VERSION 5.8 ;
BUSBITCHARS "[]" ;
DIVIDERCHAR "/" ;
UNITS
    DATABASE MICRONS 1000 ;
END UNITS

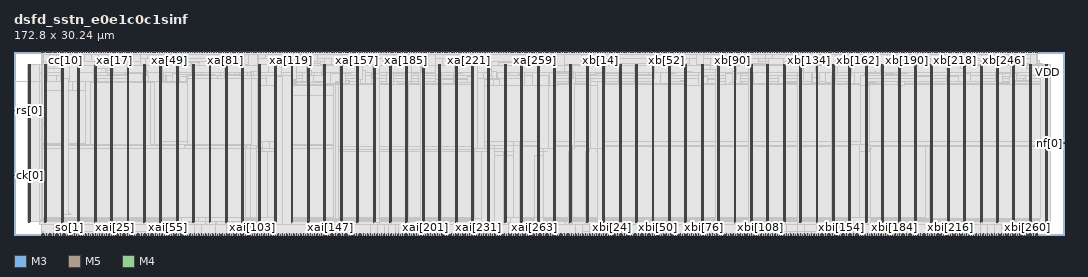
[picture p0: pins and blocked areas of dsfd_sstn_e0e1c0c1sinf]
MACRO dsfd_sstn_e0e1c0c1sinf
  FOREIGN dsfd_sstn_e0e1c0c1sinf 0 0 ;
  CLASS BLOCK ;
  SIZE 172.8 BY 30.24 ;
  PIN c0[0]
    DIRECTION INPUT ;
    USE SIGNAL ;
    PORT
      LAYER M3 ;
        RECT  4.464 30.096 4.482 30.24 ;
    END
  END c0[0]
  PIN c0[1]
    DIRECTION INPUT ;
    USE SIGNAL ;
    PORT
      LAYER M5 ;
        RECT  4.752 30.048 4.776 30.24 ;
    END
  END c0[1]
  PIN c1[0]
    DIRECTION INPUT ;
    USE SIGNAL ;
    PORT
      LAYER M3 ;
        RECT  5.04 30.096 5.058 30.24 ;
    END
  END c1[0]
  PIN c1[1]
    DIRECTION INPUT ;
    USE SIGNAL ;
    PORT
      LAYER M5 ;
        RECT  5.328 30.048 5.352 30.24 ;
    END
  END c1[1]
  PIN cc[0]
    DIRECTION OUTPUT ;
    USE SIGNAL ;
    PORT
      LAYER M3 ;
        RECT  5.58 30.096 5.598 30.24 ;
    END
  END cc[0]
  PIN cc[10]
    DIRECTION OUTPUT ;
    USE SIGNAL ;
    PORT
      LAYER M3 ;
        RECT  8.46 30.096 8.478 30.24 ;
    END
  END cc[10]
  PIN cc[11]
    DIRECTION OUTPUT ;
    USE SIGNAL ;
    PORT
      LAYER M5 ;
        RECT  8.736 30.048 8.76 30.24 ;
    END
  END cc[11]
  PIN cc[12]
    DIRECTION OUTPUT ;
    USE SIGNAL ;
    PORT
      LAYER M3 ;
        RECT  9.036 30.096 9.054 30.24 ;
    END
  END cc[12]
  PIN cc[13]
    DIRECTION OUTPUT ;
    USE SIGNAL ;
    PORT
      LAYER M5 ;
        RECT  9.312 30.048 9.336 30.24 ;
    END
  END cc[13]
  PIN cc[14]
    DIRECTION OUTPUT ;
    USE SIGNAL ;
    PORT
      LAYER M3 ;
        RECT  9.612 30.096 9.63 30.24 ;
    END
  END cc[14]
  PIN cc[1]
    DIRECTION OUTPUT ;
    USE SIGNAL ;
    PORT
      LAYER M5 ;
        RECT  5.904 30.048 5.928 30.24 ;
    END
  END cc[1]
  PIN cc[2]
    DIRECTION OUTPUT ;
    USE SIGNAL ;
    PORT
      LAYER M3 ;
        RECT  6.156 30.096 6.174 30.24 ;
    END
  END cc[2]
  PIN cc[3]
    DIRECTION OUTPUT ;
    USE SIGNAL ;
    PORT
      LAYER M5 ;
        RECT  6.432 30.048 6.456 30.24 ;
    END
  END cc[3]
  PIN cc[4]
    DIRECTION OUTPUT ;
    USE SIGNAL ;
    PORT
      LAYER M3 ;
        RECT  6.732 30.096 6.75 30.24 ;
    END
  END cc[4]
  PIN cc[5]
    DIRECTION OUTPUT ;
    USE SIGNAL ;
    PORT
      LAYER M5 ;
        RECT  7.008 30.048 7.032 30.24 ;
    END
  END cc[5]
  PIN cc[6]
    DIRECTION OUTPUT ;
    USE SIGNAL ;
    PORT
      LAYER M3 ;
        RECT  7.308 30.096 7.326 30.24 ;
    END
  END cc[6]
  PIN cc[7]
    DIRECTION OUTPUT ;
    USE SIGNAL ;
    PORT
      LAYER M5 ;
        RECT  7.584 30.048 7.608 30.24 ;
    END
  END cc[7]
  PIN cc[8]
    DIRECTION OUTPUT ;
    USE SIGNAL ;
    PORT
      LAYER M3 ;
        RECT  7.884 30.096 7.902 30.24 ;
    END
  END cc[8]
  PIN cc[9]
    DIRECTION OUTPUT ;
    USE SIGNAL ;
    PORT
      LAYER M5 ;
        RECT  8.16 30.048 8.184 30.24 ;
    END
  END cc[9]
  PIN cci[0]
    DIRECTION INPUT ;
    USE SIGNAL ;
    PORT
      LAYER M3 ;
        RECT  4.464 0 4.482 0.144 ;
    END
  END cci[0]
  PIN cci[10]
    DIRECTION INPUT ;
    USE SIGNAL ;
    PORT
      LAYER M3 ;
        RECT  7.344 0 7.362 0.144 ;
    END
  END cci[10]
  PIN cci[11]
    DIRECTION INPUT ;
    USE SIGNAL ;
    PORT
      LAYER M5 ;
        RECT  7.632 0 7.656 0.192 ;
    END
  END cci[11]
  PIN cci[12]
    DIRECTION INPUT ;
    USE SIGNAL ;
    PORT
      LAYER M3 ;
        RECT  7.92 0 7.938 0.144 ;
    END
  END cci[12]
  PIN cci[13]
    DIRECTION INPUT ;
    USE SIGNAL ;
    PORT
      LAYER M5 ;
        RECT  8.208 0 8.232 0.192 ;
    END
  END cci[13]
  PIN cci[14]
    DIRECTION INPUT ;
    USE SIGNAL ;
    PORT
      LAYER M3 ;
        RECT  8.532 0 8.55 0.144 ;
    END
  END cci[14]
  PIN cci[1]
    DIRECTION INPUT ;
    USE SIGNAL ;
    PORT
      LAYER M5 ;
        RECT  4.752 0 4.776 0.192 ;
    END
  END cci[1]
  PIN cci[2]
    DIRECTION INPUT ;
    USE SIGNAL ;
    PORT
      LAYER M3 ;
        RECT  5.04 0 5.058 0.144 ;
    END
  END cci[2]
  PIN cci[3]
    DIRECTION INPUT ;
    USE SIGNAL ;
    PORT
      LAYER M5 ;
        RECT  5.328 0 5.352 0.192 ;
    END
  END cci[3]
  PIN cci[4]
    DIRECTION INPUT ;
    USE SIGNAL ;
    PORT
      LAYER M3 ;
        RECT  5.616 0 5.634 0.144 ;
    END
  END cci[4]
  PIN cci[5]
    DIRECTION INPUT ;
    USE SIGNAL ;
    PORT
      LAYER M5 ;
        RECT  5.904 0 5.928 0.192 ;
    END
  END cci[5]
  PIN cci[6]
    DIRECTION INPUT ;
    USE SIGNAL ;
    PORT
      LAYER M3 ;
        RECT  6.192 0 6.21 0.144 ;
    END
  END cci[6]
  PIN cci[7]
    DIRECTION INPUT ;
    USE SIGNAL ;
    PORT
      LAYER M5 ;
        RECT  6.48 0 6.504 0.192 ;
    END
  END cci[7]
  PIN cci[8]
    DIRECTION INPUT ;
    USE SIGNAL ;
    PORT
      LAYER M3 ;
        RECT  6.768 0 6.786 0.144 ;
    END
  END cci[8]
  PIN cci[9]
    DIRECTION INPUT ;
    USE SIGNAL ;
    PORT
      LAYER M5 ;
        RECT  7.056 0 7.08 0.192 ;
    END
  END cci[9]
  PIN ck[0]
    DIRECTION INPUT ;
    USE SIGNAL ;
    PORT
      LAYER M4 ;
        RECT  0 9.744 0.192 9.768 ;
    END
    PORT
      LAYER M4 ;
        RECT  0.156 9.744 0.275 9.768 ;
    END
  END ck[0]
  PIN e0[0]
    DIRECTION INPUT ;
    USE SIGNAL ;
    PORT
      LAYER M5 ;
        RECT  9.888 30.048 9.912 30.24 ;
    END
  END e0[0]
  PIN e0[1]
    DIRECTION INPUT ;
    USE SIGNAL ;
    PORT
      LAYER M3 ;
        RECT  10.188 30.096 10.206 30.24 ;
    END
  END e0[1]
  PIN e1[0]
    DIRECTION INPUT ;
    USE SIGNAL ;
    PORT
      LAYER M5 ;
        RECT  10.464 30.048 10.488 30.24 ;
    END
  END e1[0]
  PIN e1[1]
    DIRECTION INPUT ;
    USE SIGNAL ;
    PORT
      LAYER M3 ;
        RECT  10.728 30.096 10.746 30.24 ;
    END
  END e1[1]
  PIN nf[0]
    DIRECTION INPUT ;
    USE SIGNAL ;
    PORT
      LAYER M4 ;
        RECT  172.608 15.12 172.8 15.144 ;
    END
    PORT
      LAYER M4 ;
        RECT  172.141 15.12 172.62 15.144 ;
    END
  END nf[0]
  PIN rs[0]
    DIRECTION INPUT ;
    USE SIGNAL ;
    PORT
      LAYER M4 ;
        RECT  0 20.544 0.192 20.568 ;
    END
    PORT
      LAYER M4 ;
        RECT  0.156 20.544 0.245 20.568 ;
    END
  END rs[0]
  PIN si[0]
    DIRECTION INPUT ;
    USE SIGNAL ;
    PORT
      LAYER M5 ;
        RECT  11.04 30.048 11.064 30.24 ;
    END
  END si[0]
  PIN si[1]
    DIRECTION INPUT ;
    USE SIGNAL ;
    PORT
      LAYER M3 ;
        RECT  11.304 30.096 11.322 30.24 ;
    END
  END si[1]
  PIN so[0]
    DIRECTION OUTPUT ;
    USE SIGNAL ;
    PORT
      LAYER M5 ;
        RECT  8.784 0 8.808 0.192 ;
    END
  END so[0]
  PIN so[1]
    DIRECTION OUTPUT ;
    USE SIGNAL ;
    PORT
      LAYER M3 ;
        RECT  9.108 0 9.126 0.144 ;
    END
  END so[1]
  PIN xa[0]
    DIRECTION OUTPUT ;
    USE SIGNAL ;
    PORT
      LAYER M5 ;
        RECT  11.616 30.048 11.64 30.24 ;
    END
  END xa[0]
  PIN xa[100]
    DIRECTION OUTPUT ;
    USE SIGNAL ;
    PORT
      LAYER M5 ;
        RECT  40.224 30.048 40.248 30.24 ;
    END
  END xa[100]
  PIN xa[101]
    DIRECTION OUTPUT ;
    USE SIGNAL ;
    PORT
      LAYER M3 ;
        RECT  40.5 30.096 40.518 30.24 ;
    END
  END xa[101]
  PIN xa[102]
    DIRECTION OUTPUT ;
    USE SIGNAL ;
    PORT
      LAYER M5 ;
        RECT  40.752 30.048 40.776 30.24 ;
    END
  END xa[102]
  PIN xa[103]
    DIRECTION OUTPUT ;
    USE SIGNAL ;
    PORT
      LAYER M3 ;
        RECT  41.076 30.096 41.094 30.24 ;
    END
  END xa[103]
  PIN xa[104]
    DIRECTION OUTPUT ;
    USE SIGNAL ;
    PORT
      LAYER M5 ;
        RECT  41.328 30.048 41.352 30.24 ;
    END
  END xa[104]
  PIN xa[105]
    DIRECTION OUTPUT ;
    USE SIGNAL ;
    PORT
      LAYER M3 ;
        RECT  41.616 30.096 41.634 30.24 ;
    END
  END xa[105]
  PIN xa[106]
    DIRECTION OUTPUT ;
    USE SIGNAL ;
    PORT
      LAYER M5 ;
        RECT  41.904 30.048 41.928 30.24 ;
    END
  END xa[106]
  PIN xa[107]
    DIRECTION OUTPUT ;
    USE SIGNAL ;
    PORT
      LAYER M3 ;
        RECT  42.192 30.096 42.21 30.24 ;
    END
  END xa[107]
  PIN xa[108]
    DIRECTION OUTPUT ;
    USE SIGNAL ;
    PORT
      LAYER M5 ;
        RECT  42.48 30.048 42.504 30.24 ;
    END
  END xa[108]
  PIN xa[109]
    DIRECTION OUTPUT ;
    USE SIGNAL ;
    PORT
      LAYER M3 ;
        RECT  42.768 30.096 42.786 30.24 ;
    END
  END xa[109]
  PIN xa[10]
    DIRECTION OUTPUT ;
    USE SIGNAL ;
    PORT
      LAYER M5 ;
        RECT  14.448 30.048 14.472 30.24 ;
    END
  END xa[10]
  PIN xa[110]
    DIRECTION OUTPUT ;
    USE SIGNAL ;
    PORT
      LAYER M5 ;
        RECT  43.056 30.048 43.08 30.24 ;
    END
  END xa[110]
  PIN xa[111]
    DIRECTION OUTPUT ;
    USE SIGNAL ;
    PORT
      LAYER M3 ;
        RECT  43.344 30.096 43.362 30.24 ;
    END
  END xa[111]
  PIN xa[112]
    DIRECTION OUTPUT ;
    USE SIGNAL ;
    PORT
      LAYER M5 ;
        RECT  43.632 30.048 43.656 30.24 ;
    END
  END xa[112]
  PIN xa[113]
    DIRECTION OUTPUT ;
    USE SIGNAL ;
    PORT
      LAYER M3 ;
        RECT  43.92 30.096 43.938 30.24 ;
    END
  END xa[113]
  PIN xa[114]
    DIRECTION OUTPUT ;
    USE SIGNAL ;
    PORT
      LAYER M5 ;
        RECT  44.208 30.048 44.232 30.24 ;
    END
  END xa[114]
  PIN xa[115]
    DIRECTION OUTPUT ;
    USE SIGNAL ;
    PORT
      LAYER M3 ;
        RECT  44.496 30.096 44.514 30.24 ;
    END
  END xa[115]
  PIN xa[116]
    DIRECTION OUTPUT ;
    USE SIGNAL ;
    PORT
      LAYER M5 ;
        RECT  44.784 30.048 44.808 30.24 ;
    END
  END xa[116]
  PIN xa[117]
    DIRECTION OUTPUT ;
    USE SIGNAL ;
    PORT
      LAYER M3 ;
        RECT  45.072 30.096 45.09 30.24 ;
    END
  END xa[117]
  PIN xa[118]
    DIRECTION OUTPUT ;
    USE SIGNAL ;
    PORT
      LAYER M5 ;
        RECT  45.36 30.048 45.384 30.24 ;
    END
  END xa[118]
  PIN xa[119]
    DIRECTION OUTPUT ;
    USE SIGNAL ;
    PORT
      LAYER M3 ;
        RECT  45.648 30.096 45.666 30.24 ;
    END
  END xa[119]
  PIN xa[11]
    DIRECTION OUTPUT ;
    USE SIGNAL ;
    PORT
      LAYER M3 ;
        RECT  14.76 30.096 14.778 30.24 ;
    END
  END xa[11]
  PIN xa[120]
    DIRECTION OUTPUT ;
    USE SIGNAL ;
    PORT
      LAYER M5 ;
        RECT  45.936 30.048 45.96 30.24 ;
    END
  END xa[120]
  PIN xa[121]
    DIRECTION OUTPUT ;
    USE SIGNAL ;
    PORT
      LAYER M3 ;
        RECT  46.224 30.096 46.242 30.24 ;
    END
  END xa[121]
  PIN xa[122]
    DIRECTION OUTPUT ;
    USE SIGNAL ;
    PORT
      LAYER M5 ;
        RECT  46.512 30.048 46.536 30.24 ;
    END
  END xa[122]
  PIN xa[123]
    DIRECTION OUTPUT ;
    USE SIGNAL ;
    PORT
      LAYER M3 ;
        RECT  46.764 30.096 46.782 30.24 ;
    END
  END xa[123]
  PIN xa[124]
    DIRECTION OUTPUT ;
    USE SIGNAL ;
    PORT
      LAYER M5 ;
        RECT  47.04 30.048 47.064 30.24 ;
    END
  END xa[124]
  PIN xa[125]
    DIRECTION OUTPUT ;
    USE SIGNAL ;
    PORT
      LAYER M3 ;
        RECT  47.34 30.096 47.358 30.24 ;
    END
  END xa[125]
  PIN xa[126]
    DIRECTION OUTPUT ;
    USE SIGNAL ;
    PORT
      LAYER M5 ;
        RECT  47.616 30.048 47.64 30.24 ;
    END
  END xa[126]
  PIN xa[127]
    DIRECTION OUTPUT ;
    USE SIGNAL ;
    PORT
      LAYER M3 ;
        RECT  47.916 30.096 47.934 30.24 ;
    END
  END xa[127]
  PIN xa[128]
    DIRECTION OUTPUT ;
    USE SIGNAL ;
    PORT
      LAYER M5 ;
        RECT  48.192 30.048 48.216 30.24 ;
    END
  END xa[128]
  PIN xa[129]
    DIRECTION OUTPUT ;
    USE SIGNAL ;
    PORT
      LAYER M3 ;
        RECT  48.492 30.096 48.51 30.24 ;
    END
  END xa[129]
  PIN xa[12]
    DIRECTION OUTPUT ;
    USE SIGNAL ;
    PORT
      LAYER M5 ;
        RECT  15.024 30.048 15.048 30.24 ;
    END
  END xa[12]
  PIN xa[130]
    DIRECTION OUTPUT ;
    USE SIGNAL ;
    PORT
      LAYER M5 ;
        RECT  48.768 30.048 48.792 30.24 ;
    END
  END xa[130]
  PIN xa[131]
    DIRECTION OUTPUT ;
    USE SIGNAL ;
    PORT
      LAYER M3 ;
        RECT  49.068 30.096 49.086 30.24 ;
    END
  END xa[131]
  PIN xa[132]
    DIRECTION OUTPUT ;
    USE SIGNAL ;
    PORT
      LAYER M5 ;
        RECT  49.344 30.048 49.368 30.24 ;
    END
  END xa[132]
  PIN xa[133]
    DIRECTION OUTPUT ;
    USE SIGNAL ;
    PORT
      LAYER M3 ;
        RECT  49.644 30.096 49.662 30.24 ;
    END
  END xa[133]
  PIN xa[134]
    DIRECTION OUTPUT ;
    USE SIGNAL ;
    PORT
      LAYER M5 ;
        RECT  49.92 30.048 49.944 30.24 ;
    END
  END xa[134]
  PIN xa[135]
    DIRECTION OUTPUT ;
    USE SIGNAL ;
    PORT
      LAYER M3 ;
        RECT  50.22 30.096 50.238 30.24 ;
    END
  END xa[135]
  PIN xa[136]
    DIRECTION OUTPUT ;
    USE SIGNAL ;
    PORT
      LAYER M5 ;
        RECT  50.496 30.048 50.52 30.24 ;
    END
  END xa[136]
  PIN xa[137]
    DIRECTION OUTPUT ;
    USE SIGNAL ;
    PORT
      LAYER M3 ;
        RECT  50.796 30.096 50.814 30.24 ;
    END
  END xa[137]
  PIN xa[138]
    DIRECTION OUTPUT ;
    USE SIGNAL ;
    PORT
      LAYER M5 ;
        RECT  51.072 30.048 51.096 30.24 ;
    END
  END xa[138]
  PIN xa[139]
    DIRECTION OUTPUT ;
    USE SIGNAL ;
    PORT
      LAYER M3 ;
        RECT  51.372 30.096 51.39 30.24 ;
    END
  END xa[139]
  PIN xa[13]
    DIRECTION OUTPUT ;
    USE SIGNAL ;
    PORT
      LAYER M3 ;
        RECT  15.336 30.096 15.354 30.24 ;
    END
  END xa[13]
  PIN xa[140]
    DIRECTION OUTPUT ;
    USE SIGNAL ;
    PORT
      LAYER M5 ;
        RECT  51.648 30.048 51.672 30.24 ;
    END
  END xa[140]
  PIN xa[141]
    DIRECTION OUTPUT ;
    USE SIGNAL ;
    PORT
      LAYER M3 ;
        RECT  51.912 30.096 51.93 30.24 ;
    END
  END xa[141]
  PIN xa[142]
    DIRECTION OUTPUT ;
    USE SIGNAL ;
    PORT
      LAYER M5 ;
        RECT  52.224 30.048 52.248 30.24 ;
    END
  END xa[142]
  PIN xa[143]
    DIRECTION OUTPUT ;
    USE SIGNAL ;
    PORT
      LAYER M3 ;
        RECT  52.488 30.096 52.506 30.24 ;
    END
  END xa[143]
  PIN xa[144]
    DIRECTION OUTPUT ;
    USE SIGNAL ;
    PORT
      LAYER M5 ;
        RECT  52.8 30.048 52.824 30.24 ;
    END
  END xa[144]
  PIN xa[145]
    DIRECTION OUTPUT ;
    USE SIGNAL ;
    PORT
      LAYER M3 ;
        RECT  53.064 30.096 53.082 30.24 ;
    END
  END xa[145]
  PIN xa[146]
    DIRECTION OUTPUT ;
    USE SIGNAL ;
    PORT
      LAYER M5 ;
        RECT  53.376 30.048 53.4 30.24 ;
    END
  END xa[146]
  PIN xa[147]
    DIRECTION OUTPUT ;
    USE SIGNAL ;
    PORT
      LAYER M3 ;
        RECT  53.64 30.096 53.658 30.24 ;
    END
  END xa[147]
  PIN xa[148]
    DIRECTION OUTPUT ;
    USE SIGNAL ;
    PORT
      LAYER M5 ;
        RECT  53.904 30.048 53.928 30.24 ;
    END
  END xa[148]
  PIN xa[149]
    DIRECTION OUTPUT ;
    USE SIGNAL ;
    PORT
      LAYER M3 ;
        RECT  54.216 30.096 54.234 30.24 ;
    END
  END xa[149]
  PIN xa[14]
    DIRECTION OUTPUT ;
    USE SIGNAL ;
    PORT
      LAYER M5 ;
        RECT  15.6 30.048 15.624 30.24 ;
    END
  END xa[14]
  PIN xa[150]
    DIRECTION OUTPUT ;
    USE SIGNAL ;
    PORT
      LAYER M5 ;
        RECT  54.48 30.048 54.504 30.24 ;
    END
  END xa[150]
  PIN xa[151]
    DIRECTION OUTPUT ;
    USE SIGNAL ;
    PORT
      LAYER M3 ;
        RECT  54.792 30.096 54.81 30.24 ;
    END
  END xa[151]
  PIN xa[152]
    DIRECTION OUTPUT ;
    USE SIGNAL ;
    PORT
      LAYER M5 ;
        RECT  55.056 30.048 55.08 30.24 ;
    END
  END xa[152]
  PIN xa[153]
    DIRECTION OUTPUT ;
    USE SIGNAL ;
    PORT
      LAYER M3 ;
        RECT  55.368 30.096 55.386 30.24 ;
    END
  END xa[153]
  PIN xa[154]
    DIRECTION OUTPUT ;
    USE SIGNAL ;
    PORT
      LAYER M5 ;
        RECT  55.632 30.048 55.656 30.24 ;
    END
  END xa[154]
  PIN xa[155]
    DIRECTION OUTPUT ;
    USE SIGNAL ;
    PORT
      LAYER M3 ;
        RECT  55.944 30.096 55.962 30.24 ;
    END
  END xa[155]
  PIN xa[156]
    DIRECTION OUTPUT ;
    USE SIGNAL ;
    PORT
      LAYER M5 ;
        RECT  56.208 30.048 56.232 30.24 ;
    END
  END xa[156]
  PIN xa[157]
    DIRECTION OUTPUT ;
    USE SIGNAL ;
    PORT
      LAYER M3 ;
        RECT  56.52 30.096 56.538 30.24 ;
    END
  END xa[157]
  PIN xa[158]
    DIRECTION OUTPUT ;
    USE SIGNAL ;
    PORT
      LAYER M5 ;
        RECT  56.784 30.048 56.808 30.24 ;
    END
  END xa[158]
  PIN xa[159]
    DIRECTION OUTPUT ;
    USE SIGNAL ;
    PORT
      LAYER M3 ;
        RECT  57.06 30.096 57.078 30.24 ;
    END
  END xa[159]
  PIN xa[15]
    DIRECTION OUTPUT ;
    USE SIGNAL ;
    PORT
      LAYER M3 ;
        RECT  15.876 30.096 15.894 30.24 ;
    END
  END xa[15]
  PIN xa[160]
    DIRECTION OUTPUT ;
    USE SIGNAL ;
    PORT
      LAYER M5 ;
        RECT  57.36 30.048 57.384 30.24 ;
    END
  END xa[160]
  PIN xa[161]
    DIRECTION OUTPUT ;
    USE SIGNAL ;
    PORT
      LAYER M3 ;
        RECT  57.636 30.096 57.654 30.24 ;
    END
  END xa[161]
  PIN xa[162]
    DIRECTION OUTPUT ;
    USE SIGNAL ;
    PORT
      LAYER M5 ;
        RECT  57.936 30.048 57.96 30.24 ;
    END
  END xa[162]
  PIN xa[163]
    DIRECTION OUTPUT ;
    USE SIGNAL ;
    PORT
      LAYER M3 ;
        RECT  58.212 30.096 58.23 30.24 ;
    END
  END xa[163]
  PIN xa[164]
    DIRECTION OUTPUT ;
    USE SIGNAL ;
    PORT
      LAYER M5 ;
        RECT  58.512 30.048 58.536 30.24 ;
    END
  END xa[164]
  PIN xa[165]
    DIRECTION OUTPUT ;
    USE SIGNAL ;
    PORT
      LAYER M3 ;
        RECT  58.788 30.096 58.806 30.24 ;
    END
  END xa[165]
  PIN xa[166]
    DIRECTION OUTPUT ;
    USE SIGNAL ;
    PORT
      LAYER M5 ;
        RECT  59.088 30.048 59.112 30.24 ;
    END
  END xa[166]
  PIN xa[167]
    DIRECTION OUTPUT ;
    USE SIGNAL ;
    PORT
      LAYER M3 ;
        RECT  59.364 30.096 59.382 30.24 ;
    END
  END xa[167]
  PIN xa[168]
    DIRECTION OUTPUT ;
    USE SIGNAL ;
    PORT
      LAYER M5 ;
        RECT  59.664 30.048 59.688 30.24 ;
    END
  END xa[168]
  PIN xa[169]
    DIRECTION OUTPUT ;
    USE SIGNAL ;
    PORT
      LAYER M3 ;
        RECT  59.94 30.096 59.958 30.24 ;
    END
  END xa[169]
  PIN xa[16]
    DIRECTION OUTPUT ;
    USE SIGNAL ;
    PORT
      LAYER M5 ;
        RECT  16.176 30.048 16.2 30.24 ;
    END
  END xa[16]
  PIN xa[170]
    DIRECTION OUTPUT ;
    USE SIGNAL ;
    PORT
      LAYER M5 ;
        RECT  60.24 30.048 60.264 30.24 ;
    END
  END xa[170]
  PIN xa[171]
    DIRECTION OUTPUT ;
    USE SIGNAL ;
    PORT
      LAYER M3 ;
        RECT  60.516 30.096 60.534 30.24 ;
    END
  END xa[171]
  PIN xa[172]
    DIRECTION OUTPUT ;
    USE SIGNAL ;
    PORT
      LAYER M5 ;
        RECT  60.768 30.048 60.792 30.24 ;
    END
  END xa[172]
  PIN xa[173]
    DIRECTION OUTPUT ;
    USE SIGNAL ;
    PORT
      LAYER M3 ;
        RECT  61.092 30.096 61.11 30.24 ;
    END
  END xa[173]
  PIN xa[174]
    DIRECTION OUTPUT ;
    USE SIGNAL ;
    PORT
      LAYER M5 ;
        RECT  61.344 30.048 61.368 30.24 ;
    END
  END xa[174]
  PIN xa[175]
    DIRECTION OUTPUT ;
    USE SIGNAL ;
    PORT
      LAYER M3 ;
        RECT  61.668 30.096 61.686 30.24 ;
    END
  END xa[175]
  PIN xa[176]
    DIRECTION OUTPUT ;
    USE SIGNAL ;
    PORT
      LAYER M5 ;
        RECT  61.92 30.048 61.944 30.24 ;
    END
  END xa[176]
  PIN xa[177]
    DIRECTION OUTPUT ;
    USE SIGNAL ;
    PORT
      LAYER M3 ;
        RECT  62.208 30.096 62.226 30.24 ;
    END
  END xa[177]
  PIN xa[178]
    DIRECTION OUTPUT ;
    USE SIGNAL ;
    PORT
      LAYER M5 ;
        RECT  62.496 30.048 62.52 30.24 ;
    END
  END xa[178]
  PIN xa[179]
    DIRECTION OUTPUT ;
    USE SIGNAL ;
    PORT
      LAYER M3 ;
        RECT  62.784 30.096 62.802 30.24 ;
    END
  END xa[179]
  PIN xa[17]
    DIRECTION OUTPUT ;
    USE SIGNAL ;
    PORT
      LAYER M3 ;
        RECT  16.452 30.096 16.47 30.24 ;
    END
  END xa[17]
  PIN xa[180]
    DIRECTION OUTPUT ;
    USE SIGNAL ;
    PORT
      LAYER M5 ;
        RECT  63.072 30.048 63.096 30.24 ;
    END
  END xa[180]
  PIN xa[181]
    DIRECTION OUTPUT ;
    USE SIGNAL ;
    PORT
      LAYER M3 ;
        RECT  63.36 30.096 63.378 30.24 ;
    END
    PORT
      LAYER M3 ;
        RECT  63.324 30.108 63.45 30.173 ;
    END
  END xa[181]
  PIN xa[182]
    DIRECTION OUTPUT ;
    USE SIGNAL ;
    PORT
      LAYER M5 ;
        RECT  63.648 30.048 63.672 30.24 ;
    END
  END xa[182]
  PIN xa[183]
    DIRECTION OUTPUT ;
    USE SIGNAL ;
    PORT
      LAYER M3 ;
        RECT  63.936 30.096 63.954 30.24 ;
    END
  END xa[183]
  PIN xa[184]
    DIRECTION OUTPUT ;
    USE SIGNAL ;
    PORT
      LAYER M5 ;
        RECT  64.224 30.048 64.248 30.24 ;
    END
  END xa[184]
  PIN xa[185]
    DIRECTION OUTPUT ;
    USE SIGNAL ;
    PORT
      LAYER M3 ;
        RECT  64.512 30.096 64.53 30.24 ;
    END
  END xa[185]
  PIN xa[186]
    DIRECTION OUTPUT ;
    USE SIGNAL ;
    PORT
      LAYER M5 ;
        RECT  64.8 30.048 64.824 30.24 ;
    END
  END xa[186]
  PIN xa[187]
    DIRECTION OUTPUT ;
    USE SIGNAL ;
    PORT
      LAYER M3 ;
        RECT  65.088 30.096 65.106 30.24 ;
    END
  END xa[187]
  PIN xa[188]
    DIRECTION OUTPUT ;
    USE SIGNAL ;
    PORT
      LAYER M5 ;
        RECT  65.376 30.048 65.4 30.24 ;
    END
  END xa[188]
  PIN xa[189]
    DIRECTION OUTPUT ;
    USE SIGNAL ;
    PORT
      LAYER M3 ;
        RECT  65.664 30.096 65.682 30.24 ;
    END
  END xa[189]
  PIN xa[18]
    DIRECTION OUTPUT ;
    USE SIGNAL ;
    PORT
      LAYER M5 ;
        RECT  16.752 30.048 16.776 30.24 ;
    END
  END xa[18]
  PIN xa[190]
    DIRECTION OUTPUT ;
    USE SIGNAL ;
    PORT
      LAYER M5 ;
        RECT  65.952 30.048 65.976 30.24 ;
    END
  END xa[190]
  PIN xa[191]
    DIRECTION OUTPUT ;
    USE SIGNAL ;
    PORT
      LAYER M3 ;
        RECT  66.24 30.096 66.258 30.24 ;
    END
  END xa[191]
  PIN xa[192]
    DIRECTION OUTPUT ;
    USE SIGNAL ;
    PORT
      LAYER M5 ;
        RECT  66.528 30.048 66.552 30.24 ;
    END
  END xa[192]
  PIN xa[193]
    DIRECTION OUTPUT ;
    USE SIGNAL ;
    PORT
      LAYER M3 ;
        RECT  66.816 30.096 66.834 30.24 ;
    END
  END xa[193]
  PIN xa[194]
    DIRECTION OUTPUT ;
    USE SIGNAL ;
    PORT
      LAYER M5 ;
        RECT  67.104 30.048 67.128 30.24 ;
    END
  END xa[194]
  PIN xa[195]
    DIRECTION OUTPUT ;
    USE SIGNAL ;
    PORT
      LAYER M3 ;
        RECT  67.356 30.096 67.374 30.24 ;
    END
  END xa[195]
  PIN xa[196]
    DIRECTION OUTPUT ;
    USE SIGNAL ;
    PORT
      LAYER M5 ;
        RECT  67.632 30.048 67.656 30.24 ;
    END
  END xa[196]
  PIN xa[197]
    DIRECTION OUTPUT ;
    USE SIGNAL ;
    PORT
      LAYER M3 ;
        RECT  67.932 30.096 67.95 30.24 ;
    END
  END xa[197]
  PIN xa[198]
    DIRECTION OUTPUT ;
    USE SIGNAL ;
    PORT
      LAYER M5 ;
        RECT  68.208 30.048 68.232 30.24 ;
    END
  END xa[198]
  PIN xa[199]
    DIRECTION OUTPUT ;
    USE SIGNAL ;
    PORT
      LAYER M3 ;
        RECT  68.508 30.096 68.526 30.24 ;
    END
  END xa[199]
  PIN xa[19]
    DIRECTION OUTPUT ;
    USE SIGNAL ;
    PORT
      LAYER M3 ;
        RECT  17.028 30.096 17.046 30.24 ;
    END
  END xa[19]
  PIN xa[1]
    DIRECTION OUTPUT ;
    USE SIGNAL ;
    PORT
      LAYER M3 ;
        RECT  11.88 30.096 11.898 30.24 ;
    END
  END xa[1]
  PIN xa[200]
    DIRECTION OUTPUT ;
    USE SIGNAL ;
    PORT
      LAYER M5 ;
        RECT  68.784 30.048 68.808 30.24 ;
    END
  END xa[200]
  PIN xa[201]
    DIRECTION OUTPUT ;
    USE SIGNAL ;
    PORT
      LAYER M3 ;
        RECT  69.084 30.096 69.102 30.24 ;
    END
  END xa[201]
  PIN xa[202]
    DIRECTION OUTPUT ;
    USE SIGNAL ;
    PORT
      LAYER M5 ;
        RECT  69.36 30.048 69.384 30.24 ;
    END
  END xa[202]
  PIN xa[203]
    DIRECTION OUTPUT ;
    USE SIGNAL ;
    PORT
      LAYER M3 ;
        RECT  69.66 30.096 69.678 30.24 ;
    END
  END xa[203]
  PIN xa[204]
    DIRECTION OUTPUT ;
    USE SIGNAL ;
    PORT
      LAYER M5 ;
        RECT  69.936 30.048 69.96 30.24 ;
    END
  END xa[204]
  PIN xa[205]
    DIRECTION OUTPUT ;
    USE SIGNAL ;
    PORT
      LAYER M3 ;
        RECT  70.236 30.096 70.254 30.24 ;
    END
  END xa[205]
  PIN xa[206]
    DIRECTION OUTPUT ;
    USE SIGNAL ;
    PORT
      LAYER M5 ;
        RECT  70.512 30.048 70.536 30.24 ;
    END
  END xa[206]
  PIN xa[207]
    DIRECTION OUTPUT ;
    USE SIGNAL ;
    PORT
      LAYER M3 ;
        RECT  70.812 30.096 70.83 30.24 ;
    END
  END xa[207]
  PIN xa[208]
    DIRECTION OUTPUT ;
    USE SIGNAL ;
    PORT
      LAYER M5 ;
        RECT  71.088 30.048 71.112 30.24 ;
    END
  END xa[208]
  PIN xa[209]
    DIRECTION OUTPUT ;
    USE SIGNAL ;
    PORT
      LAYER M3 ;
        RECT  71.388 30.096 71.406 30.24 ;
    END
  END xa[209]
  PIN xa[20]
    DIRECTION OUTPUT ;
    USE SIGNAL ;
    PORT
      LAYER M5 ;
        RECT  17.328 30.048 17.352 30.24 ;
    END
  END xa[20]
  PIN xa[210]
    DIRECTION OUTPUT ;
    USE SIGNAL ;
    PORT
      LAYER M5 ;
        RECT  71.664 30.048 71.688 30.24 ;
    END
  END xa[210]
  PIN xa[211]
    DIRECTION OUTPUT ;
    USE SIGNAL ;
    PORT
      LAYER M3 ;
        RECT  71.964 30.096 71.982 30.24 ;
    END
  END xa[211]
  PIN xa[212]
    DIRECTION OUTPUT ;
    USE SIGNAL ;
    PORT
      LAYER M5 ;
        RECT  72.24 30.048 72.264 30.24 ;
    END
  END xa[212]
  PIN xa[213]
    DIRECTION OUTPUT ;
    USE SIGNAL ;
    PORT
      LAYER M3 ;
        RECT  72.504 30.096 72.522 30.24 ;
    END
  END xa[213]
  PIN xa[214]
    DIRECTION OUTPUT ;
    USE SIGNAL ;
    PORT
      LAYER M5 ;
        RECT  72.816 30.048 72.84 30.24 ;
    END
  END xa[214]
  PIN xa[215]
    DIRECTION OUTPUT ;
    USE SIGNAL ;
    PORT
      LAYER M3 ;
        RECT  73.08 30.096 73.098 30.24 ;
    END
  END xa[215]
  PIN xa[216]
    DIRECTION OUTPUT ;
    USE SIGNAL ;
    PORT
      LAYER M5 ;
        RECT  73.392 30.048 73.416 30.24 ;
    END
  END xa[216]
  PIN xa[217]
    DIRECTION OUTPUT ;
    USE SIGNAL ;
    PORT
      LAYER M3 ;
        RECT  73.656 30.096 73.674 30.24 ;
    END
  END xa[217]
  PIN xa[218]
    DIRECTION OUTPUT ;
    USE SIGNAL ;
    PORT
      LAYER M5 ;
        RECT  73.968 30.048 73.992 30.24 ;
    END
  END xa[218]
  PIN xa[219]
    DIRECTION OUTPUT ;
    USE SIGNAL ;
    PORT
      LAYER M3 ;
        RECT  74.232 30.096 74.25 30.24 ;
    END
  END xa[219]
  PIN xa[21]
    DIRECTION OUTPUT ;
    USE SIGNAL ;
    PORT
      LAYER M3 ;
        RECT  17.604 30.096 17.622 30.24 ;
    END
  END xa[21]
  PIN xa[220]
    DIRECTION OUTPUT ;
    USE SIGNAL ;
    PORT
      LAYER M5 ;
        RECT  74.496 30.048 74.52 30.24 ;
    END
  END xa[220]
  PIN xa[221]
    DIRECTION OUTPUT ;
    USE SIGNAL ;
    PORT
      LAYER M3 ;
        RECT  74.808 30.096 74.826 30.24 ;
    END
  END xa[221]
  PIN xa[222]
    DIRECTION OUTPUT ;
    USE SIGNAL ;
    PORT
      LAYER M5 ;
        RECT  75.072 30.048 75.096 30.24 ;
    END
  END xa[222]
  PIN xa[223]
    DIRECTION OUTPUT ;
    USE SIGNAL ;
    PORT
      LAYER M3 ;
        RECT  75.384 30.096 75.402 30.24 ;
    END
  END xa[223]
  PIN xa[224]
    DIRECTION OUTPUT ;
    USE SIGNAL ;
    PORT
      LAYER M5 ;
        RECT  75.648 30.048 75.672 30.24 ;
    END
  END xa[224]
  PIN xa[225]
    DIRECTION OUTPUT ;
    USE SIGNAL ;
    PORT
      LAYER M3 ;
        RECT  75.96 30.096 75.978 30.24 ;
    END
  END xa[225]
  PIN xa[226]
    DIRECTION OUTPUT ;
    USE SIGNAL ;
    PORT
      LAYER M5 ;
        RECT  76.224 30.048 76.248 30.24 ;
    END
  END xa[226]
  PIN xa[227]
    DIRECTION OUTPUT ;
    USE SIGNAL ;
    PORT
      LAYER M3 ;
        RECT  76.536 30.096 76.554 30.24 ;
    END
  END xa[227]
  PIN xa[228]
    DIRECTION OUTPUT ;
    USE SIGNAL ;
    PORT
      LAYER M5 ;
        RECT  76.8 30.048 76.824 30.24 ;
    END
  END xa[228]
  PIN xa[229]
    DIRECTION OUTPUT ;
    USE SIGNAL ;
    PORT
      LAYER M3 ;
        RECT  77.112 30.096 77.13 30.24 ;
    END
  END xa[229]
  PIN xa[22]
    DIRECTION OUTPUT ;
    USE SIGNAL ;
    PORT
      LAYER M5 ;
        RECT  17.904 30.048 17.928 30.24 ;
    END
  END xa[22]
  PIN xa[230]
    DIRECTION OUTPUT ;
    USE SIGNAL ;
    PORT
      LAYER M5 ;
        RECT  77.376 30.048 77.4 30.24 ;
    END
  END xa[230]
  PIN xa[231]
    DIRECTION OUTPUT ;
    USE SIGNAL ;
    PORT
      LAYER M3 ;
        RECT  77.652 30.096 77.67 30.24 ;
    END
  END xa[231]
  PIN xa[232]
    DIRECTION OUTPUT ;
    USE SIGNAL ;
    PORT
      LAYER M5 ;
        RECT  77.952 30.048 77.976 30.24 ;
    END
  END xa[232]
  PIN xa[233]
    DIRECTION OUTPUT ;
    USE SIGNAL ;
    PORT
      LAYER M3 ;
        RECT  78.228 30.096 78.246 30.24 ;
    END
  END xa[233]
  PIN xa[234]
    DIRECTION OUTPUT ;
    USE SIGNAL ;
    PORT
      LAYER M5 ;
        RECT  78.528 30.048 78.552 30.24 ;
    END
  END xa[234]
  PIN xa[235]
    DIRECTION OUTPUT ;
    USE SIGNAL ;
    PORT
      LAYER M3 ;
        RECT  78.804 30.096 78.822 30.24 ;
    END
  END xa[235]
  PIN xa[236]
    DIRECTION OUTPUT ;
    USE SIGNAL ;
    PORT
      LAYER M5 ;
        RECT  79.104 30.048 79.128 30.24 ;
    END
  END xa[236]
  PIN xa[237]
    DIRECTION OUTPUT ;
    USE SIGNAL ;
    PORT
      LAYER M3 ;
        RECT  79.38 30.096 79.398 30.24 ;
    END
  END xa[237]
  PIN xa[238]
    DIRECTION OUTPUT ;
    USE SIGNAL ;
    PORT
      LAYER M5 ;
        RECT  79.68 30.048 79.704 30.24 ;
    END
  END xa[238]
  PIN xa[239]
    DIRECTION OUTPUT ;
    USE SIGNAL ;
    PORT
      LAYER M3 ;
        RECT  79.956 30.096 79.974 30.24 ;
    END
  END xa[239]
  PIN xa[23]
    DIRECTION OUTPUT ;
    USE SIGNAL ;
    PORT
      LAYER M3 ;
        RECT  18.18 30.096 18.198 30.24 ;
    END
  END xa[23]
  PIN xa[240]
    DIRECTION OUTPUT ;
    USE SIGNAL ;
    PORT
      LAYER M5 ;
        RECT  80.256 30.048 80.28 30.24 ;
    END
  END xa[240]
  PIN xa[241]
    DIRECTION OUTPUT ;
    USE SIGNAL ;
    PORT
      LAYER M3 ;
        RECT  80.532 30.096 80.55 30.24 ;
    END
  END xa[241]
  PIN xa[242]
    DIRECTION OUTPUT ;
    USE SIGNAL ;
    PORT
      LAYER M5 ;
        RECT  80.832 30.048 80.856 30.24 ;
    END
  END xa[242]
  PIN xa[243]
    DIRECTION OUTPUT ;
    USE SIGNAL ;
    PORT
      LAYER M3 ;
        RECT  81.108 30.096 81.126 30.24 ;
    END
  END xa[243]
  PIN xa[244]
    DIRECTION OUTPUT ;
    USE SIGNAL ;
    PORT
      LAYER M5 ;
        RECT  81.36 30.048 81.384 30.24 ;
    END
  END xa[244]
  PIN xa[245]
    DIRECTION OUTPUT ;
    USE SIGNAL ;
    PORT
      LAYER M3 ;
        RECT  81.684 30.096 81.702 30.24 ;
    END
  END xa[245]
  PIN xa[246]
    DIRECTION OUTPUT ;
    USE SIGNAL ;
    PORT
      LAYER M5 ;
        RECT  81.936 30.048 81.96 30.24 ;
    END
  END xa[246]
  PIN xa[247]
    DIRECTION OUTPUT ;
    USE SIGNAL ;
    PORT
      LAYER M3 ;
        RECT  82.26 30.096 82.278 30.24 ;
    END
  END xa[247]
  PIN xa[248]
    DIRECTION OUTPUT ;
    USE SIGNAL ;
    PORT
      LAYER M5 ;
        RECT  82.512 30.048 82.536 30.24 ;
    END
  END xa[248]
  PIN xa[249]
    DIRECTION OUTPUT ;
    USE SIGNAL ;
    PORT
      LAYER M3 ;
        RECT  82.8 30.096 82.818 30.24 ;
    END
  END xa[249]
  PIN xa[24]
    DIRECTION OUTPUT ;
    USE SIGNAL ;
    PORT
      LAYER M5 ;
        RECT  18.48 30.048 18.504 30.24 ;
    END
  END xa[24]
  PIN xa[250]
    DIRECTION OUTPUT ;
    USE SIGNAL ;
    PORT
      LAYER M5 ;
        RECT  83.088 30.048 83.112 30.24 ;
    END
  END xa[250]
  PIN xa[251]
    DIRECTION OUTPUT ;
    USE SIGNAL ;
    PORT
      LAYER M3 ;
        RECT  83.376 30.096 83.394 30.24 ;
    END
  END xa[251]
  PIN xa[252]
    DIRECTION OUTPUT ;
    USE SIGNAL ;
    PORT
      LAYER M5 ;
        RECT  83.664 30.048 83.688 30.24 ;
    END
  END xa[252]
  PIN xa[253]
    DIRECTION OUTPUT ;
    USE SIGNAL ;
    PORT
      LAYER M3 ;
        RECT  83.952 30.096 83.97 30.24 ;
    END
  END xa[253]
  PIN xa[254]
    DIRECTION OUTPUT ;
    USE SIGNAL ;
    PORT
      LAYER M5 ;
        RECT  84.24 30.048 84.264 30.24 ;
    END
  END xa[254]
  PIN xa[255]
    DIRECTION OUTPUT ;
    USE SIGNAL ;
    PORT
      LAYER M3 ;
        RECT  84.528 30.096 84.546 30.24 ;
    END
  END xa[255]
  PIN xa[256]
    DIRECTION OUTPUT ;
    USE SIGNAL ;
    PORT
      LAYER M5 ;
        RECT  84.816 30.048 84.84 30.24 ;
    END
  END xa[256]
  PIN xa[257]
    DIRECTION OUTPUT ;
    USE SIGNAL ;
    PORT
      LAYER M3 ;
        RECT  85.104 30.096 85.122 30.24 ;
    END
  END xa[257]
  PIN xa[258]
    DIRECTION OUTPUT ;
    USE SIGNAL ;
    PORT
      LAYER M5 ;
        RECT  85.392 30.048 85.416 30.24 ;
    END
  END xa[258]
  PIN xa[259]
    DIRECTION OUTPUT ;
    USE SIGNAL ;
    PORT
      LAYER M3 ;
        RECT  85.68 30.096 85.698 30.24 ;
    END
  END xa[259]
  PIN xa[25]
    DIRECTION OUTPUT ;
    USE SIGNAL ;
    PORT
      LAYER M3 ;
        RECT  18.756 30.096 18.774 30.24 ;
    END
  END xa[25]
  PIN xa[260]
    DIRECTION OUTPUT ;
    USE SIGNAL ;
    PORT
      LAYER M5 ;
        RECT  85.968 30.048 85.992 30.24 ;
    END
  END xa[260]
  PIN xa[261]
    DIRECTION OUTPUT ;
    USE SIGNAL ;
    PORT
      LAYER M3 ;
        RECT  86.256 30.096 86.274 30.24 ;
    END
  END xa[261]
  PIN xa[262]
    DIRECTION OUTPUT ;
    USE SIGNAL ;
    PORT
      LAYER M5 ;
        RECT  86.544 30.048 86.568 30.24 ;
    END
  END xa[262]
  PIN xa[263]
    DIRECTION OUTPUT ;
    USE SIGNAL ;
    PORT
      LAYER M3 ;
        RECT  86.832 30.096 86.85 30.24 ;
    END
  END xa[263]
  PIN xa[264]
    DIRECTION OUTPUT ;
    USE SIGNAL ;
    PORT
      LAYER M5 ;
        RECT  87.12 30.048 87.144 30.24 ;
    END
  END xa[264]
  PIN xa[265]
    DIRECTION OUTPUT ;
    USE SIGNAL ;
    PORT
      LAYER M3 ;
        RECT  87.408 30.096 87.426 30.24 ;
    END
  END xa[265]
  PIN xa[266]
    DIRECTION OUTPUT ;
    USE SIGNAL ;
    PORT
      LAYER M5 ;
        RECT  87.696 30.048 87.72 30.24 ;
    END
  END xa[266]
  PIN xa[267]
    DIRECTION OUTPUT ;
    USE SIGNAL ;
    PORT
      LAYER M3 ;
        RECT  87.948 30.096 87.966 30.24 ;
    END
  END xa[267]
  PIN xa[268]
    DIRECTION OUTPUT ;
    USE SIGNAL ;
    PORT
      LAYER M5 ;
        RECT  88.224 30.048 88.248 30.24 ;
    END
  END xa[268]
  PIN xa[269]
    DIRECTION OUTPUT ;
    USE SIGNAL ;
    PORT
      LAYER M3 ;
        RECT  88.524 30.096 88.542 30.24 ;
    END
  END xa[269]
  PIN xa[26]
    DIRECTION OUTPUT ;
    USE SIGNAL ;
    PORT
      LAYER M5 ;
        RECT  19.056 30.048 19.08 30.24 ;
    END
  END xa[26]
  PIN xa[270]
    DIRECTION OUTPUT ;
    USE SIGNAL ;
    PORT
      LAYER M5 ;
        RECT  88.8 30.048 88.824 30.24 ;
    END
  END xa[270]
  PIN xa[271]
    DIRECTION OUTPUT ;
    USE SIGNAL ;
    PORT
      LAYER M3 ;
        RECT  89.1 30.096 89.118 30.24 ;
    END
  END xa[271]
  PIN xa[272]
    DIRECTION OUTPUT ;
    USE SIGNAL ;
    PORT
      LAYER M5 ;
        RECT  89.376 30.048 89.4 30.24 ;
    END
  END xa[272]
  PIN xa[273]
    DIRECTION OUTPUT ;
    USE SIGNAL ;
    PORT
      LAYER M3 ;
        RECT  89.676 30.096 89.694 30.24 ;
    END
  END xa[273]
  PIN xa[274]
    DIRECTION OUTPUT ;
    USE SIGNAL ;
    PORT
      LAYER M5 ;
        RECT  89.952 30.048 89.976 30.24 ;
    END
  END xa[274]
  PIN xa[275]
    DIRECTION OUTPUT ;
    USE SIGNAL ;
    PORT
      LAYER M3 ;
        RECT  90.252 30.096 90.27 30.24 ;
    END
  END xa[275]
  PIN xa[276]
    DIRECTION OUTPUT ;
    USE SIGNAL ;
    PORT
      LAYER M5 ;
        RECT  90.528 30.048 90.552 30.24 ;
    END
  END xa[276]
  PIN xa[277]
    DIRECTION OUTPUT ;
    USE SIGNAL ;
    PORT
      LAYER M3 ;
        RECT  90.828 30.096 90.846 30.24 ;
    END
  END xa[277]
  PIN xa[278]
    DIRECTION OUTPUT ;
    USE SIGNAL ;
    PORT
      LAYER M5 ;
        RECT  91.104 30.048 91.128 30.24 ;
    END
  END xa[278]
  PIN xa[279]
    DIRECTION OUTPUT ;
    USE SIGNAL ;
    PORT
      LAYER M3 ;
        RECT  91.404 30.096 91.422 30.24 ;
    END
  END xa[279]
  PIN xa[27]
    DIRECTION OUTPUT ;
    USE SIGNAL ;
    PORT
      LAYER M3 ;
        RECT  19.332 30.096 19.35 30.24 ;
    END
  END xa[27]
  PIN xa[280]
    DIRECTION OUTPUT ;
    USE SIGNAL ;
    PORT
      LAYER M5 ;
        RECT  91.68 30.048 91.704 30.24 ;
    END
  END xa[280]
  PIN xa[281]
    DIRECTION OUTPUT ;
    USE SIGNAL ;
    PORT
      LAYER M3 ;
        RECT  91.98 30.096 91.998 30.24 ;
    END
  END xa[281]
  PIN xa[282]
    DIRECTION OUTPUT ;
    USE SIGNAL ;
    PORT
      LAYER M5 ;
        RECT  92.256 30.048 92.28 30.24 ;
    END
  END xa[282]
  PIN xa[28]
    DIRECTION OUTPUT ;
    USE SIGNAL ;
    PORT
      LAYER M5 ;
        RECT  19.632 30.048 19.656 30.24 ;
    END
  END xa[28]
  PIN xa[29]
    DIRECTION OUTPUT ;
    USE SIGNAL ;
    PORT
      LAYER M3 ;
        RECT  19.908 30.096 19.926 30.24 ;
    END
  END xa[29]
  PIN xa[2]
    DIRECTION OUTPUT ;
    USE SIGNAL ;
    PORT
      LAYER M5 ;
        RECT  12.192 30.048 12.216 30.24 ;
    END
  END xa[2]
  PIN xa[30]
    DIRECTION OUTPUT ;
    USE SIGNAL ;
    PORT
      LAYER M5 ;
        RECT  20.16 30.048 20.184 30.24 ;
    END
  END xa[30]
  PIN xa[31]
    DIRECTION OUTPUT ;
    USE SIGNAL ;
    PORT
      LAYER M3 ;
        RECT  20.484 30.096 20.502 30.24 ;
    END
  END xa[31]
  PIN xa[32]
    DIRECTION OUTPUT ;
    USE SIGNAL ;
    PORT
      LAYER M5 ;
        RECT  20.736 30.048 20.76 30.24 ;
    END
  END xa[32]
  PIN xa[33]
    DIRECTION OUTPUT ;
    USE SIGNAL ;
    PORT
      LAYER M3 ;
        RECT  21.024 30.096 21.042 30.24 ;
    END
  END xa[33]
  PIN xa[34]
    DIRECTION OUTPUT ;
    USE SIGNAL ;
    PORT
      LAYER M5 ;
        RECT  21.312 30.048 21.336 30.24 ;
    END
  END xa[34]
  PIN xa[35]
    DIRECTION OUTPUT ;
    USE SIGNAL ;
    PORT
      LAYER M3 ;
        RECT  21.6 30.096 21.618 30.24 ;
    END
  END xa[35]
  PIN xa[36]
    DIRECTION OUTPUT ;
    USE SIGNAL ;
    PORT
      LAYER M5 ;
        RECT  21.888 30.048 21.912 30.24 ;
    END
  END xa[36]
  PIN xa[37]
    DIRECTION OUTPUT ;
    USE SIGNAL ;
    PORT
      LAYER M3 ;
        RECT  22.176 30.096 22.194 30.24 ;
    END
  END xa[37]
  PIN xa[38]
    DIRECTION OUTPUT ;
    USE SIGNAL ;
    PORT
      LAYER M5 ;
        RECT  22.464 30.048 22.488 30.24 ;
    END
  END xa[38]
  PIN xa[39]
    DIRECTION OUTPUT ;
    USE SIGNAL ;
    PORT
      LAYER M3 ;
        RECT  22.752 30.096 22.77 30.24 ;
    END
  END xa[39]
  PIN xa[3]
    DIRECTION OUTPUT ;
    USE SIGNAL ;
    PORT
      LAYER M3 ;
        RECT  12.456 30.096 12.474 30.24 ;
    END
  END xa[3]
  PIN xa[40]
    DIRECTION OUTPUT ;
    USE SIGNAL ;
    PORT
      LAYER M5 ;
        RECT  23.04 30.048 23.064 30.24 ;
    END
  END xa[40]
  PIN xa[41]
    DIRECTION OUTPUT ;
    USE SIGNAL ;
    PORT
      LAYER M3 ;
        RECT  23.328 30.096 23.346 30.24 ;
    END
  END xa[41]
  PIN xa[42]
    DIRECTION OUTPUT ;
    USE SIGNAL ;
    PORT
      LAYER M5 ;
        RECT  23.616 30.048 23.64 30.24 ;
    END
  END xa[42]
  PIN xa[43]
    DIRECTION OUTPUT ;
    USE SIGNAL ;
    PORT
      LAYER M3 ;
        RECT  23.904 30.096 23.922 30.24 ;
    END
  END xa[43]
  PIN xa[44]
    DIRECTION OUTPUT ;
    USE SIGNAL ;
    PORT
      LAYER M5 ;
        RECT  24.192 30.048 24.216 30.24 ;
    END
  END xa[44]
  PIN xa[45]
    DIRECTION OUTPUT ;
    USE SIGNAL ;
    PORT
      LAYER M3 ;
        RECT  24.48 30.096 24.498 30.24 ;
    END
  END xa[45]
  PIN xa[46]
    DIRECTION OUTPUT ;
    USE SIGNAL ;
    PORT
      LAYER M5 ;
        RECT  24.768 30.048 24.792 30.24 ;
    END
  END xa[46]
  PIN xa[47]
    DIRECTION OUTPUT ;
    USE SIGNAL ;
    PORT
      LAYER M3 ;
        RECT  25.056 30.096 25.074 30.24 ;
    END
  END xa[47]
  PIN xa[48]
    DIRECTION OUTPUT ;
    USE SIGNAL ;
    PORT
      LAYER M5 ;
        RECT  25.344 30.048 25.368 30.24 ;
    END
  END xa[48]
  PIN xa[49]
    DIRECTION OUTPUT ;
    USE SIGNAL ;
    PORT
      LAYER M3 ;
        RECT  25.632 30.096 25.65 30.24 ;
    END
  END xa[49]
  PIN xa[4]
    DIRECTION OUTPUT ;
    USE SIGNAL ;
    PORT
      LAYER M5 ;
        RECT  12.768 30.048 12.792 30.24 ;
    END
  END xa[4]
  PIN xa[50]
    DIRECTION OUTPUT ;
    USE SIGNAL ;
    PORT
      LAYER M5 ;
        RECT  25.92 30.048 25.944 30.24 ;
    END
  END xa[50]
  PIN xa[51]
    DIRECTION OUTPUT ;
    USE SIGNAL ;
    PORT
      LAYER M3 ;
        RECT  26.172 30.096 26.19 30.24 ;
    END
  END xa[51]
  PIN xa[52]
    DIRECTION OUTPUT ;
    USE SIGNAL ;
    PORT
      LAYER M5 ;
        RECT  26.496 30.048 26.52 30.24 ;
    END
  END xa[52]
  PIN xa[53]
    DIRECTION OUTPUT ;
    USE SIGNAL ;
    PORT
      LAYER M3 ;
        RECT  26.748 30.096 26.766 30.24 ;
    END
  END xa[53]
  PIN xa[54]
    DIRECTION OUTPUT ;
    USE SIGNAL ;
    PORT
      LAYER M5 ;
        RECT  27.024 30.048 27.048 30.24 ;
    END
  END xa[54]
  PIN xa[55]
    DIRECTION OUTPUT ;
    USE SIGNAL ;
    PORT
      LAYER M3 ;
        RECT  27.324 30.096 27.342 30.24 ;
    END
  END xa[55]
  PIN xa[56]
    DIRECTION OUTPUT ;
    USE SIGNAL ;
    PORT
      LAYER M5 ;
        RECT  27.6 30.048 27.624 30.24 ;
    END
  END xa[56]
  PIN xa[57]
    DIRECTION OUTPUT ;
    USE SIGNAL ;
    PORT
      LAYER M3 ;
        RECT  27.9 30.096 27.918 30.24 ;
    END
  END xa[57]
  PIN xa[58]
    DIRECTION OUTPUT ;
    USE SIGNAL ;
    PORT
      LAYER M5 ;
        RECT  28.176 30.048 28.2 30.24 ;
    END
  END xa[58]
  PIN xa[59]
    DIRECTION OUTPUT ;
    USE SIGNAL ;
    PORT
      LAYER M3 ;
        RECT  28.476 30.096 28.494 30.24 ;
    END
  END xa[59]
  PIN xa[5]
    DIRECTION OUTPUT ;
    USE SIGNAL ;
    PORT
      LAYER M3 ;
        RECT  13.032 30.096 13.05 30.24 ;
    END
  END xa[5]
  PIN xa[60]
    DIRECTION OUTPUT ;
    USE SIGNAL ;
    PORT
      LAYER M5 ;
        RECT  28.752 30.048 28.776 30.24 ;
    END
  END xa[60]
  PIN xa[61]
    DIRECTION OUTPUT ;
    USE SIGNAL ;
    PORT
      LAYER M3 ;
        RECT  29.052 30.096 29.07 30.24 ;
    END
  END xa[61]
  PIN xa[62]
    DIRECTION OUTPUT ;
    USE SIGNAL ;
    PORT
      LAYER M5 ;
        RECT  29.328 30.048 29.352 30.24 ;
    END
  END xa[62]
  PIN xa[63]
    DIRECTION OUTPUT ;
    USE SIGNAL ;
    PORT
      LAYER M3 ;
        RECT  29.628 30.096 29.646 30.24 ;
    END
  END xa[63]
  PIN xa[64]
    DIRECTION OUTPUT ;
    USE SIGNAL ;
    PORT
      LAYER M5 ;
        RECT  29.904 30.048 29.928 30.24 ;
    END
  END xa[64]
  PIN xa[65]
    DIRECTION OUTPUT ;
    USE SIGNAL ;
    PORT
      LAYER M3 ;
        RECT  30.204 30.096 30.222 30.24 ;
    END
  END xa[65]
  PIN xa[66]
    DIRECTION OUTPUT ;
    USE SIGNAL ;
    PORT
      LAYER M5 ;
        RECT  30.48 30.048 30.504 30.24 ;
    END
  END xa[66]
  PIN xa[67]
    DIRECTION OUTPUT ;
    USE SIGNAL ;
    PORT
      LAYER M3 ;
        RECT  30.78 30.096 30.798 30.24 ;
    END
  END xa[67]
  PIN xa[68]
    DIRECTION OUTPUT ;
    USE SIGNAL ;
    PORT
      LAYER M5 ;
        RECT  31.056 30.048 31.08 30.24 ;
    END
  END xa[68]
  PIN xa[69]
    DIRECTION OUTPUT ;
    USE SIGNAL ;
    PORT
      LAYER M3 ;
        RECT  31.32 30.096 31.338 30.24 ;
    END
  END xa[69]
  PIN xa[6]
    DIRECTION OUTPUT ;
    USE SIGNAL ;
    PORT
      LAYER M5 ;
        RECT  13.296 30.048 13.32 30.24 ;
    END
  END xa[6]
  PIN xa[70]
    DIRECTION OUTPUT ;
    USE SIGNAL ;
    PORT
      LAYER M5 ;
        RECT  31.632 30.048 31.656 30.24 ;
    END
  END xa[70]
  PIN xa[71]
    DIRECTION OUTPUT ;
    USE SIGNAL ;
    PORT
      LAYER M3 ;
        RECT  31.896 30.096 31.914 30.24 ;
    END
  END xa[71]
  PIN xa[72]
    DIRECTION OUTPUT ;
    USE SIGNAL ;
    PORT
      LAYER M5 ;
        RECT  32.208 30.048 32.232 30.24 ;
    END
  END xa[72]
  PIN xa[73]
    DIRECTION OUTPUT ;
    USE SIGNAL ;
    PORT
      LAYER M3 ;
        RECT  32.472 30.096 32.49 30.24 ;
    END
  END xa[73]
  PIN xa[74]
    DIRECTION OUTPUT ;
    USE SIGNAL ;
    PORT
      LAYER M5 ;
        RECT  32.784 30.048 32.808 30.24 ;
    END
  END xa[74]
  PIN xa[75]
    DIRECTION OUTPUT ;
    USE SIGNAL ;
    PORT
      LAYER M3 ;
        RECT  33.048 30.096 33.066 30.24 ;
    END
  END xa[75]
  PIN xa[76]
    DIRECTION OUTPUT ;
    USE SIGNAL ;
    PORT
      LAYER M5 ;
        RECT  33.36 30.048 33.384 30.24 ;
    END
  END xa[76]
  PIN xa[77]
    DIRECTION OUTPUT ;
    USE SIGNAL ;
    PORT
      LAYER M3 ;
        RECT  33.624 30.096 33.642 30.24 ;
    END
  END xa[77]
  PIN xa[78]
    DIRECTION OUTPUT ;
    USE SIGNAL ;
    PORT
      LAYER M5 ;
        RECT  33.888 30.048 33.912 30.24 ;
    END
  END xa[78]
  PIN xa[79]
    DIRECTION OUTPUT ;
    USE SIGNAL ;
    PORT
      LAYER M3 ;
        RECT  34.2 30.096 34.218 30.24 ;
    END
  END xa[79]
  PIN xa[7]
    DIRECTION OUTPUT ;
    USE SIGNAL ;
    PORT
      LAYER M3 ;
        RECT  13.608 30.096 13.626 30.24 ;
    END
  END xa[7]
  PIN xa[80]
    DIRECTION OUTPUT ;
    USE SIGNAL ;
    PORT
      LAYER M5 ;
        RECT  34.464 30.048 34.488 30.24 ;
    END
  END xa[80]
  PIN xa[81]
    DIRECTION OUTPUT ;
    USE SIGNAL ;
    PORT
      LAYER M3 ;
        RECT  34.776 30.096 34.794 30.24 ;
    END
  END xa[81]
  PIN xa[82]
    DIRECTION OUTPUT ;
    USE SIGNAL ;
    PORT
      LAYER M5 ;
        RECT  35.04 30.048 35.064 30.24 ;
    END
  END xa[82]
  PIN xa[83]
    DIRECTION OUTPUT ;
    USE SIGNAL ;
    PORT
      LAYER M3 ;
        RECT  35.352 30.096 35.37 30.24 ;
    END
  END xa[83]
  PIN xa[84]
    DIRECTION OUTPUT ;
    USE SIGNAL ;
    PORT
      LAYER M5 ;
        RECT  35.616 30.048 35.64 30.24 ;
    END
  END xa[84]
  PIN xa[85]
    DIRECTION OUTPUT ;
    USE SIGNAL ;
    PORT
      LAYER M3 ;
        RECT  35.928 30.096 35.946 30.24 ;
    END
  END xa[85]
  PIN xa[86]
    DIRECTION OUTPUT ;
    USE SIGNAL ;
    PORT
      LAYER M5 ;
        RECT  36.192 30.048 36.216 30.24 ;
    END
  END xa[86]
  PIN xa[87]
    DIRECTION OUTPUT ;
    USE SIGNAL ;
    PORT
      LAYER M3 ;
        RECT  36.468 30.096 36.486 30.24 ;
    END
  END xa[87]
  PIN xa[88]
    DIRECTION OUTPUT ;
    USE SIGNAL ;
    PORT
      LAYER M5 ;
        RECT  36.768 30.048 36.792 30.24 ;
    END
  END xa[88]
  PIN xa[89]
    DIRECTION OUTPUT ;
    USE SIGNAL ;
    PORT
      LAYER M3 ;
        RECT  37.044 30.096 37.062 30.24 ;
    END
  END xa[89]
  PIN xa[8]
    DIRECTION OUTPUT ;
    USE SIGNAL ;
    PORT
      LAYER M5 ;
        RECT  13.872 30.048 13.896 30.24 ;
    END
  END xa[8]
  PIN xa[90]
    DIRECTION OUTPUT ;
    USE SIGNAL ;
    PORT
      LAYER M5 ;
        RECT  37.344 30.048 37.368 30.24 ;
    END
  END xa[90]
  PIN xa[91]
    DIRECTION OUTPUT ;
    USE SIGNAL ;
    PORT
      LAYER M3 ;
        RECT  37.62 30.096 37.638 30.24 ;
    END
  END xa[91]
  PIN xa[92]
    DIRECTION OUTPUT ;
    USE SIGNAL ;
    PORT
      LAYER M5 ;
        RECT  37.92 30.048 37.944 30.24 ;
    END
  END xa[92]
  PIN xa[93]
    DIRECTION OUTPUT ;
    USE SIGNAL ;
    PORT
      LAYER M3 ;
        RECT  38.196 30.096 38.214 30.24 ;
    END
  END xa[93]
  PIN xa[94]
    DIRECTION OUTPUT ;
    USE SIGNAL ;
    PORT
      LAYER M5 ;
        RECT  38.496 30.048 38.52 30.24 ;
    END
  END xa[94]
  PIN xa[95]
    DIRECTION OUTPUT ;
    USE SIGNAL ;
    PORT
      LAYER M3 ;
        RECT  38.772 30.096 38.79 30.24 ;
    END
  END xa[95]
  PIN xa[96]
    DIRECTION OUTPUT ;
    USE SIGNAL ;
    PORT
      LAYER M5 ;
        RECT  39.072 30.048 39.096 30.24 ;
    END
  END xa[96]
  PIN xa[97]
    DIRECTION OUTPUT ;
    USE SIGNAL ;
    PORT
      LAYER M3 ;
        RECT  39.348 30.096 39.366 30.24 ;
    END
  END xa[97]
  PIN xa[98]
    DIRECTION OUTPUT ;
    USE SIGNAL ;
    PORT
      LAYER M5 ;
        RECT  39.648 30.048 39.672 30.24 ;
    END
  END xa[98]
  PIN xa[99]
    DIRECTION OUTPUT ;
    USE SIGNAL ;
    PORT
      LAYER M3 ;
        RECT  39.924 30.096 39.942 30.24 ;
    END
  END xa[99]
  PIN xa[9]
    DIRECTION OUTPUT ;
    USE SIGNAL ;
    PORT
      LAYER M3 ;
        RECT  14.184 30.096 14.202 30.24 ;
    END
  END xa[9]
  PIN xai[0]
    DIRECTION INPUT ;
    USE SIGNAL ;
    PORT
      LAYER M5 ;
        RECT  9.36 0 9.384 0.192 ;
    END
  END xai[0]
  PIN xai[100]
    DIRECTION INPUT ;
    USE SIGNAL ;
    PORT
      LAYER M5 ;
        RECT  38.4 0 38.424 0.192 ;
    END
  END xai[100]
  PIN xai[101]
    DIRECTION INPUT ;
    USE SIGNAL ;
    PORT
      LAYER M3 ;
        RECT  38.664 0 38.682 0.144 ;
    END
  END xai[101]
  PIN xai[102]
    DIRECTION INPUT ;
    USE SIGNAL ;
    PORT
      LAYER M5 ;
        RECT  38.976 0 39 0.192 ;
    END
  END xai[102]
  PIN xai[103]
    DIRECTION INPUT ;
    USE SIGNAL ;
    PORT
      LAYER M3 ;
        RECT  39.276 0 39.294 0.144 ;
    END
  END xai[103]
  PIN xai[104]
    DIRECTION INPUT ;
    USE SIGNAL ;
    PORT
      LAYER M5 ;
        RECT  39.552 0 39.576 0.192 ;
    END
  END xai[104]
  PIN xai[105]
    DIRECTION INPUT ;
    USE SIGNAL ;
    PORT
      LAYER M3 ;
        RECT  39.852 0 39.87 0.144 ;
    END
  END xai[105]
  PIN xai[106]
    DIRECTION INPUT ;
    USE SIGNAL ;
    PORT
      LAYER M5 ;
        RECT  40.128 0 40.152 0.192 ;
    END
  END xai[106]
  PIN xai[107]
    DIRECTION INPUT ;
    USE SIGNAL ;
    PORT
      LAYER M3 ;
        RECT  40.428 0 40.446 0.144 ;
    END
  END xai[107]
  PIN xai[108]
    DIRECTION INPUT ;
    USE SIGNAL ;
    PORT
      LAYER M5 ;
        RECT  40.704 0 40.728 0.192 ;
    END
  END xai[108]
  PIN xai[109]
    DIRECTION INPUT ;
    USE SIGNAL ;
    PORT
      LAYER M3 ;
        RECT  41.004 0 41.022 0.144 ;
    END
  END xai[109]
  PIN xai[10]
    DIRECTION INPUT ;
    USE SIGNAL ;
    PORT
      LAYER M5 ;
        RECT  12.288 0 12.312 0.192 ;
    END
  END xai[10]
  PIN xai[110]
    DIRECTION INPUT ;
    USE SIGNAL ;
    PORT
      LAYER M5 ;
        RECT  41.28 0 41.304 0.192 ;
    END
  END xai[110]
  PIN xai[111]
    DIRECTION INPUT ;
    USE SIGNAL ;
    PORT
      LAYER M3 ;
        RECT  41.58 0 41.598 0.144 ;
    END
  END xai[111]
  PIN xai[112]
    DIRECTION INPUT ;
    USE SIGNAL ;
    PORT
      LAYER M5 ;
        RECT  41.856 0 41.88 0.192 ;
    END
  END xai[112]
  PIN xai[113]
    DIRECTION INPUT ;
    USE SIGNAL ;
    PORT
      LAYER M3 ;
        RECT  42.156 0 42.174 0.144 ;
    END
  END xai[113]
  PIN xai[114]
    DIRECTION INPUT ;
    USE SIGNAL ;
    PORT
      LAYER M5 ;
        RECT  42.432 0 42.456 0.192 ;
    END
  END xai[114]
  PIN xai[115]
    DIRECTION INPUT ;
    USE SIGNAL ;
    PORT
      LAYER M3 ;
        RECT  42.732 0 42.75 0.144 ;
    END
  END xai[115]
  PIN xai[116]
    DIRECTION INPUT ;
    USE SIGNAL ;
    PORT
      LAYER M5 ;
        RECT  43.008 0 43.032 0.192 ;
    END
  END xai[116]
  PIN xai[117]
    DIRECTION INPUT ;
    USE SIGNAL ;
    PORT
      LAYER M3 ;
        RECT  43.308 0 43.326 0.144 ;
    END
  END xai[117]
  PIN xai[118]
    DIRECTION INPUT ;
    USE SIGNAL ;
    PORT
      LAYER M5 ;
        RECT  43.584 0 43.608 0.192 ;
    END
  END xai[118]
  PIN xai[119]
    DIRECTION INPUT ;
    USE SIGNAL ;
    PORT
      LAYER M3 ;
        RECT  43.884 0 43.902 0.144 ;
    END
  END xai[119]
  PIN xai[11]
    DIRECTION INPUT ;
    USE SIGNAL ;
    PORT
      LAYER M3 ;
        RECT  12.564 0 12.582 0.144 ;
    END
  END xai[11]
  PIN xai[120]
    DIRECTION INPUT ;
    USE SIGNAL ;
    PORT
      LAYER M5 ;
        RECT  44.208 0 44.232 0.192 ;
    END
  END xai[120]
  PIN xai[121]
    DIRECTION INPUT ;
    USE SIGNAL ;
    PORT
      LAYER M3 ;
        RECT  44.496 0 44.514 0.144 ;
    END
  END xai[121]
  PIN xai[122]
    DIRECTION INPUT ;
    USE SIGNAL ;
    PORT
      LAYER M5 ;
        RECT  44.784 0 44.808 0.192 ;
    END
  END xai[122]
  PIN xai[123]
    DIRECTION INPUT ;
    USE SIGNAL ;
    PORT
      LAYER M3 ;
        RECT  45.072 0 45.09 0.144 ;
    END
  END xai[123]
  PIN xai[124]
    DIRECTION INPUT ;
    USE SIGNAL ;
    PORT
      LAYER M5 ;
        RECT  45.36 0 45.384 0.192 ;
    END
  END xai[124]
  PIN xai[125]
    DIRECTION INPUT ;
    USE SIGNAL ;
    PORT
      LAYER M3 ;
        RECT  45.648 0 45.666 0.144 ;
    END
  END xai[125]
  PIN xai[126]
    DIRECTION INPUT ;
    USE SIGNAL ;
    PORT
      LAYER M5 ;
        RECT  45.936 0 45.96 0.192 ;
    END
  END xai[126]
  PIN xai[127]
    DIRECTION INPUT ;
    USE SIGNAL ;
    PORT
      LAYER M3 ;
        RECT  46.224 0 46.242 0.144 ;
    END
  END xai[127]
  PIN xai[128]
    DIRECTION INPUT ;
    USE SIGNAL ;
    PORT
      LAYER M5 ;
        RECT  46.512 0 46.536 0.192 ;
    END
  END xai[128]
  PIN xai[129]
    DIRECTION INPUT ;
    USE SIGNAL ;
    PORT
      LAYER M3 ;
        RECT  46.8 0 46.818 0.144 ;
    END
  END xai[129]
  PIN xai[12]
    DIRECTION INPUT ;
    USE SIGNAL ;
    PORT
      LAYER M5 ;
        RECT  12.864 0 12.888 0.192 ;
    END
  END xai[12]
  PIN xai[130]
    DIRECTION INPUT ;
    USE SIGNAL ;
    PORT
      LAYER M5 ;
        RECT  47.088 0 47.112 0.192 ;
    END
  END xai[130]
  PIN xai[131]
    DIRECTION INPUT ;
    USE SIGNAL ;
    PORT
      LAYER M3 ;
        RECT  47.376 0 47.394 0.144 ;
    END
  END xai[131]
  PIN xai[132]
    DIRECTION INPUT ;
    USE SIGNAL ;
    PORT
      LAYER M5 ;
        RECT  47.664 0 47.688 0.192 ;
    END
  END xai[132]
  PIN xai[133]
    DIRECTION INPUT ;
    USE SIGNAL ;
    PORT
      LAYER M3 ;
        RECT  47.952 0 47.97 0.144 ;
    END
  END xai[133]
  PIN xai[134]
    DIRECTION INPUT ;
    USE SIGNAL ;
    PORT
      LAYER M5 ;
        RECT  48.24 0 48.264 0.192 ;
    END
  END xai[134]
  PIN xai[135]
    DIRECTION INPUT ;
    USE SIGNAL ;
    PORT
      LAYER M3 ;
        RECT  48.528 0 48.546 0.144 ;
    END
  END xai[135]
  PIN xai[136]
    DIRECTION INPUT ;
    USE SIGNAL ;
    PORT
      LAYER M5 ;
        RECT  48.816 0 48.84 0.192 ;
    END
  END xai[136]
  PIN xai[137]
    DIRECTION INPUT ;
    USE SIGNAL ;
    PORT
      LAYER M3 ;
        RECT  49.104 0 49.122 0.144 ;
    END
  END xai[137]
  PIN xai[138]
    DIRECTION INPUT ;
    USE SIGNAL ;
    PORT
      LAYER M5 ;
        RECT  49.392 0 49.416 0.192 ;
    END
  END xai[138]
  PIN xai[139]
    DIRECTION INPUT ;
    USE SIGNAL ;
    PORT
      LAYER M3 ;
        RECT  49.716 0 49.734 0.144 ;
    END
  END xai[139]
  PIN xai[13]
    DIRECTION INPUT ;
    USE SIGNAL ;
    PORT
      LAYER M3 ;
        RECT  13.14 0 13.158 0.144 ;
    END
  END xai[13]
  PIN xai[140]
    DIRECTION INPUT ;
    USE SIGNAL ;
    PORT
      LAYER M5 ;
        RECT  49.968 0 49.992 0.192 ;
    END
  END xai[140]
  PIN xai[141]
    DIRECTION INPUT ;
    USE SIGNAL ;
    PORT
      LAYER M3 ;
        RECT  50.292 0 50.31 0.144 ;
    END
  END xai[141]
  PIN xai[142]
    DIRECTION INPUT ;
    USE SIGNAL ;
    PORT
      LAYER M5 ;
        RECT  50.592 0 50.616 0.192 ;
    END
  END xai[142]
  PIN xai[143]
    DIRECTION INPUT ;
    USE SIGNAL ;
    PORT
      LAYER M3 ;
        RECT  50.868 0 50.886 0.144 ;
    END
  END xai[143]
  PIN xai[144]
    DIRECTION INPUT ;
    USE SIGNAL ;
    PORT
      LAYER M5 ;
        RECT  51.168 0 51.192 0.192 ;
    END
  END xai[144]
  PIN xai[145]
    DIRECTION INPUT ;
    USE SIGNAL ;
    PORT
      LAYER M3 ;
        RECT  51.444 0 51.462 0.144 ;
    END
  END xai[145]
  PIN xai[146]
    DIRECTION INPUT ;
    USE SIGNAL ;
    PORT
      LAYER M5 ;
        RECT  51.744 0 51.768 0.192 ;
    END
  END xai[146]
  PIN xai[147]
    DIRECTION INPUT ;
    USE SIGNAL ;
    PORT
      LAYER M3 ;
        RECT  52.02 0 52.038 0.144 ;
    END
  END xai[147]
  PIN xai[148]
    DIRECTION INPUT ;
    USE SIGNAL ;
    PORT
      LAYER M5 ;
        RECT  52.32 0 52.344 0.192 ;
    END
  END xai[148]
  PIN xai[149]
    DIRECTION INPUT ;
    USE SIGNAL ;
    PORT
      LAYER M3 ;
        RECT  52.596 0 52.614 0.144 ;
    END
  END xai[149]
  PIN xai[14]
    DIRECTION INPUT ;
    USE SIGNAL ;
    PORT
      LAYER M5 ;
        RECT  13.44 0 13.464 0.192 ;
    END
  END xai[14]
  PIN xai[150]
    DIRECTION INPUT ;
    USE SIGNAL ;
    PORT
      LAYER M5 ;
        RECT  52.896 0 52.92 0.192 ;
    END
  END xai[150]
  PIN xai[151]
    DIRECTION INPUT ;
    USE SIGNAL ;
    PORT
      LAYER M3 ;
        RECT  53.172 0 53.19 0.144 ;
    END
  END xai[151]
  PIN xai[152]
    DIRECTION INPUT ;
    USE SIGNAL ;
    PORT
      LAYER M5 ;
        RECT  53.472 0 53.496 0.192 ;
    END
  END xai[152]
  PIN xai[153]
    DIRECTION INPUT ;
    USE SIGNAL ;
    PORT
      LAYER M3 ;
        RECT  53.748 0 53.766 0.144 ;
    END
  END xai[153]
  PIN xai[154]
    DIRECTION INPUT ;
    USE SIGNAL ;
    PORT
      LAYER M5 ;
        RECT  54.048 0 54.072 0.192 ;
    END
  END xai[154]
  PIN xai[155]
    DIRECTION INPUT ;
    USE SIGNAL ;
    PORT
      LAYER M3 ;
        RECT  54.36 0 54.378 0.144 ;
    END
  END xai[155]
  PIN xai[156]
    DIRECTION INPUT ;
    USE SIGNAL ;
    PORT
      LAYER M5 ;
        RECT  54.624 0 54.648 0.192 ;
    END
  END xai[156]
  PIN xai[157]
    DIRECTION INPUT ;
    USE SIGNAL ;
    PORT
      LAYER M3 ;
        RECT  54.936 0 54.954 0.144 ;
    END
  END xai[157]
  PIN xai[158]
    DIRECTION INPUT ;
    USE SIGNAL ;
    PORT
      LAYER M5 ;
        RECT  55.2 0 55.224 0.192 ;
    END
  END xai[158]
  PIN xai[159]
    DIRECTION INPUT ;
    USE SIGNAL ;
    PORT
      LAYER M3 ;
        RECT  55.512 0 55.53 0.144 ;
    END
  END xai[159]
  PIN xai[15]
    DIRECTION INPUT ;
    USE SIGNAL ;
    PORT
      LAYER M3 ;
        RECT  13.752 0 13.77 0.144 ;
    END
  END xai[15]
  PIN xai[160]
    DIRECTION INPUT ;
    USE SIGNAL ;
    PORT
      LAYER M5 ;
        RECT  55.776 0 55.8 0.192 ;
    END
  END xai[160]
  PIN xai[161]
    DIRECTION INPUT ;
    USE SIGNAL ;
    PORT
      LAYER M3 ;
        RECT  56.088 0 56.106 0.144 ;
    END
  END xai[161]
  PIN xai[162]
    DIRECTION INPUT ;
    USE SIGNAL ;
    PORT
      LAYER M5 ;
        RECT  56.352 0 56.376 0.192 ;
    END
  END xai[162]
  PIN xai[163]
    DIRECTION INPUT ;
    USE SIGNAL ;
    PORT
      LAYER M3 ;
        RECT  56.664 0 56.682 0.144 ;
    END
  END xai[163]
  PIN xai[164]
    DIRECTION INPUT ;
    USE SIGNAL ;
    PORT
      LAYER M5 ;
        RECT  56.928 0 56.952 0.192 ;
    END
  END xai[164]
  PIN xai[165]
    DIRECTION INPUT ;
    USE SIGNAL ;
    PORT
      LAYER M3 ;
        RECT  57.24 0 57.258 0.144 ;
    END
  END xai[165]
  PIN xai[166]
    DIRECTION INPUT ;
    USE SIGNAL ;
    PORT
      LAYER M5 ;
        RECT  57.552 0 57.576 0.192 ;
    END
  END xai[166]
  PIN xai[167]
    DIRECTION INPUT ;
    USE SIGNAL ;
    PORT
      LAYER M3 ;
        RECT  57.816 0 57.834 0.144 ;
    END
  END xai[167]
  PIN xai[168]
    DIRECTION INPUT ;
    USE SIGNAL ;
    PORT
      LAYER M5 ;
        RECT  58.128 0 58.152 0.192 ;
    END
  END xai[168]
  PIN xai[169]
    DIRECTION INPUT ;
    USE SIGNAL ;
    PORT
      LAYER M3 ;
        RECT  58.392 0 58.41 0.144 ;
    END
  END xai[169]
  PIN xai[16]
    DIRECTION INPUT ;
    USE SIGNAL ;
    PORT
      LAYER M5 ;
        RECT  14.016 0 14.04 0.192 ;
    END
  END xai[16]
  PIN xai[170]
    DIRECTION INPUT ;
    USE SIGNAL ;
    PORT
      LAYER M5 ;
        RECT  58.704 0 58.728 0.192 ;
    END
  END xai[170]
  PIN xai[171]
    DIRECTION INPUT ;
    USE SIGNAL ;
    PORT
      LAYER M3 ;
        RECT  58.968 0 58.986 0.144 ;
    END
  END xai[171]
  PIN xai[172]
    DIRECTION INPUT ;
    USE SIGNAL ;
    PORT
      LAYER M5 ;
        RECT  59.28 0 59.304 0.192 ;
    END
  END xai[172]
  PIN xai[173]
    DIRECTION INPUT ;
    USE SIGNAL ;
    PORT
      LAYER M3 ;
        RECT  59.58 0 59.598 0.144 ;
    END
  END xai[173]
  PIN xai[174]
    DIRECTION INPUT ;
    USE SIGNAL ;
    PORT
      LAYER M5 ;
        RECT  59.856 0 59.88 0.192 ;
    END
  END xai[174]
  PIN xai[175]
    DIRECTION INPUT ;
    USE SIGNAL ;
    PORT
      LAYER M3 ;
        RECT  60.156 0 60.174 0.144 ;
    END
  END xai[175]
  PIN xai[176]
    DIRECTION INPUT ;
    USE SIGNAL ;
    PORT
      LAYER M5 ;
        RECT  60.432 0 60.456 0.192 ;
    END
  END xai[176]
  PIN xai[177]
    DIRECTION INPUT ;
    USE SIGNAL ;
    PORT
      LAYER M3 ;
        RECT  60.732 0 60.75 0.144 ;
    END
  END xai[177]
  PIN xai[178]
    DIRECTION INPUT ;
    USE SIGNAL ;
    PORT
      LAYER M5 ;
        RECT  61.008 0 61.032 0.192 ;
    END
  END xai[178]
  PIN xai[179]
    DIRECTION INPUT ;
    USE SIGNAL ;
    PORT
      LAYER M3 ;
        RECT  61.308 0 61.326 0.144 ;
    END
  END xai[179]
  PIN xai[17]
    DIRECTION INPUT ;
    USE SIGNAL ;
    PORT
      LAYER M3 ;
        RECT  14.328 0 14.346 0.144 ;
    END
  END xai[17]
  PIN xai[180]
    DIRECTION INPUT ;
    USE SIGNAL ;
    PORT
      LAYER M5 ;
        RECT  61.584 0 61.608 0.192 ;
    END
  END xai[180]
  PIN xai[181]
    DIRECTION INPUT ;
    USE SIGNAL ;
    PORT
      LAYER M3 ;
        RECT  61.884 0 61.902 0.144 ;
    END
  END xai[181]
  PIN xai[182]
    DIRECTION INPUT ;
    USE SIGNAL ;
    PORT
      LAYER M5 ;
        RECT  62.16 0 62.184 0.192 ;
    END
  END xai[182]
  PIN xai[183]
    DIRECTION INPUT ;
    USE SIGNAL ;
    PORT
      LAYER M3 ;
        RECT  62.46 0 62.478 0.144 ;
    END
  END xai[183]
  PIN xai[184]
    DIRECTION INPUT ;
    USE SIGNAL ;
    PORT
      LAYER M5 ;
        RECT  62.736 0 62.76 0.192 ;
    END
  END xai[184]
  PIN xai[185]
    DIRECTION INPUT ;
    USE SIGNAL ;
    PORT
      LAYER M3 ;
        RECT  63.036 0 63.054 0.144 ;
    END
  END xai[185]
  PIN xai[186]
    DIRECTION INPUT ;
    USE SIGNAL ;
    PORT
      LAYER M5 ;
        RECT  63.312 0 63.336 0.192 ;
    END
  END xai[186]
  PIN xai[187]
    DIRECTION INPUT ;
    USE SIGNAL ;
    PORT
      LAYER M3 ;
        RECT  63.612 0 63.63 0.144 ;
    END
  END xai[187]
  PIN xai[188]
    DIRECTION INPUT ;
    USE SIGNAL ;
    PORT
      LAYER M5 ;
        RECT  63.888 0 63.912 0.192 ;
    END
  END xai[188]
  PIN xai[189]
    DIRECTION INPUT ;
    USE SIGNAL ;
    PORT
      LAYER M3 ;
        RECT  64.188 0 64.206 0.144 ;
    END
  END xai[189]
  PIN xai[18]
    DIRECTION INPUT ;
    USE SIGNAL ;
    PORT
      LAYER M5 ;
        RECT  14.592 0 14.616 0.192 ;
    END
  END xai[18]
  PIN xai[190]
    DIRECTION INPUT ;
    USE SIGNAL ;
    PORT
      LAYER M5 ;
        RECT  64.512 0 64.536 0.192 ;
    END
  END xai[190]
  PIN xai[191]
    DIRECTION INPUT ;
    USE SIGNAL ;
    PORT
      LAYER M3 ;
        RECT  64.8 0 64.818 0.144 ;
    END
  END xai[191]
  PIN xai[192]
    DIRECTION INPUT ;
    USE SIGNAL ;
    PORT
      LAYER M5 ;
        RECT  65.088 0 65.112 0.192 ;
    END
  END xai[192]
  PIN xai[193]
    DIRECTION INPUT ;
    USE SIGNAL ;
    PORT
      LAYER M3 ;
        RECT  65.376 0 65.394 0.144 ;
    END
  END xai[193]
  PIN xai[194]
    DIRECTION INPUT ;
    USE SIGNAL ;
    PORT
      LAYER M5 ;
        RECT  65.664 0 65.688 0.192 ;
    END
  END xai[194]
  PIN xai[195]
    DIRECTION INPUT ;
    USE SIGNAL ;
    PORT
      LAYER M3 ;
        RECT  65.952 0 65.97 0.144 ;
    END
  END xai[195]
  PIN xai[196]
    DIRECTION INPUT ;
    USE SIGNAL ;
    PORT
      LAYER M5 ;
        RECT  66.24 0 66.264 0.192 ;
    END
  END xai[196]
  PIN xai[197]
    DIRECTION INPUT ;
    USE SIGNAL ;
    PORT
      LAYER M3 ;
        RECT  66.528 0 66.546 0.144 ;
    END
  END xai[197]
  PIN xai[198]
    DIRECTION INPUT ;
    USE SIGNAL ;
    PORT
      LAYER M5 ;
        RECT  66.816 0 66.84 0.192 ;
    END
  END xai[198]
  PIN xai[199]
    DIRECTION INPUT ;
    USE SIGNAL ;
    PORT
      LAYER M3 ;
        RECT  67.104 0 67.122 0.144 ;
    END
  END xai[199]
  PIN xai[19]
    DIRECTION INPUT ;
    USE SIGNAL ;
    PORT
      LAYER M3 ;
        RECT  14.904 0 14.922 0.144 ;
    END
  END xai[19]
  PIN xai[1]
    DIRECTION INPUT ;
    USE SIGNAL ;
    PORT
      LAYER M3 ;
        RECT  9.684 0 9.702 0.144 ;
    END
  END xai[1]
  PIN xai[200]
    DIRECTION INPUT ;
    USE SIGNAL ;
    PORT
      LAYER M5 ;
        RECT  67.392 0 67.416 0.192 ;
    END
  END xai[200]
  PIN xai[201]
    DIRECTION INPUT ;
    USE SIGNAL ;
    PORT
      LAYER M3 ;
        RECT  67.68 0 67.698 0.144 ;
    END
  END xai[201]
  PIN xai[202]
    DIRECTION INPUT ;
    USE SIGNAL ;
    PORT
      LAYER M5 ;
        RECT  67.968 0 67.992 0.192 ;
    END
  END xai[202]
  PIN xai[203]
    DIRECTION INPUT ;
    USE SIGNAL ;
    PORT
      LAYER M3 ;
        RECT  68.256 0 68.274 0.144 ;
    END
  END xai[203]
  PIN xai[204]
    DIRECTION INPUT ;
    USE SIGNAL ;
    PORT
      LAYER M5 ;
        RECT  68.544 0 68.568 0.192 ;
    END
  END xai[204]
  PIN xai[205]
    DIRECTION INPUT ;
    USE SIGNAL ;
    PORT
      LAYER M3 ;
        RECT  68.832 0 68.85 0.144 ;
    END
  END xai[205]
  PIN xai[206]
    DIRECTION INPUT ;
    USE SIGNAL ;
    PORT
      LAYER M5 ;
        RECT  69.12 0 69.144 0.192 ;
    END
  END xai[206]
  PIN xai[207]
    DIRECTION INPUT ;
    USE SIGNAL ;
    PORT
      LAYER M3 ;
        RECT  69.408 0 69.426 0.144 ;
    END
  END xai[207]
  PIN xai[208]
    DIRECTION INPUT ;
    USE SIGNAL ;
    PORT
      LAYER M5 ;
        RECT  69.696 0 69.72 0.192 ;
    END
  END xai[208]
  PIN xai[209]
    DIRECTION INPUT ;
    USE SIGNAL ;
    PORT
      LAYER M3 ;
        RECT  70.02 0 70.038 0.144 ;
    END
  END xai[209]
  PIN xai[20]
    DIRECTION INPUT ;
    USE SIGNAL ;
    PORT
      LAYER M5 ;
        RECT  15.168 0 15.192 0.192 ;
    END
  END xai[20]
  PIN xai[210]
    DIRECTION INPUT ;
    USE SIGNAL ;
    PORT
      LAYER M5 ;
        RECT  70.272 0 70.296 0.192 ;
    END
  END xai[210]
  PIN xai[211]
    DIRECTION INPUT ;
    USE SIGNAL ;
    PORT
      LAYER M3 ;
        RECT  70.596 0 70.614 0.144 ;
    END
  END xai[211]
  PIN xai[212]
    DIRECTION INPUT ;
    USE SIGNAL ;
    PORT
      LAYER M5 ;
        RECT  70.848 0 70.872 0.192 ;
    END
  END xai[212]
  PIN xai[213]
    DIRECTION INPUT ;
    USE SIGNAL ;
    PORT
      LAYER M3 ;
        RECT  71.172 0 71.19 0.144 ;
    END
  END xai[213]
  PIN xai[214]
    DIRECTION INPUT ;
    USE SIGNAL ;
    PORT
      LAYER M5 ;
        RECT  71.472 0 71.496 0.192 ;
    END
  END xai[214]
  PIN xai[215]
    DIRECTION INPUT ;
    USE SIGNAL ;
    PORT
      LAYER M3 ;
        RECT  71.748 0 71.766 0.144 ;
    END
  END xai[215]
  PIN xai[216]
    DIRECTION INPUT ;
    USE SIGNAL ;
    PORT
      LAYER M5 ;
        RECT  72.048 0 72.072 0.192 ;
    END
  END xai[216]
  PIN xai[217]
    DIRECTION INPUT ;
    USE SIGNAL ;
    PORT
      LAYER M3 ;
        RECT  72.324 0 72.342 0.144 ;
    END
  END xai[217]
  PIN xai[218]
    DIRECTION INPUT ;
    USE SIGNAL ;
    PORT
      LAYER M5 ;
        RECT  72.624 0 72.648 0.192 ;
    END
  END xai[218]
  PIN xai[219]
    DIRECTION INPUT ;
    USE SIGNAL ;
    PORT
      LAYER M3 ;
        RECT  72.9 0 72.918 0.144 ;
    END
  END xai[219]
  PIN xai[21]
    DIRECTION INPUT ;
    USE SIGNAL ;
    PORT
      LAYER M3 ;
        RECT  15.48 0 15.498 0.144 ;
    END
  END xai[21]
  PIN xai[220]
    DIRECTION INPUT ;
    USE SIGNAL ;
    PORT
      LAYER M5 ;
        RECT  73.2 0 73.224 0.192 ;
    END
  END xai[220]
  PIN xai[221]
    DIRECTION INPUT ;
    USE SIGNAL ;
    PORT
      LAYER M3 ;
        RECT  73.476 0 73.494 0.144 ;
    END
  END xai[221]
  PIN xai[222]
    DIRECTION INPUT ;
    USE SIGNAL ;
    PORT
      LAYER M5 ;
        RECT  73.776 0 73.8 0.192 ;
    END
  END xai[222]
  PIN xai[223]
    DIRECTION INPUT ;
    USE SIGNAL ;
    PORT
      LAYER M3 ;
        RECT  74.052 0 74.07 0.144 ;
    END
  END xai[223]
  PIN xai[224]
    DIRECTION INPUT ;
    USE SIGNAL ;
    PORT
      LAYER M5 ;
        RECT  74.352 0 74.376 0.192 ;
    END
  END xai[224]
  PIN xai[225]
    DIRECTION INPUT ;
    USE SIGNAL ;
    PORT
      LAYER M3 ;
        RECT  74.628 0 74.646 0.144 ;
    END
  END xai[225]
  PIN xai[226]
    DIRECTION INPUT ;
    USE SIGNAL ;
    PORT
      LAYER M5 ;
        RECT  74.928 0 74.952 0.192 ;
    END
  END xai[226]
  PIN xai[227]
    DIRECTION INPUT ;
    USE SIGNAL ;
    PORT
      LAYER M3 ;
        RECT  75.24 0 75.258 0.144 ;
    END
  END xai[227]
  PIN xai[228]
    DIRECTION INPUT ;
    USE SIGNAL ;
    PORT
      LAYER M5 ;
        RECT  75.504 0 75.528 0.192 ;
    END
  END xai[228]
  PIN xai[229]
    DIRECTION INPUT ;
    USE SIGNAL ;
    PORT
      LAYER M3 ;
        RECT  75.816 0 75.834 0.144 ;
    END
  END xai[229]
  PIN xai[22]
    DIRECTION INPUT ;
    USE SIGNAL ;
    PORT
      LAYER M5 ;
        RECT  15.744 0 15.768 0.192 ;
    END
  END xai[22]
  PIN xai[230]
    DIRECTION INPUT ;
    USE SIGNAL ;
    PORT
      LAYER M5 ;
        RECT  76.08 0 76.104 0.192 ;
    END
  END xai[230]
  PIN xai[231]
    DIRECTION INPUT ;
    USE SIGNAL ;
    PORT
      LAYER M3 ;
        RECT  76.392 0 76.41 0.144 ;
    END
  END xai[231]
  PIN xai[232]
    DIRECTION INPUT ;
    USE SIGNAL ;
    PORT
      LAYER M5 ;
        RECT  76.656 0 76.68 0.192 ;
    END
  END xai[232]
  PIN xai[233]
    DIRECTION INPUT ;
    USE SIGNAL ;
    PORT
      LAYER M3 ;
        RECT  76.968 0 76.986 0.144 ;
    END
  END xai[233]
  PIN xai[234]
    DIRECTION INPUT ;
    USE SIGNAL ;
    PORT
      LAYER M5 ;
        RECT  77.232 0 77.256 0.192 ;
    END
  END xai[234]
  PIN xai[235]
    DIRECTION INPUT ;
    USE SIGNAL ;
    PORT
      LAYER M3 ;
        RECT  77.544 0 77.562 0.144 ;
    END
  END xai[235]
  PIN xai[236]
    DIRECTION INPUT ;
    USE SIGNAL ;
    PORT
      LAYER M5 ;
        RECT  77.808 0 77.832 0.192 ;
    END
  END xai[236]
  PIN xai[237]
    DIRECTION INPUT ;
    USE SIGNAL ;
    PORT
      LAYER M3 ;
        RECT  78.12 0 78.138 0.144 ;
    END
  END xai[237]
  PIN xai[238]
    DIRECTION INPUT ;
    USE SIGNAL ;
    PORT
      LAYER M5 ;
        RECT  78.432 0 78.456 0.192 ;
    END
  END xai[238]
  PIN xai[239]
    DIRECTION INPUT ;
    USE SIGNAL ;
    PORT
      LAYER M3 ;
        RECT  78.696 0 78.714 0.144 ;
    END
  END xai[239]
  PIN xai[23]
    DIRECTION INPUT ;
    USE SIGNAL ;
    PORT
      LAYER M3 ;
        RECT  16.056 0 16.074 0.144 ;
    END
  END xai[23]
  PIN xai[240]
    DIRECTION INPUT ;
    USE SIGNAL ;
    PORT
      LAYER M5 ;
        RECT  79.008 0 79.032 0.192 ;
    END
  END xai[240]
  PIN xai[241]
    DIRECTION INPUT ;
    USE SIGNAL ;
    PORT
      LAYER M3 ;
        RECT  79.272 0 79.29 0.144 ;
    END
  END xai[241]
  PIN xai[242]
    DIRECTION INPUT ;
    USE SIGNAL ;
    PORT
      LAYER M5 ;
        RECT  79.584 0 79.608 0.192 ;
    END
  END xai[242]
  PIN xai[243]
    DIRECTION INPUT ;
    USE SIGNAL ;
    PORT
      LAYER M3 ;
        RECT  79.848 0 79.866 0.144 ;
    END
  END xai[243]
  PIN xai[244]
    DIRECTION INPUT ;
    USE SIGNAL ;
    PORT
      LAYER M5 ;
        RECT  80.16 0 80.184 0.192 ;
    END
  END xai[244]
  PIN xai[245]
    DIRECTION INPUT ;
    USE SIGNAL ;
    PORT
      LAYER M3 ;
        RECT  80.46 0 80.478 0.144 ;
    END
  END xai[245]
  PIN xai[246]
    DIRECTION INPUT ;
    USE SIGNAL ;
    PORT
      LAYER M5 ;
        RECT  80.736 0 80.76 0.192 ;
    END
  END xai[246]
  PIN xai[247]
    DIRECTION INPUT ;
    USE SIGNAL ;
    PORT
      LAYER M3 ;
        RECT  81.036 0 81.054 0.144 ;
    END
  END xai[247]
  PIN xai[248]
    DIRECTION INPUT ;
    USE SIGNAL ;
    PORT
      LAYER M5 ;
        RECT  81.312 0 81.336 0.192 ;
    END
  END xai[248]
  PIN xai[249]
    DIRECTION INPUT ;
    USE SIGNAL ;
    PORT
      LAYER M3 ;
        RECT  81.612 0 81.63 0.144 ;
    END
  END xai[249]
  PIN xai[24]
    DIRECTION INPUT ;
    USE SIGNAL ;
    PORT
      LAYER M5 ;
        RECT  16.368 0 16.392 0.192 ;
    END
  END xai[24]
  PIN xai[250]
    DIRECTION INPUT ;
    USE SIGNAL ;
    PORT
      LAYER M5 ;
        RECT  81.888 0 81.912 0.192 ;
    END
  END xai[250]
  PIN xai[251]
    DIRECTION INPUT ;
    USE SIGNAL ;
    PORT
      LAYER M3 ;
        RECT  82.188 0 82.206 0.144 ;
    END
  END xai[251]
  PIN xai[252]
    DIRECTION INPUT ;
    USE SIGNAL ;
    PORT
      LAYER M5 ;
        RECT  82.464 0 82.488 0.192 ;
    END
  END xai[252]
  PIN xai[253]
    DIRECTION INPUT ;
    USE SIGNAL ;
    PORT
      LAYER M3 ;
        RECT  82.764 0 82.782 0.144 ;
    END
  END xai[253]
  PIN xai[254]
    DIRECTION INPUT ;
    USE SIGNAL ;
    PORT
      LAYER M5 ;
        RECT  83.04 0 83.064 0.192 ;
    END
  END xai[254]
  PIN xai[255]
    DIRECTION INPUT ;
    USE SIGNAL ;
    PORT
      LAYER M3 ;
        RECT  83.34 0 83.358 0.144 ;
    END
  END xai[255]
  PIN xai[256]
    DIRECTION INPUT ;
    USE SIGNAL ;
    PORT
      LAYER M5 ;
        RECT  83.616 0 83.64 0.192 ;
    END
  END xai[256]
  PIN xai[257]
    DIRECTION INPUT ;
    USE SIGNAL ;
    PORT
      LAYER M3 ;
        RECT  83.916 0 83.934 0.144 ;
    END
  END xai[257]
  PIN xai[258]
    DIRECTION INPUT ;
    USE SIGNAL ;
    PORT
      LAYER M5 ;
        RECT  84.192 0 84.216 0.192 ;
    END
  END xai[258]
  PIN xai[259]
    DIRECTION INPUT ;
    USE SIGNAL ;
    PORT
      LAYER M3 ;
        RECT  84.492 0 84.51 0.144 ;
    END
  END xai[259]
  PIN xai[25]
    DIRECTION INPUT ;
    USE SIGNAL ;
    PORT
      LAYER M3 ;
        RECT  16.632 0 16.65 0.144 ;
    END
  END xai[25]
  PIN xai[260]
    DIRECTION INPUT ;
    USE SIGNAL ;
    PORT
      LAYER M5 ;
        RECT  84.816 0 84.84 0.192 ;
    END
  END xai[260]
  PIN xai[261]
    DIRECTION INPUT ;
    USE SIGNAL ;
    PORT
      LAYER M3 ;
        RECT  85.068 0 85.086 0.144 ;
    END
  END xai[261]
  PIN xai[262]
    DIRECTION INPUT ;
    USE SIGNAL ;
    PORT
      LAYER M5 ;
        RECT  85.392 0 85.416 0.192 ;
    END
  END xai[262]
  PIN xai[263]
    DIRECTION INPUT ;
    USE SIGNAL ;
    PORT
      LAYER M3 ;
        RECT  85.68 0 85.698 0.144 ;
    END
  END xai[263]
  PIN xai[264]
    DIRECTION INPUT ;
    USE SIGNAL ;
    PORT
      LAYER M5 ;
        RECT  85.968 0 85.992 0.192 ;
    END
  END xai[264]
  PIN xai[265]
    DIRECTION INPUT ;
    USE SIGNAL ;
    PORT
      LAYER M3 ;
        RECT  86.256 0 86.274 0.144 ;
    END
  END xai[265]
  PIN xai[266]
    DIRECTION INPUT ;
    USE SIGNAL ;
    PORT
      LAYER M5 ;
        RECT  86.544 0 86.568 0.192 ;
    END
  END xai[266]
  PIN xai[267]
    DIRECTION INPUT ;
    USE SIGNAL ;
    PORT
      LAYER M3 ;
        RECT  86.832 0 86.85 0.144 ;
    END
  END xai[267]
  PIN xai[268]
    DIRECTION INPUT ;
    USE SIGNAL ;
    PORT
      LAYER M5 ;
        RECT  87.12 0 87.144 0.192 ;
    END
  END xai[268]
  PIN xai[269]
    DIRECTION INPUT ;
    USE SIGNAL ;
    PORT
      LAYER M3 ;
        RECT  87.408 0 87.426 0.144 ;
    END
  END xai[269]
  PIN xai[26]
    DIRECTION INPUT ;
    USE SIGNAL ;
    PORT
      LAYER M5 ;
        RECT  16.944 0 16.968 0.192 ;
    END
  END xai[26]
  PIN xai[270]
    DIRECTION INPUT ;
    USE SIGNAL ;
    PORT
      LAYER M5 ;
        RECT  87.696 0 87.72 0.192 ;
    END
  END xai[270]
  PIN xai[271]
    DIRECTION INPUT ;
    USE SIGNAL ;
    PORT
      LAYER M3 ;
        RECT  87.984 0 88.002 0.144 ;
    END
  END xai[271]
  PIN xai[272]
    DIRECTION INPUT ;
    USE SIGNAL ;
    PORT
      LAYER M5 ;
        RECT  88.272 0 88.296 0.192 ;
    END
  END xai[272]
  PIN xai[273]
    DIRECTION INPUT ;
    USE SIGNAL ;
    PORT
      LAYER M3 ;
        RECT  88.56 0 88.578 0.144 ;
    END
  END xai[273]
  PIN xai[274]
    DIRECTION INPUT ;
    USE SIGNAL ;
    PORT
      LAYER M5 ;
        RECT  88.848 0 88.872 0.192 ;
    END
  END xai[274]
  PIN xai[275]
    DIRECTION INPUT ;
    USE SIGNAL ;
    PORT
      LAYER M3 ;
        RECT  89.136 0 89.154 0.144 ;
    END
  END xai[275]
  PIN xai[276]
    DIRECTION INPUT ;
    USE SIGNAL ;
    PORT
      LAYER M5 ;
        RECT  89.424 0 89.448 0.192 ;
    END
  END xai[276]
  PIN xai[277]
    DIRECTION INPUT ;
    USE SIGNAL ;
    PORT
      LAYER M3 ;
        RECT  89.712 0 89.73 0.144 ;
    END
  END xai[277]
  PIN xai[278]
    DIRECTION INPUT ;
    USE SIGNAL ;
    PORT
      LAYER M5 ;
        RECT  90 0 90.024 0.192 ;
    END
  END xai[278]
  PIN xai[279]
    DIRECTION INPUT ;
    USE SIGNAL ;
    PORT
      LAYER M3 ;
        RECT  90.324 0 90.342 0.144 ;
    END
  END xai[279]
  PIN xai[27]
    DIRECTION INPUT ;
    USE SIGNAL ;
    PORT
      LAYER M3 ;
        RECT  17.208 0 17.226 0.144 ;
    END
  END xai[27]
  PIN xai[280]
    DIRECTION INPUT ;
    USE SIGNAL ;
    PORT
      LAYER M5 ;
        RECT  90.576 0 90.6 0.192 ;
    END
  END xai[280]
  PIN xai[281]
    DIRECTION INPUT ;
    USE SIGNAL ;
    PORT
      LAYER M3 ;
        RECT  90.9 0 90.918 0.144 ;
    END
  END xai[281]
  PIN xai[282]
    DIRECTION INPUT ;
    USE SIGNAL ;
    PORT
      LAYER M5 ;
        RECT  91.152 0 91.176 0.192 ;
    END
  END xai[282]
  PIN xai[28]
    DIRECTION INPUT ;
    USE SIGNAL ;
    PORT
      LAYER M5 ;
        RECT  17.52 0 17.544 0.192 ;
    END
  END xai[28]
  PIN xai[29]
    DIRECTION INPUT ;
    USE SIGNAL ;
    PORT
      LAYER M3 ;
        RECT  17.784 0 17.802 0.144 ;
    END
  END xai[29]
  PIN xai[2]
    DIRECTION INPUT ;
    USE SIGNAL ;
    PORT
      LAYER M5 ;
        RECT  9.984 0 10.008 0.192 ;
    END
  END xai[2]
  PIN xai[30]
    DIRECTION INPUT ;
    USE SIGNAL ;
    PORT
      LAYER M5 ;
        RECT  18.096 0 18.12 0.192 ;
    END
  END xai[30]
  PIN xai[31]
    DIRECTION INPUT ;
    USE SIGNAL ;
    PORT
      LAYER M3 ;
        RECT  18.36 0 18.378 0.144 ;
    END
  END xai[31]
  PIN xai[32]
    DIRECTION INPUT ;
    USE SIGNAL ;
    PORT
      LAYER M5 ;
        RECT  18.672 0 18.696 0.192 ;
    END
  END xai[32]
  PIN xai[33]
    DIRECTION INPUT ;
    USE SIGNAL ;
    PORT
      LAYER M3 ;
        RECT  18.972 0 18.99 0.144 ;
    END
  END xai[33]
  PIN xai[34]
    DIRECTION INPUT ;
    USE SIGNAL ;
    PORT
      LAYER M5 ;
        RECT  19.248 0 19.272 0.192 ;
    END
  END xai[34]
  PIN xai[35]
    DIRECTION INPUT ;
    USE SIGNAL ;
    PORT
      LAYER M3 ;
        RECT  19.548 0 19.566 0.144 ;
    END
  END xai[35]
  PIN xai[36]
    DIRECTION INPUT ;
    USE SIGNAL ;
    PORT
      LAYER M5 ;
        RECT  19.824 0 19.848 0.192 ;
    END
  END xai[36]
  PIN xai[37]
    DIRECTION INPUT ;
    USE SIGNAL ;
    PORT
      LAYER M3 ;
        RECT  20.124 0 20.142 0.144 ;
    END
  END xai[37]
  PIN xai[38]
    DIRECTION INPUT ;
    USE SIGNAL ;
    PORT
      LAYER M5 ;
        RECT  20.4 0 20.424 0.192 ;
    END
  END xai[38]
  PIN xai[39]
    DIRECTION INPUT ;
    USE SIGNAL ;
    PORT
      LAYER M3 ;
        RECT  20.7 0 20.718 0.144 ;
    END
  END xai[39]
  PIN xai[3]
    DIRECTION INPUT ;
    USE SIGNAL ;
    PORT
      LAYER M3 ;
        RECT  10.26 0 10.278 0.144 ;
    END
  END xai[3]
  PIN xai[40]
    DIRECTION INPUT ;
    USE SIGNAL ;
    PORT
      LAYER M5 ;
        RECT  20.976 0 21 0.192 ;
    END
  END xai[40]
  PIN xai[41]
    DIRECTION INPUT ;
    USE SIGNAL ;
    PORT
      LAYER M3 ;
        RECT  21.276 0 21.294 0.144 ;
    END
  END xai[41]
  PIN xai[42]
    DIRECTION INPUT ;
    USE SIGNAL ;
    PORT
      LAYER M5 ;
        RECT  21.552 0 21.576 0.192 ;
    END
  END xai[42]
  PIN xai[43]
    DIRECTION INPUT ;
    USE SIGNAL ;
    PORT
      LAYER M3 ;
        RECT  21.852 0 21.87 0.144 ;
    END
  END xai[43]
  PIN xai[44]
    DIRECTION INPUT ;
    USE SIGNAL ;
    PORT
      LAYER M5 ;
        RECT  22.128 0 22.152 0.192 ;
    END
  END xai[44]
  PIN xai[45]
    DIRECTION INPUT ;
    USE SIGNAL ;
    PORT
      LAYER M3 ;
        RECT  22.428 0 22.446 0.144 ;
    END
  END xai[45]
  PIN xai[46]
    DIRECTION INPUT ;
    USE SIGNAL ;
    PORT
      LAYER M5 ;
        RECT  22.704 0 22.728 0.192 ;
    END
  END xai[46]
  PIN xai[47]
    DIRECTION INPUT ;
    USE SIGNAL ;
    PORT
      LAYER M3 ;
        RECT  23.004 0 23.022 0.144 ;
    END
  END xai[47]
  PIN xai[48]
    DIRECTION INPUT ;
    USE SIGNAL ;
    PORT
      LAYER M5 ;
        RECT  23.328 0 23.352 0.192 ;
    END
  END xai[48]
  PIN xai[49]
    DIRECTION INPUT ;
    USE SIGNAL ;
    PORT
      LAYER M3 ;
        RECT  23.616 0 23.634 0.144 ;
    END
  END xai[49]
  PIN xai[4]
    DIRECTION INPUT ;
    USE SIGNAL ;
    PORT
      LAYER M5 ;
        RECT  10.56 0 10.584 0.192 ;
    END
  END xai[4]
  PIN xai[50]
    DIRECTION INPUT ;
    USE SIGNAL ;
    PORT
      LAYER M5 ;
        RECT  23.904 0 23.928 0.192 ;
    END
  END xai[50]
  PIN xai[51]
    DIRECTION INPUT ;
    USE SIGNAL ;
    PORT
      LAYER M3 ;
        RECT  24.192 0 24.21 0.144 ;
    END
  END xai[51]
  PIN xai[52]
    DIRECTION INPUT ;
    USE SIGNAL ;
    PORT
      LAYER M5 ;
        RECT  24.48 0 24.504 0.192 ;
    END
  END xai[52]
  PIN xai[53]
    DIRECTION INPUT ;
    USE SIGNAL ;
    PORT
      LAYER M3 ;
        RECT  24.768 0 24.786 0.144 ;
    END
  END xai[53]
  PIN xai[54]
    DIRECTION INPUT ;
    USE SIGNAL ;
    PORT
      LAYER M5 ;
        RECT  25.056 0 25.08 0.192 ;
    END
  END xai[54]
  PIN xai[55]
    DIRECTION INPUT ;
    USE SIGNAL ;
    PORT
      LAYER M3 ;
        RECT  25.344 0 25.362 0.144 ;
    END
  END xai[55]
  PIN xai[56]
    DIRECTION INPUT ;
    USE SIGNAL ;
    PORT
      LAYER M5 ;
        RECT  25.632 0 25.656 0.192 ;
    END
  END xai[56]
  PIN xai[57]
    DIRECTION INPUT ;
    USE SIGNAL ;
    PORT
      LAYER M3 ;
        RECT  25.92 0 25.938 0.144 ;
    END
  END xai[57]
  PIN xai[58]
    DIRECTION INPUT ;
    USE SIGNAL ;
    PORT
      LAYER M5 ;
        RECT  26.208 0 26.232 0.192 ;
    END
  END xai[58]
  PIN xai[59]
    DIRECTION INPUT ;
    USE SIGNAL ;
    PORT
      LAYER M3 ;
        RECT  26.496 0 26.514 0.144 ;
    END
  END xai[59]
  PIN xai[5]
    DIRECTION INPUT ;
    USE SIGNAL ;
    PORT
      LAYER M3 ;
        RECT  10.836 0 10.854 0.144 ;
    END
  END xai[5]
  PIN xai[60]
    DIRECTION INPUT ;
    USE SIGNAL ;
    PORT
      LAYER M5 ;
        RECT  26.784 0 26.808 0.192 ;
    END
  END xai[60]
  PIN xai[61]
    DIRECTION INPUT ;
    USE SIGNAL ;
    PORT
      LAYER M3 ;
        RECT  27.072 0 27.09 0.144 ;
    END
  END xai[61]
  PIN xai[62]
    DIRECTION INPUT ;
    USE SIGNAL ;
    PORT
      LAYER M5 ;
        RECT  27.36 0 27.384 0.192 ;
    END
  END xai[62]
  PIN xai[63]
    DIRECTION INPUT ;
    USE SIGNAL ;
    PORT
      LAYER M3 ;
        RECT  27.648 0 27.666 0.144 ;
    END
  END xai[63]
  PIN xai[64]
    DIRECTION INPUT ;
    USE SIGNAL ;
    PORT
      LAYER M5 ;
        RECT  27.936 0 27.96 0.192 ;
    END
  END xai[64]
  PIN xai[65]
    DIRECTION INPUT ;
    USE SIGNAL ;
    PORT
      LAYER M3 ;
        RECT  28.224 0 28.242 0.144 ;
    END
  END xai[65]
  PIN xai[66]
    DIRECTION INPUT ;
    USE SIGNAL ;
    PORT
      LAYER M5 ;
        RECT  28.512 0 28.536 0.192 ;
    END
  END xai[66]
  PIN xai[67]
    DIRECTION INPUT ;
    USE SIGNAL ;
    PORT
      LAYER M3 ;
        RECT  28.836 0 28.854 0.144 ;
    END
  END xai[67]
  PIN xai[68]
    DIRECTION INPUT ;
    USE SIGNAL ;
    PORT
      LAYER M5 ;
        RECT  29.088 0 29.112 0.192 ;
    END
  END xai[68]
  PIN xai[69]
    DIRECTION INPUT ;
    USE SIGNAL ;
    PORT
      LAYER M3 ;
        RECT  29.412 0 29.43 0.144 ;
    END
  END xai[69]
  PIN xai[6]
    DIRECTION INPUT ;
    USE SIGNAL ;
    PORT
      LAYER M5 ;
        RECT  11.136 0 11.16 0.192 ;
    END
  END xai[6]
  PIN xai[70]
    DIRECTION INPUT ;
    USE SIGNAL ;
    PORT
      LAYER M5 ;
        RECT  29.664 0 29.688 0.192 ;
    END
  END xai[70]
  PIN xai[71]
    DIRECTION INPUT ;
    USE SIGNAL ;
    PORT
      LAYER M3 ;
        RECT  29.988 0 30.006 0.144 ;
    END
  END xai[71]
  PIN xai[72]
    DIRECTION INPUT ;
    USE SIGNAL ;
    PORT
      LAYER M5 ;
        RECT  30.288 0 30.312 0.192 ;
    END
  END xai[72]
  PIN xai[73]
    DIRECTION INPUT ;
    USE SIGNAL ;
    PORT
      LAYER M3 ;
        RECT  30.564 0 30.582 0.144 ;
    END
  END xai[73]
  PIN xai[74]
    DIRECTION INPUT ;
    USE SIGNAL ;
    PORT
      LAYER M5 ;
        RECT  30.864 0 30.888 0.192 ;
    END
  END xai[74]
  PIN xai[75]
    DIRECTION INPUT ;
    USE SIGNAL ;
    PORT
      LAYER M3 ;
        RECT  31.14 0 31.158 0.144 ;
    END
  END xai[75]
  PIN xai[76]
    DIRECTION INPUT ;
    USE SIGNAL ;
    PORT
      LAYER M5 ;
        RECT  31.44 0 31.464 0.192 ;
    END
  END xai[76]
  PIN xai[77]
    DIRECTION INPUT ;
    USE SIGNAL ;
    PORT
      LAYER M3 ;
        RECT  31.716 0 31.734 0.144 ;
    END
  END xai[77]
  PIN xai[78]
    DIRECTION INPUT ;
    USE SIGNAL ;
    PORT
      LAYER M5 ;
        RECT  32.016 0 32.04 0.192 ;
    END
  END xai[78]
  PIN xai[79]
    DIRECTION INPUT ;
    USE SIGNAL ;
    PORT
      LAYER M3 ;
        RECT  32.292 0 32.31 0.144 ;
    END
  END xai[79]
  PIN xai[7]
    DIRECTION INPUT ;
    USE SIGNAL ;
    PORT
      LAYER M3 ;
        RECT  11.412 0 11.43 0.144 ;
    END
  END xai[7]
  PIN xai[80]
    DIRECTION INPUT ;
    USE SIGNAL ;
    PORT
      LAYER M5 ;
        RECT  32.592 0 32.616 0.192 ;
    END
  END xai[80]
  PIN xai[81]
    DIRECTION INPUT ;
    USE SIGNAL ;
    PORT
      LAYER M3 ;
        RECT  32.868 0 32.886 0.144 ;
    END
  END xai[81]
  PIN xai[82]
    DIRECTION INPUT ;
    USE SIGNAL ;
    PORT
      LAYER M5 ;
        RECT  33.168 0 33.192 0.192 ;
    END
  END xai[82]
  PIN xai[83]
    DIRECTION INPUT ;
    USE SIGNAL ;
    PORT
      LAYER M3 ;
        RECT  33.444 0 33.462 0.144 ;
    END
  END xai[83]
  PIN xai[84]
    DIRECTION INPUT ;
    USE SIGNAL ;
    PORT
      LAYER M5 ;
        RECT  33.744 0 33.768 0.192 ;
    END
  END xai[84]
  PIN xai[85]
    DIRECTION INPUT ;
    USE SIGNAL ;
    PORT
      LAYER M3 ;
        RECT  34.056 0 34.074 0.144 ;
    END
  END xai[85]
  PIN xai[86]
    DIRECTION INPUT ;
    USE SIGNAL ;
    PORT
      LAYER M5 ;
        RECT  34.32 0 34.344 0.192 ;
    END
  END xai[86]
  PIN xai[87]
    DIRECTION INPUT ;
    USE SIGNAL ;
    PORT
      LAYER M3 ;
        RECT  34.632 0 34.65 0.144 ;
    END
  END xai[87]
  PIN xai[88]
    DIRECTION INPUT ;
    USE SIGNAL ;
    PORT
      LAYER M5 ;
        RECT  34.896 0 34.92 0.192 ;
    END
  END xai[88]
  PIN xai[89]
    DIRECTION INPUT ;
    USE SIGNAL ;
    PORT
      LAYER M3 ;
        RECT  35.208 0 35.226 0.144 ;
    END
  END xai[89]
  PIN xai[8]
    DIRECTION INPUT ;
    USE SIGNAL ;
    PORT
      LAYER M5 ;
        RECT  11.712 0 11.736 0.192 ;
    END
  END xai[8]
  PIN xai[90]
    DIRECTION INPUT ;
    USE SIGNAL ;
    PORT
      LAYER M5 ;
        RECT  35.472 0 35.496 0.192 ;
    END
  END xai[90]
  PIN xai[91]
    DIRECTION INPUT ;
    USE SIGNAL ;
    PORT
      LAYER M3 ;
        RECT  35.784 0 35.802 0.144 ;
    END
  END xai[91]
  PIN xai[92]
    DIRECTION INPUT ;
    USE SIGNAL ;
    PORT
      LAYER M5 ;
        RECT  36.048 0 36.072 0.192 ;
    END
  END xai[92]
  PIN xai[93]
    DIRECTION INPUT ;
    USE SIGNAL ;
    PORT
      LAYER M3 ;
        RECT  36.36 0 36.378 0.144 ;
    END
  END xai[93]
  PIN xai[94]
    DIRECTION INPUT ;
    USE SIGNAL ;
    PORT
      LAYER M5 ;
        RECT  36.624 0 36.648 0.192 ;
    END
  END xai[94]
  PIN xai[95]
    DIRECTION INPUT ;
    USE SIGNAL ;
    PORT
      LAYER M3 ;
        RECT  36.936 0 36.954 0.144 ;
    END
  END xai[95]
  PIN xai[96]
    DIRECTION INPUT ;
    USE SIGNAL ;
    PORT
      LAYER M5 ;
        RECT  37.248 0 37.272 0.192 ;
    END
  END xai[96]
  PIN xai[97]
    DIRECTION INPUT ;
    USE SIGNAL ;
    PORT
      LAYER M3 ;
        RECT  37.512 0 37.53 0.144 ;
    END
  END xai[97]
  PIN xai[98]
    DIRECTION INPUT ;
    USE SIGNAL ;
    PORT
      LAYER M5 ;
        RECT  37.824 0 37.848 0.192 ;
    END
  END xai[98]
  PIN xai[99]
    DIRECTION INPUT ;
    USE SIGNAL ;
    PORT
      LAYER M3 ;
        RECT  38.088 0 38.106 0.144 ;
    END
  END xai[99]
  PIN xai[9]
    DIRECTION INPUT ;
    USE SIGNAL ;
    PORT
      LAYER M3 ;
        RECT  11.988 0 12.006 0.144 ;
    END
  END xai[9]
  PIN xb[0]
    DIRECTION OUTPUT ;
    USE SIGNAL ;
    PORT
      LAYER M3 ;
        RECT  92.556 30.096 92.574 30.24 ;
    END
  END xb[0]
  PIN xb[100]
    DIRECTION OUTPUT ;
    USE SIGNAL ;
    PORT
      LAYER M3 ;
        RECT  121.14 30.096 121.158 30.24 ;
    END
  END xb[100]
  PIN xb[101]
    DIRECTION OUTPUT ;
    USE SIGNAL ;
    PORT
      LAYER M5 ;
        RECT  121.44 30.048 121.464 30.24 ;
    END
  END xb[101]
  PIN xb[102]
    DIRECTION OUTPUT ;
    USE SIGNAL ;
    PORT
      LAYER M3 ;
        RECT  121.716 30.096 121.734 30.24 ;
    END
  END xb[102]
  PIN xb[103]
    DIRECTION OUTPUT ;
    USE SIGNAL ;
    PORT
      LAYER M5 ;
        RECT  122.016 30.048 122.04 30.24 ;
    END
  END xb[103]
  PIN xb[104]
    DIRECTION OUTPUT ;
    USE SIGNAL ;
    PORT
      LAYER M3 ;
        RECT  122.292 30.096 122.31 30.24 ;
    END
  END xb[104]
  PIN xb[105]
    DIRECTION OUTPUT ;
    USE SIGNAL ;
    PORT
      LAYER M5 ;
        RECT  122.544 30.048 122.568 30.24 ;
    END
  END xb[105]
  PIN xb[106]
    DIRECTION OUTPUT ;
    USE SIGNAL ;
    PORT
      LAYER M3 ;
        RECT  122.868 30.096 122.886 30.24 ;
    END
  END xb[106]
  PIN xb[107]
    DIRECTION OUTPUT ;
    USE SIGNAL ;
    PORT
      LAYER M5 ;
        RECT  123.12 30.048 123.144 30.24 ;
    END
  END xb[107]
  PIN xb[108]
    DIRECTION OUTPUT ;
    USE SIGNAL ;
    PORT
      LAYER M3 ;
        RECT  123.444 30.096 123.462 30.24 ;
    END
  END xb[108]
  PIN xb[109]
    DIRECTION OUTPUT ;
    USE SIGNAL ;
    PORT
      LAYER M5 ;
        RECT  123.696 30.048 123.72 30.24 ;
    END
  END xb[109]
  PIN xb[10]
    DIRECTION OUTPUT ;
    USE SIGNAL ;
    PORT
      LAYER M3 ;
        RECT  95.4 30.096 95.418 30.24 ;
    END
  END xb[10]
  PIN xb[110]
    DIRECTION OUTPUT ;
    USE SIGNAL ;
    PORT
      LAYER M3 ;
        RECT  123.984 30.096 124.002 30.24 ;
    END
  END xb[110]
  PIN xb[111]
    DIRECTION OUTPUT ;
    USE SIGNAL ;
    PORT
      LAYER M5 ;
        RECT  124.272 30.048 124.296 30.24 ;
    END
  END xb[111]
  PIN xb[112]
    DIRECTION OUTPUT ;
    USE SIGNAL ;
    PORT
      LAYER M3 ;
        RECT  124.56 30.096 124.578 30.24 ;
    END
  END xb[112]
  PIN xb[113]
    DIRECTION OUTPUT ;
    USE SIGNAL ;
    PORT
      LAYER M5 ;
        RECT  124.848 30.048 124.872 30.24 ;
    END
  END xb[113]
  PIN xb[114]
    DIRECTION OUTPUT ;
    USE SIGNAL ;
    PORT
      LAYER M3 ;
        RECT  125.136 30.096 125.154 30.24 ;
    END
  END xb[114]
  PIN xb[115]
    DIRECTION OUTPUT ;
    USE SIGNAL ;
    PORT
      LAYER M5 ;
        RECT  125.424 30.048 125.448 30.24 ;
    END
  END xb[115]
  PIN xb[116]
    DIRECTION OUTPUT ;
    USE SIGNAL ;
    PORT
      LAYER M3 ;
        RECT  125.712 30.096 125.73 30.24 ;
    END
  END xb[116]
  PIN xb[117]
    DIRECTION OUTPUT ;
    USE SIGNAL ;
    PORT
      LAYER M5 ;
        RECT  126 30.048 126.024 30.24 ;
    END
  END xb[117]
  PIN xb[118]
    DIRECTION OUTPUT ;
    USE SIGNAL ;
    PORT
      LAYER M3 ;
        RECT  126.288 30.096 126.306 30.24 ;
    END
  END xb[118]
  PIN xb[119]
    DIRECTION OUTPUT ;
    USE SIGNAL ;
    PORT
      LAYER M5 ;
        RECT  126.576 30.048 126.6 30.24 ;
    END
  END xb[119]
  PIN xb[11]
    DIRECTION OUTPUT ;
    USE SIGNAL ;
    PORT
      LAYER M5 ;
        RECT  95.664 30.048 95.688 30.24 ;
    END
  END xb[11]
  PIN xb[120]
    DIRECTION OUTPUT ;
    USE SIGNAL ;
    PORT
      LAYER M3 ;
        RECT  126.864 30.096 126.882 30.24 ;
    END
  END xb[120]
  PIN xb[121]
    DIRECTION OUTPUT ;
    USE SIGNAL ;
    PORT
      LAYER M5 ;
        RECT  127.152 30.048 127.176 30.24 ;
    END
  END xb[121]
  PIN xb[122]
    DIRECTION OUTPUT ;
    USE SIGNAL ;
    PORT
      LAYER M3 ;
        RECT  127.44 30.096 127.458 30.24 ;
    END
  END xb[122]
  PIN xb[123]
    DIRECTION OUTPUT ;
    USE SIGNAL ;
    PORT
      LAYER M5 ;
        RECT  127.728 30.048 127.752 30.24 ;
    END
  END xb[123]
  PIN xb[124]
    DIRECTION OUTPUT ;
    USE SIGNAL ;
    PORT
      LAYER M3 ;
        RECT  128.016 30.096 128.034 30.24 ;
    END
  END xb[124]
  PIN xb[125]
    DIRECTION OUTPUT ;
    USE SIGNAL ;
    PORT
      LAYER M5 ;
        RECT  128.304 30.048 128.328 30.24 ;
    END
  END xb[125]
  PIN xb[126]
    DIRECTION OUTPUT ;
    USE SIGNAL ;
    PORT
      LAYER M3 ;
        RECT  128.592 30.096 128.61 30.24 ;
    END
  END xb[126]
  PIN xb[127]
    DIRECTION OUTPUT ;
    USE SIGNAL ;
    PORT
      LAYER M5 ;
        RECT  128.88 30.048 128.904 30.24 ;
    END
  END xb[127]
  PIN xb[128]
    DIRECTION OUTPUT ;
    USE SIGNAL ;
    PORT
      LAYER M3 ;
        RECT  129.132 30.096 129.15 30.24 ;
    END
  END xb[128]
  PIN xb[129]
    DIRECTION OUTPUT ;
    USE SIGNAL ;
    PORT
      LAYER M5 ;
        RECT  129.408 30.048 129.432 30.24 ;
    END
  END xb[129]
  PIN xb[12]
    DIRECTION OUTPUT ;
    USE SIGNAL ;
    PORT
      LAYER M3 ;
        RECT  95.976 30.096 95.994 30.24 ;
    END
  END xb[12]
  PIN xb[130]
    DIRECTION OUTPUT ;
    USE SIGNAL ;
    PORT
      LAYER M3 ;
        RECT  129.708 30.096 129.726 30.24 ;
    END
  END xb[130]
  PIN xb[131]
    DIRECTION OUTPUT ;
    USE SIGNAL ;
    PORT
      LAYER M5 ;
        RECT  129.984 30.048 130.008 30.24 ;
    END
  END xb[131]
  PIN xb[132]
    DIRECTION OUTPUT ;
    USE SIGNAL ;
    PORT
      LAYER M3 ;
        RECT  130.284 30.096 130.302 30.24 ;
    END
  END xb[132]
  PIN xb[133]
    DIRECTION OUTPUT ;
    USE SIGNAL ;
    PORT
      LAYER M5 ;
        RECT  130.56 30.048 130.584 30.24 ;
    END
  END xb[133]
  PIN xb[134]
    DIRECTION OUTPUT ;
    USE SIGNAL ;
    PORT
      LAYER M3 ;
        RECT  130.86 30.096 130.878 30.24 ;
    END
  END xb[134]
  PIN xb[135]
    DIRECTION OUTPUT ;
    USE SIGNAL ;
    PORT
      LAYER M5 ;
        RECT  131.136 30.048 131.16 30.24 ;
    END
  END xb[135]
  PIN xb[136]
    DIRECTION OUTPUT ;
    USE SIGNAL ;
    PORT
      LAYER M3 ;
        RECT  131.436 30.096 131.454 30.24 ;
    END
  END xb[136]
  PIN xb[137]
    DIRECTION OUTPUT ;
    USE SIGNAL ;
    PORT
      LAYER M5 ;
        RECT  131.712 30.048 131.736 30.24 ;
    END
  END xb[137]
  PIN xb[138]
    DIRECTION OUTPUT ;
    USE SIGNAL ;
    PORT
      LAYER M3 ;
        RECT  132.012 30.096 132.03 30.24 ;
    END
  END xb[138]
  PIN xb[139]
    DIRECTION OUTPUT ;
    USE SIGNAL ;
    PORT
      LAYER M5 ;
        RECT  132.288 30.048 132.312 30.24 ;
    END
  END xb[139]
  PIN xb[13]
    DIRECTION OUTPUT ;
    USE SIGNAL ;
    PORT
      LAYER M5 ;
        RECT  96.24 30.048 96.264 30.24 ;
    END
  END xb[13]
  PIN xb[140]
    DIRECTION OUTPUT ;
    USE SIGNAL ;
    PORT
      LAYER M3 ;
        RECT  132.588 30.096 132.606 30.24 ;
    END
  END xb[140]
  PIN xb[141]
    DIRECTION OUTPUT ;
    USE SIGNAL ;
    PORT
      LAYER M5 ;
        RECT  132.864 30.048 132.888 30.24 ;
    END
  END xb[141]
  PIN xb[142]
    DIRECTION OUTPUT ;
    USE SIGNAL ;
    PORT
      LAYER M3 ;
        RECT  133.164 30.096 133.182 30.24 ;
    END
  END xb[142]
  PIN xb[143]
    DIRECTION OUTPUT ;
    USE SIGNAL ;
    PORT
      LAYER M5 ;
        RECT  133.44 30.048 133.464 30.24 ;
    END
  END xb[143]
  PIN xb[144]
    DIRECTION OUTPUT ;
    USE SIGNAL ;
    PORT
      LAYER M3 ;
        RECT  133.74 30.096 133.758 30.24 ;
    END
  END xb[144]
  PIN xb[145]
    DIRECTION OUTPUT ;
    USE SIGNAL ;
    PORT
      LAYER M5 ;
        RECT  134.016 30.048 134.04 30.24 ;
    END
  END xb[145]
  PIN xb[146]
    DIRECTION OUTPUT ;
    USE SIGNAL ;
    PORT
      LAYER M3 ;
        RECT  134.28 30.096 134.298 30.24 ;
    END
  END xb[146]
  PIN xb[147]
    DIRECTION OUTPUT ;
    USE SIGNAL ;
    PORT
      LAYER M5 ;
        RECT  134.592 30.048 134.616 30.24 ;
    END
  END xb[147]
  PIN xb[148]
    DIRECTION OUTPUT ;
    USE SIGNAL ;
    PORT
      LAYER M3 ;
        RECT  134.856 30.096 134.874 30.24 ;
    END
  END xb[148]
  PIN xb[149]
    DIRECTION OUTPUT ;
    USE SIGNAL ;
    PORT
      LAYER M5 ;
        RECT  135.168 30.048 135.192 30.24 ;
    END
  END xb[149]
  PIN xb[14]
    DIRECTION OUTPUT ;
    USE SIGNAL ;
    PORT
      LAYER M3 ;
        RECT  96.552 30.096 96.57 30.24 ;
    END
  END xb[14]
  PIN xb[150]
    DIRECTION OUTPUT ;
    USE SIGNAL ;
    PORT
      LAYER M3 ;
        RECT  135.432 30.096 135.45 30.24 ;
    END
  END xb[150]
  PIN xb[151]
    DIRECTION OUTPUT ;
    USE SIGNAL ;
    PORT
      LAYER M5 ;
        RECT  135.744 30.048 135.768 30.24 ;
    END
  END xb[151]
  PIN xb[152]
    DIRECTION OUTPUT ;
    USE SIGNAL ;
    PORT
      LAYER M3 ;
        RECT  136.008 30.096 136.026 30.24 ;
    END
  END xb[152]
  PIN xb[153]
    DIRECTION OUTPUT ;
    USE SIGNAL ;
    PORT
      LAYER M5 ;
        RECT  136.272 30.048 136.296 30.24 ;
    END
  END xb[153]
  PIN xb[154]
    DIRECTION OUTPUT ;
    USE SIGNAL ;
    PORT
      LAYER M3 ;
        RECT  136.584 30.096 136.602 30.24 ;
    END
  END xb[154]
  PIN xb[155]
    DIRECTION OUTPUT ;
    USE SIGNAL ;
    PORT
      LAYER M5 ;
        RECT  136.848 30.048 136.872 30.24 ;
    END
  END xb[155]
  PIN xb[156]
    DIRECTION OUTPUT ;
    USE SIGNAL ;
    PORT
      LAYER M3 ;
        RECT  137.16 30.096 137.178 30.24 ;
    END
  END xb[156]
  PIN xb[157]
    DIRECTION OUTPUT ;
    USE SIGNAL ;
    PORT
      LAYER M5 ;
        RECT  137.424 30.048 137.448 30.24 ;
    END
  END xb[157]
  PIN xb[158]
    DIRECTION OUTPUT ;
    USE SIGNAL ;
    PORT
      LAYER M3 ;
        RECT  137.736 30.096 137.754 30.24 ;
    END
  END xb[158]
  PIN xb[159]
    DIRECTION OUTPUT ;
    USE SIGNAL ;
    PORT
      LAYER M5 ;
        RECT  138 30.048 138.024 30.24 ;
    END
  END xb[159]
  PIN xb[15]
    DIRECTION OUTPUT ;
    USE SIGNAL ;
    PORT
      LAYER M5 ;
        RECT  96.816 30.048 96.84 30.24 ;
    END
  END xb[15]
  PIN xb[160]
    DIRECTION OUTPUT ;
    USE SIGNAL ;
    PORT
      LAYER M3 ;
        RECT  138.312 30.096 138.33 30.24 ;
    END
  END xb[160]
  PIN xb[161]
    DIRECTION OUTPUT ;
    USE SIGNAL ;
    PORT
      LAYER M5 ;
        RECT  138.576 30.048 138.6 30.24 ;
    END
  END xb[161]
  PIN xb[162]
    DIRECTION OUTPUT ;
    USE SIGNAL ;
    PORT
      LAYER M3 ;
        RECT  138.888 30.096 138.906 30.24 ;
    END
  END xb[162]
  PIN xb[163]
    DIRECTION OUTPUT ;
    USE SIGNAL ;
    PORT
      LAYER M5 ;
        RECT  139.152 30.048 139.176 30.24 ;
    END
  END xb[163]
  PIN xb[164]
    DIRECTION OUTPUT ;
    USE SIGNAL ;
    PORT
      LAYER M3 ;
        RECT  139.428 30.096 139.446 30.24 ;
    END
  END xb[164]
  PIN xb[165]
    DIRECTION OUTPUT ;
    USE SIGNAL ;
    PORT
      LAYER M5 ;
        RECT  139.728 30.048 139.752 30.24 ;
    END
  END xb[165]
  PIN xb[166]
    DIRECTION OUTPUT ;
    USE SIGNAL ;
    PORT
      LAYER M3 ;
        RECT  140.004 30.096 140.022 30.24 ;
    END
  END xb[166]
  PIN xb[167]
    DIRECTION OUTPUT ;
    USE SIGNAL ;
    PORT
      LAYER M5 ;
        RECT  140.304 30.048 140.328 30.24 ;
    END
  END xb[167]
  PIN xb[168]
    DIRECTION OUTPUT ;
    USE SIGNAL ;
    PORT
      LAYER M3 ;
        RECT  140.58 30.096 140.598 30.24 ;
    END
  END xb[168]
  PIN xb[169]
    DIRECTION OUTPUT ;
    USE SIGNAL ;
    PORT
      LAYER M5 ;
        RECT  140.88 30.048 140.904 30.24 ;
    END
  END xb[169]
  PIN xb[16]
    DIRECTION OUTPUT ;
    USE SIGNAL ;
    PORT
      LAYER M3 ;
        RECT  97.128 30.096 97.146 30.24 ;
    END
  END xb[16]
  PIN xb[170]
    DIRECTION OUTPUT ;
    USE SIGNAL ;
    PORT
      LAYER M3 ;
        RECT  141.156 30.096 141.174 30.24 ;
    END
  END xb[170]
  PIN xb[171]
    DIRECTION OUTPUT ;
    USE SIGNAL ;
    PORT
      LAYER M5 ;
        RECT  141.456 30.048 141.48 30.24 ;
    END
  END xb[171]
  PIN xb[172]
    DIRECTION OUTPUT ;
    USE SIGNAL ;
    PORT
      LAYER M3 ;
        RECT  141.732 30.096 141.75 30.24 ;
    END
  END xb[172]
  PIN xb[173]
    DIRECTION OUTPUT ;
    USE SIGNAL ;
    PORT
      LAYER M5 ;
        RECT  142.032 30.048 142.056 30.24 ;
    END
  END xb[173]
  PIN xb[174]
    DIRECTION OUTPUT ;
    USE SIGNAL ;
    PORT
      LAYER M3 ;
        RECT  142.308 30.096 142.326 30.24 ;
    END
  END xb[174]
  PIN xb[175]
    DIRECTION OUTPUT ;
    USE SIGNAL ;
    PORT
      LAYER M5 ;
        RECT  142.608 30.048 142.632 30.24 ;
    END
  END xb[175]
  PIN xb[176]
    DIRECTION OUTPUT ;
    USE SIGNAL ;
    PORT
      LAYER M3 ;
        RECT  142.884 30.096 142.902 30.24 ;
    END
  END xb[176]
  PIN xb[177]
    DIRECTION OUTPUT ;
    USE SIGNAL ;
    PORT
      LAYER M5 ;
        RECT  143.136 30.048 143.16 30.24 ;
    END
  END xb[177]
  PIN xb[178]
    DIRECTION OUTPUT ;
    USE SIGNAL ;
    PORT
      LAYER M3 ;
        RECT  143.46 30.096 143.478 30.24 ;
    END
  END xb[178]
  PIN xb[179]
    DIRECTION OUTPUT ;
    USE SIGNAL ;
    PORT
      LAYER M5 ;
        RECT  143.712 30.048 143.736 30.24 ;
    END
  END xb[179]
  PIN xb[17]
    DIRECTION OUTPUT ;
    USE SIGNAL ;
    PORT
      LAYER M5 ;
        RECT  97.392 30.048 97.416 30.24 ;
    END
  END xb[17]
  PIN xb[180]
    DIRECTION OUTPUT ;
    USE SIGNAL ;
    PORT
      LAYER M3 ;
        RECT  144.036 30.096 144.054 30.24 ;
    END
  END xb[180]
  PIN xb[181]
    DIRECTION OUTPUT ;
    USE SIGNAL ;
    PORT
      LAYER M5 ;
        RECT  144.288 30.048 144.312 30.24 ;
    END
  END xb[181]
  PIN xb[182]
    DIRECTION OUTPUT ;
    USE SIGNAL ;
    PORT
      LAYER M3 ;
        RECT  144.576 30.096 144.594 30.24 ;
    END
  END xb[182]
  PIN xb[183]
    DIRECTION OUTPUT ;
    USE SIGNAL ;
    PORT
      LAYER M5 ;
        RECT  144.864 30.048 144.888 30.24 ;
    END
  END xb[183]
  PIN xb[184]
    DIRECTION OUTPUT ;
    USE SIGNAL ;
    PORT
      LAYER M3 ;
        RECT  145.152 30.096 145.17 30.24 ;
    END
  END xb[184]
  PIN xb[185]
    DIRECTION OUTPUT ;
    USE SIGNAL ;
    PORT
      LAYER M5 ;
        RECT  145.44 30.048 145.464 30.24 ;
    END
  END xb[185]
  PIN xb[186]
    DIRECTION OUTPUT ;
    USE SIGNAL ;
    PORT
      LAYER M3 ;
        RECT  145.728 30.096 145.746 30.24 ;
    END
  END xb[186]
  PIN xb[187]
    DIRECTION OUTPUT ;
    USE SIGNAL ;
    PORT
      LAYER M5 ;
        RECT  146.016 30.048 146.04 30.24 ;
    END
  END xb[187]
  PIN xb[188]
    DIRECTION OUTPUT ;
    USE SIGNAL ;
    PORT
      LAYER M3 ;
        RECT  146.304 30.096 146.322 30.24 ;
    END
  END xb[188]
  PIN xb[189]
    DIRECTION OUTPUT ;
    USE SIGNAL ;
    PORT
      LAYER M5 ;
        RECT  146.592 30.048 146.616 30.24 ;
    END
  END xb[189]
  PIN xb[18]
    DIRECTION OUTPUT ;
    USE SIGNAL ;
    PORT
      LAYER M3 ;
        RECT  97.704 30.096 97.722 30.24 ;
    END
  END xb[18]
  PIN xb[190]
    DIRECTION OUTPUT ;
    USE SIGNAL ;
    PORT
      LAYER M3 ;
        RECT  146.88 30.096 146.898 30.24 ;
    END
  END xb[190]
  PIN xb[191]
    DIRECTION OUTPUT ;
    USE SIGNAL ;
    PORT
      LAYER M5 ;
        RECT  147.168 30.048 147.192 30.24 ;
    END
  END xb[191]
  PIN xb[192]
    DIRECTION OUTPUT ;
    USE SIGNAL ;
    PORT
      LAYER M3 ;
        RECT  147.456 30.096 147.474 30.24 ;
    END
  END xb[192]
  PIN xb[193]
    DIRECTION OUTPUT ;
    USE SIGNAL ;
    PORT
      LAYER M5 ;
        RECT  147.744 30.048 147.768 30.24 ;
    END
  END xb[193]
  PIN xb[194]
    DIRECTION OUTPUT ;
    USE SIGNAL ;
    PORT
      LAYER M3 ;
        RECT  148.032 30.096 148.05 30.24 ;
    END
  END xb[194]
  PIN xb[195]
    DIRECTION OUTPUT ;
    USE SIGNAL ;
    PORT
      LAYER M5 ;
        RECT  148.32 30.048 148.344 30.24 ;
    END
  END xb[195]
  PIN xb[196]
    DIRECTION OUTPUT ;
    USE SIGNAL ;
    PORT
      LAYER M3 ;
        RECT  148.608 30.096 148.626 30.24 ;
    END
  END xb[196]
  PIN xb[197]
    DIRECTION OUTPUT ;
    USE SIGNAL ;
    PORT
      LAYER M5 ;
        RECT  148.896 30.048 148.92 30.24 ;
    END
  END xb[197]
  PIN xb[198]
    DIRECTION OUTPUT ;
    USE SIGNAL ;
    PORT
      LAYER M3 ;
        RECT  149.184 30.096 149.202 30.24 ;
    END
  END xb[198]
  PIN xb[199]
    DIRECTION OUTPUT ;
    USE SIGNAL ;
    PORT
      LAYER M5 ;
        RECT  149.472 30.048 149.496 30.24 ;
    END
  END xb[199]
  PIN xb[19]
    DIRECTION OUTPUT ;
    USE SIGNAL ;
    PORT
      LAYER M5 ;
        RECT  97.968 30.048 97.992 30.24 ;
    END
  END xb[19]
  PIN xb[1]
    DIRECTION OUTPUT ;
    USE SIGNAL ;
    PORT
      LAYER M5 ;
        RECT  92.832 30.048 92.856 30.24 ;
    END
  END xb[1]
  PIN xb[200]
    DIRECTION OUTPUT ;
    USE SIGNAL ;
    PORT
      LAYER M3 ;
        RECT  149.724 30.096 149.742 30.24 ;
    END
  END xb[200]
  PIN xb[201]
    DIRECTION OUTPUT ;
    USE SIGNAL ;
    PORT
      LAYER M5 ;
        RECT  150 30.048 150.024 30.24 ;
    END
  END xb[201]
  PIN xb[202]
    DIRECTION OUTPUT ;
    USE SIGNAL ;
    PORT
      LAYER M3 ;
        RECT  150.3 30.096 150.318 30.24 ;
    END
  END xb[202]
  PIN xb[203]
    DIRECTION OUTPUT ;
    USE SIGNAL ;
    PORT
      LAYER M5 ;
        RECT  150.576 30.048 150.6 30.24 ;
    END
  END xb[203]
  PIN xb[204]
    DIRECTION OUTPUT ;
    USE SIGNAL ;
    PORT
      LAYER M3 ;
        RECT  150.876 30.096 150.894 30.24 ;
    END
  END xb[204]
  PIN xb[205]
    DIRECTION OUTPUT ;
    USE SIGNAL ;
    PORT
      LAYER M5 ;
        RECT  151.152 30.048 151.176 30.24 ;
    END
  END xb[205]
  PIN xb[206]
    DIRECTION OUTPUT ;
    USE SIGNAL ;
    PORT
      LAYER M3 ;
        RECT  151.452 30.096 151.47 30.24 ;
    END
  END xb[206]
  PIN xb[207]
    DIRECTION OUTPUT ;
    USE SIGNAL ;
    PORT
      LAYER M5 ;
        RECT  151.728 30.048 151.752 30.24 ;
    END
  END xb[207]
  PIN xb[208]
    DIRECTION OUTPUT ;
    USE SIGNAL ;
    PORT
      LAYER M3 ;
        RECT  152.028 30.096 152.046 30.24 ;
    END
  END xb[208]
  PIN xb[209]
    DIRECTION OUTPUT ;
    USE SIGNAL ;
    PORT
      LAYER M5 ;
        RECT  152.304 30.048 152.328 30.24 ;
    END
  END xb[209]
  PIN xb[20]
    DIRECTION OUTPUT ;
    USE SIGNAL ;
    PORT
      LAYER M3 ;
        RECT  98.244 30.096 98.262 30.24 ;
    END
  END xb[20]
  PIN xb[210]
    DIRECTION OUTPUT ;
    USE SIGNAL ;
    PORT
      LAYER M3 ;
        RECT  152.604 30.096 152.622 30.24 ;
    END
  END xb[210]
  PIN xb[211]
    DIRECTION OUTPUT ;
    USE SIGNAL ;
    PORT
      LAYER M5 ;
        RECT  152.88 30.048 152.904 30.24 ;
    END
  END xb[211]
  PIN xb[212]
    DIRECTION OUTPUT ;
    USE SIGNAL ;
    PORT
      LAYER M3 ;
        RECT  153.18 30.096 153.198 30.24 ;
    END
  END xb[212]
  PIN xb[213]
    DIRECTION OUTPUT ;
    USE SIGNAL ;
    PORT
      LAYER M5 ;
        RECT  153.456 30.048 153.48 30.24 ;
    END
  END xb[213]
  PIN xb[214]
    DIRECTION OUTPUT ;
    USE SIGNAL ;
    PORT
      LAYER M3 ;
        RECT  153.756 30.096 153.774 30.24 ;
    END
  END xb[214]
  PIN xb[215]
    DIRECTION OUTPUT ;
    USE SIGNAL ;
    PORT
      LAYER M5 ;
        RECT  154.032 30.048 154.056 30.24 ;
    END
  END xb[215]
  PIN xb[216]
    DIRECTION OUTPUT ;
    USE SIGNAL ;
    PORT
      LAYER M3 ;
        RECT  154.332 30.096 154.35 30.24 ;
    END
  END xb[216]
  PIN xb[217]
    DIRECTION OUTPUT ;
    USE SIGNAL ;
    PORT
      LAYER M5 ;
        RECT  154.608 30.048 154.632 30.24 ;
    END
  END xb[217]
  PIN xb[218]
    DIRECTION OUTPUT ;
    USE SIGNAL ;
    PORT
      LAYER M3 ;
        RECT  154.872 30.096 154.89 30.24 ;
    END
  END xb[218]
  PIN xb[219]
    DIRECTION OUTPUT ;
    USE SIGNAL ;
    PORT
      LAYER M5 ;
        RECT  155.184 30.048 155.208 30.24 ;
    END
  END xb[219]
  PIN xb[21]
    DIRECTION OUTPUT ;
    USE SIGNAL ;
    PORT
      LAYER M5 ;
        RECT  98.544 30.048 98.568 30.24 ;
    END
  END xb[21]
  PIN xb[220]
    DIRECTION OUTPUT ;
    USE SIGNAL ;
    PORT
      LAYER M3 ;
        RECT  155.448 30.096 155.466 30.24 ;
    END
  END xb[220]
  PIN xb[221]
    DIRECTION OUTPUT ;
    USE SIGNAL ;
    PORT
      LAYER M5 ;
        RECT  155.76 30.048 155.784 30.24 ;
    END
  END xb[221]
  PIN xb[222]
    DIRECTION OUTPUT ;
    USE SIGNAL ;
    PORT
      LAYER M3 ;
        RECT  156.024 30.096 156.042 30.24 ;
    END
  END xb[222]
  PIN xb[223]
    DIRECTION OUTPUT ;
    USE SIGNAL ;
    PORT
      LAYER M5 ;
        RECT  156.336 30.048 156.36 30.24 ;
    END
  END xb[223]
  PIN xb[224]
    DIRECTION OUTPUT ;
    USE SIGNAL ;
    PORT
      LAYER M3 ;
        RECT  156.6 30.096 156.618 30.24 ;
    END
  END xb[224]
  PIN xb[225]
    DIRECTION OUTPUT ;
    USE SIGNAL ;
    PORT
      LAYER M5 ;
        RECT  156.864 30.048 156.888 30.24 ;
    END
  END xb[225]
  PIN xb[226]
    DIRECTION OUTPUT ;
    USE SIGNAL ;
    PORT
      LAYER M3 ;
        RECT  157.176 30.096 157.194 30.24 ;
    END
  END xb[226]
  PIN xb[227]
    DIRECTION OUTPUT ;
    USE SIGNAL ;
    PORT
      LAYER M5 ;
        RECT  157.44 30.048 157.464 30.24 ;
    END
  END xb[227]
  PIN xb[228]
    DIRECTION OUTPUT ;
    USE SIGNAL ;
    PORT
      LAYER M3 ;
        RECT  157.752 30.096 157.77 30.24 ;
    END
  END xb[228]
  PIN xb[229]
    DIRECTION OUTPUT ;
    USE SIGNAL ;
    PORT
      LAYER M5 ;
        RECT  158.016 30.048 158.04 30.24 ;
    END
  END xb[229]
  PIN xb[22]
    DIRECTION OUTPUT ;
    USE SIGNAL ;
    PORT
      LAYER M3 ;
        RECT  98.82 30.096 98.838 30.24 ;
    END
  END xb[22]
  PIN xb[230]
    DIRECTION OUTPUT ;
    USE SIGNAL ;
    PORT
      LAYER M3 ;
        RECT  158.328 30.096 158.346 30.24 ;
    END
  END xb[230]
  PIN xb[231]
    DIRECTION OUTPUT ;
    USE SIGNAL ;
    PORT
      LAYER M5 ;
        RECT  158.592 30.048 158.616 30.24 ;
    END
  END xb[231]
  PIN xb[232]
    DIRECTION OUTPUT ;
    USE SIGNAL ;
    PORT
      LAYER M3 ;
        RECT  158.904 30.096 158.922 30.24 ;
    END
  END xb[232]
  PIN xb[233]
    DIRECTION OUTPUT ;
    USE SIGNAL ;
    PORT
      LAYER M5 ;
        RECT  159.168 30.048 159.192 30.24 ;
    END
  END xb[233]
  PIN xb[234]
    DIRECTION OUTPUT ;
    USE SIGNAL ;
    PORT
      LAYER M3 ;
        RECT  159.48 30.096 159.498 30.24 ;
    END
  END xb[234]
  PIN xb[235]
    DIRECTION OUTPUT ;
    USE SIGNAL ;
    PORT
      LAYER M5 ;
        RECT  159.744 30.048 159.768 30.24 ;
    END
  END xb[235]
  PIN xb[236]
    DIRECTION OUTPUT ;
    USE SIGNAL ;
    PORT
      LAYER M3 ;
        RECT  160.02 30.096 160.038 30.24 ;
    END
  END xb[236]
  PIN xb[237]
    DIRECTION OUTPUT ;
    USE SIGNAL ;
    PORT
      LAYER M5 ;
        RECT  160.32 30.048 160.344 30.24 ;
    END
  END xb[237]
  PIN xb[238]
    DIRECTION OUTPUT ;
    USE SIGNAL ;
    PORT
      LAYER M3 ;
        RECT  160.596 30.096 160.614 30.24 ;
    END
  END xb[238]
  PIN xb[239]
    DIRECTION OUTPUT ;
    USE SIGNAL ;
    PORT
      LAYER M5 ;
        RECT  160.896 30.048 160.92 30.24 ;
    END
  END xb[239]
  PIN xb[23]
    DIRECTION OUTPUT ;
    USE SIGNAL ;
    PORT
      LAYER M5 ;
        RECT  99.12 30.048 99.144 30.24 ;
    END
  END xb[23]
  PIN xb[240]
    DIRECTION OUTPUT ;
    USE SIGNAL ;
    PORT
      LAYER M3 ;
        RECT  161.172 30.096 161.19 30.24 ;
    END
  END xb[240]
  PIN xb[241]
    DIRECTION OUTPUT ;
    USE SIGNAL ;
    PORT
      LAYER M5 ;
        RECT  161.472 30.048 161.496 30.24 ;
    END
  END xb[241]
  PIN xb[242]
    DIRECTION OUTPUT ;
    USE SIGNAL ;
    PORT
      LAYER M3 ;
        RECT  161.748 30.096 161.766 30.24 ;
    END
  END xb[242]
  PIN xb[243]
    DIRECTION OUTPUT ;
    USE SIGNAL ;
    PORT
      LAYER M5 ;
        RECT  162.048 30.048 162.072 30.24 ;
    END
  END xb[243]
  PIN xb[244]
    DIRECTION OUTPUT ;
    USE SIGNAL ;
    PORT
      LAYER M3 ;
        RECT  162.324 30.096 162.342 30.24 ;
    END
  END xb[244]
  PIN xb[245]
    DIRECTION OUTPUT ;
    USE SIGNAL ;
    PORT
      LAYER M5 ;
        RECT  162.624 30.048 162.648 30.24 ;
    END
  END xb[245]
  PIN xb[246]
    DIRECTION OUTPUT ;
    USE SIGNAL ;
    PORT
      LAYER M3 ;
        RECT  162.9 30.096 162.918 30.24 ;
    END
  END xb[246]
  PIN xb[247]
    DIRECTION OUTPUT ;
    USE SIGNAL ;
    PORT
      LAYER M5 ;
        RECT  163.2 30.048 163.224 30.24 ;
    END
  END xb[247]
  PIN xb[248]
    DIRECTION OUTPUT ;
    USE SIGNAL ;
    PORT
      LAYER M3 ;
        RECT  163.476 30.096 163.494 30.24 ;
    END
  END xb[248]
  PIN xb[249]
    DIRECTION OUTPUT ;
    USE SIGNAL ;
    PORT
      LAYER M5 ;
        RECT  163.728 30.048 163.752 30.24 ;
    END
  END xb[249]
  PIN xb[24]
    DIRECTION OUTPUT ;
    USE SIGNAL ;
    PORT
      LAYER M3 ;
        RECT  99.396 30.096 99.414 30.24 ;
    END
  END xb[24]
  PIN xb[250]
    DIRECTION OUTPUT ;
    USE SIGNAL ;
    PORT
      LAYER M3 ;
        RECT  164.052 30.096 164.07 30.24 ;
    END
  END xb[250]
  PIN xb[251]
    DIRECTION OUTPUT ;
    USE SIGNAL ;
    PORT
      LAYER M5 ;
        RECT  164.304 30.048 164.328 30.24 ;
    END
  END xb[251]
  PIN xb[252]
    DIRECTION OUTPUT ;
    USE SIGNAL ;
    PORT
      LAYER M3 ;
        RECT  164.628 30.096 164.646 30.24 ;
    END
  END xb[252]
  PIN xb[253]
    DIRECTION OUTPUT ;
    USE SIGNAL ;
    PORT
      LAYER M5 ;
        RECT  164.88 30.048 164.904 30.24 ;
    END
  END xb[253]
  PIN xb[254]
    DIRECTION OUTPUT ;
    USE SIGNAL ;
    PORT
      LAYER M3 ;
        RECT  165.168 30.096 165.186 30.24 ;
    END
  END xb[254]
  PIN xb[255]
    DIRECTION OUTPUT ;
    USE SIGNAL ;
    PORT
      LAYER M5 ;
        RECT  165.456 30.048 165.48 30.24 ;
    END
  END xb[255]
  PIN xb[256]
    DIRECTION OUTPUT ;
    USE SIGNAL ;
    PORT
      LAYER M3 ;
        RECT  165.744 30.096 165.762 30.24 ;
    END
  END xb[256]
  PIN xb[257]
    DIRECTION OUTPUT ;
    USE SIGNAL ;
    PORT
      LAYER M5 ;
        RECT  166.032 30.048 166.056 30.24 ;
    END
  END xb[257]
  PIN xb[258]
    DIRECTION OUTPUT ;
    USE SIGNAL ;
    PORT
      LAYER M3 ;
        RECT  166.32 30.096 166.338 30.24 ;
    END
  END xb[258]
  PIN xb[259]
    DIRECTION OUTPUT ;
    USE SIGNAL ;
    PORT
      LAYER M5 ;
        RECT  166.608 30.048 166.632 30.24 ;
    END
  END xb[259]
  PIN xb[25]
    DIRECTION OUTPUT ;
    USE SIGNAL ;
    PORT
      LAYER M5 ;
        RECT  99.696 30.048 99.72 30.24 ;
    END
  END xb[25]
  PIN xb[260]
    DIRECTION OUTPUT ;
    USE SIGNAL ;
    PORT
      LAYER M3 ;
        RECT  166.896 30.096 166.914 30.24 ;
    END
  END xb[260]
  PIN xb[261]
    DIRECTION OUTPUT ;
    USE SIGNAL ;
    PORT
      LAYER M5 ;
        RECT  167.184 30.048 167.208 30.24 ;
    END
  END xb[261]
  PIN xb[262]
    DIRECTION OUTPUT ;
    USE SIGNAL ;
    PORT
      LAYER M3 ;
        RECT  167.472 30.096 167.49 30.24 ;
    END
  END xb[262]
  PIN xb[263]
    DIRECTION OUTPUT ;
    USE SIGNAL ;
    PORT
      LAYER M5 ;
        RECT  167.76 30.048 167.784 30.24 ;
    END
  END xb[263]
  PIN xb[264]
    DIRECTION OUTPUT ;
    USE SIGNAL ;
    PORT
      LAYER M3 ;
        RECT  168.048 30.096 168.066 30.24 ;
    END
  END xb[264]
  PIN xb[265]
    DIRECTION OUTPUT ;
    USE SIGNAL ;
    PORT
      LAYER M5 ;
        RECT  168.336 30.048 168.36 30.24 ;
    END
  END xb[265]
  PIN xb[26]
    DIRECTION OUTPUT ;
    USE SIGNAL ;
    PORT
      LAYER M3 ;
        RECT  99.972 30.096 99.99 30.24 ;
    END
  END xb[26]
  PIN xb[27]
    DIRECTION OUTPUT ;
    USE SIGNAL ;
    PORT
      LAYER M5 ;
        RECT  100.272 30.048 100.296 30.24 ;
    END
  END xb[27]
  PIN xb[28]
    DIRECTION OUTPUT ;
    USE SIGNAL ;
    PORT
      LAYER M3 ;
        RECT  100.548 30.096 100.566 30.24 ;
    END
  END xb[28]
  PIN xb[29]
    DIRECTION OUTPUT ;
    USE SIGNAL ;
    PORT
      LAYER M5 ;
        RECT  100.848 30.048 100.872 30.24 ;
    END
  END xb[29]
  PIN xb[2]
    DIRECTION OUTPUT ;
    USE SIGNAL ;
    PORT
      LAYER M3 ;
        RECT  93.096 30.096 93.114 30.24 ;
    END
  END xb[2]
  PIN xb[30]
    DIRECTION OUTPUT ;
    USE SIGNAL ;
    PORT
      LAYER M3 ;
        RECT  101.124 30.096 101.142 30.24 ;
    END
  END xb[30]
  PIN xb[31]
    DIRECTION OUTPUT ;
    USE SIGNAL ;
    PORT
      LAYER M5 ;
        RECT  101.424 30.048 101.448 30.24 ;
    END
  END xb[31]
  PIN xb[32]
    DIRECTION OUTPUT ;
    USE SIGNAL ;
    PORT
      LAYER M3 ;
        RECT  101.7 30.096 101.718 30.24 ;
    END
  END xb[32]
  PIN xb[33]
    DIRECTION OUTPUT ;
    USE SIGNAL ;
    PORT
      LAYER M5 ;
        RECT  101.952 30.048 101.976 30.24 ;
    END
  END xb[33]
  PIN xb[34]
    DIRECTION OUTPUT ;
    USE SIGNAL ;
    PORT
      LAYER M3 ;
        RECT  102.276 30.096 102.294 30.24 ;
    END
  END xb[34]
  PIN xb[35]
    DIRECTION OUTPUT ;
    USE SIGNAL ;
    PORT
      LAYER M5 ;
        RECT  102.528 30.048 102.552 30.24 ;
    END
  END xb[35]
  PIN xb[36]
    DIRECTION OUTPUT ;
    USE SIGNAL ;
    PORT
      LAYER M3 ;
        RECT  102.852 30.096 102.87 30.24 ;
    END
  END xb[36]
  PIN xb[37]
    DIRECTION OUTPUT ;
    USE SIGNAL ;
    PORT
      LAYER M5 ;
        RECT  103.104 30.048 103.128 30.24 ;
    END
  END xb[37]
  PIN xb[38]
    DIRECTION OUTPUT ;
    USE SIGNAL ;
    PORT
      LAYER M3 ;
        RECT  103.392 30.096 103.41 30.24 ;
    END
  END xb[38]
  PIN xb[39]
    DIRECTION OUTPUT ;
    USE SIGNAL ;
    PORT
      LAYER M5 ;
        RECT  103.68 30.048 103.704 30.24 ;
    END
  END xb[39]
  PIN xb[3]
    DIRECTION OUTPUT ;
    USE SIGNAL ;
    PORT
      LAYER M5 ;
        RECT  93.408 30.048 93.432 30.24 ;
    END
  END xb[3]
  PIN xb[40]
    DIRECTION OUTPUT ;
    USE SIGNAL ;
    PORT
      LAYER M3 ;
        RECT  103.968 30.096 103.986 30.24 ;
    END
  END xb[40]
  PIN xb[41]
    DIRECTION OUTPUT ;
    USE SIGNAL ;
    PORT
      LAYER M5 ;
        RECT  104.256 30.048 104.28 30.24 ;
    END
  END xb[41]
  PIN xb[42]
    DIRECTION OUTPUT ;
    USE SIGNAL ;
    PORT
      LAYER M3 ;
        RECT  104.544 30.096 104.562 30.24 ;
    END
  END xb[42]
  PIN xb[43]
    DIRECTION OUTPUT ;
    USE SIGNAL ;
    PORT
      LAYER M5 ;
        RECT  104.832 30.048 104.856 30.24 ;
    END
  END xb[43]
  PIN xb[44]
    DIRECTION OUTPUT ;
    USE SIGNAL ;
    PORT
      LAYER M3 ;
        RECT  105.12 30.096 105.138 30.24 ;
    END
  END xb[44]
  PIN xb[45]
    DIRECTION OUTPUT ;
    USE SIGNAL ;
    PORT
      LAYER M5 ;
        RECT  105.408 30.048 105.432 30.24 ;
    END
  END xb[45]
  PIN xb[46]
    DIRECTION OUTPUT ;
    USE SIGNAL ;
    PORT
      LAYER M3 ;
        RECT  105.696 30.096 105.714 30.24 ;
    END
  END xb[46]
  PIN xb[47]
    DIRECTION OUTPUT ;
    USE SIGNAL ;
    PORT
      LAYER M5 ;
        RECT  105.984 30.048 106.008 30.24 ;
    END
  END xb[47]
  PIN xb[48]
    DIRECTION OUTPUT ;
    USE SIGNAL ;
    PORT
      LAYER M3 ;
        RECT  106.272 30.096 106.29 30.24 ;
    END
  END xb[48]
  PIN xb[49]
    DIRECTION OUTPUT ;
    USE SIGNAL ;
    PORT
      LAYER M5 ;
        RECT  106.56 30.048 106.584 30.24 ;
    END
  END xb[49]
  PIN xb[4]
    DIRECTION OUTPUT ;
    USE SIGNAL ;
    PORT
      LAYER M3 ;
        RECT  93.672 30.096 93.69 30.24 ;
    END
  END xb[4]
  PIN xb[50]
    DIRECTION OUTPUT ;
    USE SIGNAL ;
    PORT
      LAYER M3 ;
        RECT  106.848 30.096 106.866 30.24 ;
    END
  END xb[50]
  PIN xb[51]
    DIRECTION OUTPUT ;
    USE SIGNAL ;
    PORT
      LAYER M5 ;
        RECT  107.136 30.048 107.16 30.24 ;
    END
  END xb[51]
  PIN xb[52]
    DIRECTION OUTPUT ;
    USE SIGNAL ;
    PORT
      LAYER M3 ;
        RECT  107.424 30.096 107.442 30.24 ;
    END
  END xb[52]
  PIN xb[53]
    DIRECTION OUTPUT ;
    USE SIGNAL ;
    PORT
      LAYER M5 ;
        RECT  107.712 30.048 107.736 30.24 ;
    END
  END xb[53]
  PIN xb[54]
    DIRECTION OUTPUT ;
    USE SIGNAL ;
    PORT
      LAYER M3 ;
        RECT  108 30.096 108.018 30.24 ;
    END
  END xb[54]
  PIN xb[55]
    DIRECTION OUTPUT ;
    USE SIGNAL ;
    PORT
      LAYER M5 ;
        RECT  108.288 30.048 108.312 30.24 ;
    END
  END xb[55]
  PIN xb[56]
    DIRECTION OUTPUT ;
    USE SIGNAL ;
    PORT
      LAYER M3 ;
        RECT  108.54 30.096 108.558 30.24 ;
    END
  END xb[56]
  PIN xb[57]
    DIRECTION OUTPUT ;
    USE SIGNAL ;
    PORT
      LAYER M5 ;
        RECT  108.816 30.048 108.84 30.24 ;
    END
  END xb[57]
  PIN xb[58]
    DIRECTION OUTPUT ;
    USE SIGNAL ;
    PORT
      LAYER M3 ;
        RECT  109.116 30.096 109.134 30.24 ;
    END
  END xb[58]
  PIN xb[59]
    DIRECTION OUTPUT ;
    USE SIGNAL ;
    PORT
      LAYER M5 ;
        RECT  109.392 30.048 109.416 30.24 ;
    END
  END xb[59]
  PIN xb[5]
    DIRECTION OUTPUT ;
    USE SIGNAL ;
    PORT
      LAYER M5 ;
        RECT  93.984 30.048 94.008 30.24 ;
    END
  END xb[5]
  PIN xb[60]
    DIRECTION OUTPUT ;
    USE SIGNAL ;
    PORT
      LAYER M3 ;
        RECT  109.692 30.096 109.71 30.24 ;
    END
  END xb[60]
  PIN xb[61]
    DIRECTION OUTPUT ;
    USE SIGNAL ;
    PORT
      LAYER M5 ;
        RECT  109.968 30.048 109.992 30.24 ;
    END
  END xb[61]
  PIN xb[62]
    DIRECTION OUTPUT ;
    USE SIGNAL ;
    PORT
      LAYER M3 ;
        RECT  110.268 30.096 110.286 30.24 ;
    END
  END xb[62]
  PIN xb[63]
    DIRECTION OUTPUT ;
    USE SIGNAL ;
    PORT
      LAYER M5 ;
        RECT  110.544 30.048 110.568 30.24 ;
    END
  END xb[63]
  PIN xb[64]
    DIRECTION OUTPUT ;
    USE SIGNAL ;
    PORT
      LAYER M3 ;
        RECT  110.844 30.096 110.862 30.24 ;
    END
  END xb[64]
  PIN xb[65]
    DIRECTION OUTPUT ;
    USE SIGNAL ;
    PORT
      LAYER M5 ;
        RECT  111.12 30.048 111.144 30.24 ;
    END
  END xb[65]
  PIN xb[66]
    DIRECTION OUTPUT ;
    USE SIGNAL ;
    PORT
      LAYER M3 ;
        RECT  111.42 30.096 111.438 30.24 ;
    END
  END xb[66]
  PIN xb[67]
    DIRECTION OUTPUT ;
    USE SIGNAL ;
    PORT
      LAYER M5 ;
        RECT  111.696 30.048 111.72 30.24 ;
    END
  END xb[67]
  PIN xb[68]
    DIRECTION OUTPUT ;
    USE SIGNAL ;
    PORT
      LAYER M3 ;
        RECT  111.996 30.096 112.014 30.24 ;
    END
  END xb[68]
  PIN xb[69]
    DIRECTION OUTPUT ;
    USE SIGNAL ;
    PORT
      LAYER M5 ;
        RECT  112.272 30.048 112.296 30.24 ;
    END
  END xb[69]
  PIN xb[6]
    DIRECTION OUTPUT ;
    USE SIGNAL ;
    PORT
      LAYER M3 ;
        RECT  94.248 30.096 94.266 30.24 ;
    END
  END xb[6]
  PIN xb[70]
    DIRECTION OUTPUT ;
    USE SIGNAL ;
    PORT
      LAYER M3 ;
        RECT  112.572 30.096 112.59 30.24 ;
    END
  END xb[70]
  PIN xb[71]
    DIRECTION OUTPUT ;
    USE SIGNAL ;
    PORT
      LAYER M5 ;
        RECT  112.848 30.048 112.872 30.24 ;
    END
  END xb[71]
  PIN xb[72]
    DIRECTION OUTPUT ;
    USE SIGNAL ;
    PORT
      LAYER M3 ;
        RECT  113.148 30.096 113.166 30.24 ;
    END
  END xb[72]
  PIN xb[73]
    DIRECTION OUTPUT ;
    USE SIGNAL ;
    PORT
      LAYER M5 ;
        RECT  113.424 30.048 113.448 30.24 ;
    END
  END xb[73]
  PIN xb[74]
    DIRECTION OUTPUT ;
    USE SIGNAL ;
    PORT
      LAYER M3 ;
        RECT  113.688 30.096 113.706 30.24 ;
    END
  END xb[74]
  PIN xb[75]
    DIRECTION OUTPUT ;
    USE SIGNAL ;
    PORT
      LAYER M5 ;
        RECT  114 30.048 114.024 30.24 ;
    END
  END xb[75]
  PIN xb[76]
    DIRECTION OUTPUT ;
    USE SIGNAL ;
    PORT
      LAYER M3 ;
        RECT  114.264 30.096 114.282 30.24 ;
    END
  END xb[76]
  PIN xb[77]
    DIRECTION OUTPUT ;
    USE SIGNAL ;
    PORT
      LAYER M5 ;
        RECT  114.576 30.048 114.6 30.24 ;
    END
  END xb[77]
  PIN xb[78]
    DIRECTION OUTPUT ;
    USE SIGNAL ;
    PORT
      LAYER M3 ;
        RECT  114.84 30.096 114.858 30.24 ;
    END
  END xb[78]
  PIN xb[79]
    DIRECTION OUTPUT ;
    USE SIGNAL ;
    PORT
      LAYER M5 ;
        RECT  115.152 30.048 115.176 30.24 ;
    END
  END xb[79]
  PIN xb[7]
    DIRECTION OUTPUT ;
    USE SIGNAL ;
    PORT
      LAYER M5 ;
        RECT  94.56 30.048 94.584 30.24 ;
    END
  END xb[7]
  PIN xb[80]
    DIRECTION OUTPUT ;
    USE SIGNAL ;
    PORT
      LAYER M3 ;
        RECT  115.416 30.096 115.434 30.24 ;
    END
  END xb[80]
  PIN xb[81]
    DIRECTION OUTPUT ;
    USE SIGNAL ;
    PORT
      LAYER M5 ;
        RECT  115.68 30.048 115.704 30.24 ;
    END
  END xb[81]
  PIN xb[82]
    DIRECTION OUTPUT ;
    USE SIGNAL ;
    PORT
      LAYER M3 ;
        RECT  115.992 30.096 116.01 30.24 ;
    END
  END xb[82]
  PIN xb[83]
    DIRECTION OUTPUT ;
    USE SIGNAL ;
    PORT
      LAYER M5 ;
        RECT  116.256 30.048 116.28 30.24 ;
    END
  END xb[83]
  PIN xb[84]
    DIRECTION OUTPUT ;
    USE SIGNAL ;
    PORT
      LAYER M3 ;
        RECT  116.568 30.096 116.586 30.24 ;
    END
  END xb[84]
  PIN xb[85]
    DIRECTION OUTPUT ;
    USE SIGNAL ;
    PORT
      LAYER M5 ;
        RECT  116.832 30.048 116.856 30.24 ;
    END
  END xb[85]
  PIN xb[86]
    DIRECTION OUTPUT ;
    USE SIGNAL ;
    PORT
      LAYER M3 ;
        RECT  117.144 30.096 117.162 30.24 ;
    END
  END xb[86]
  PIN xb[87]
    DIRECTION OUTPUT ;
    USE SIGNAL ;
    PORT
      LAYER M5 ;
        RECT  117.408 30.048 117.432 30.24 ;
    END
  END xb[87]
  PIN xb[88]
    DIRECTION OUTPUT ;
    USE SIGNAL ;
    PORT
      LAYER M3 ;
        RECT  117.72 30.096 117.738 30.24 ;
    END
  END xb[88]
  PIN xb[89]
    DIRECTION OUTPUT ;
    USE SIGNAL ;
    PORT
      LAYER M5 ;
        RECT  117.984 30.048 118.008 30.24 ;
    END
  END xb[89]
  PIN xb[8]
    DIRECTION OUTPUT ;
    USE SIGNAL ;
    PORT
      LAYER M3 ;
        RECT  94.824 30.096 94.842 30.24 ;
    END
  END xb[8]
  PIN xb[90]
    DIRECTION OUTPUT ;
    USE SIGNAL ;
    PORT
      LAYER M3 ;
        RECT  118.296 30.096 118.314 30.24 ;
    END
  END xb[90]
  PIN xb[91]
    DIRECTION OUTPUT ;
    USE SIGNAL ;
    PORT
      LAYER M5 ;
        RECT  118.56 30.048 118.584 30.24 ;
    END
  END xb[91]
  PIN xb[92]
    DIRECTION OUTPUT ;
    USE SIGNAL ;
    PORT
      LAYER M3 ;
        RECT  118.836 30.096 118.854 30.24 ;
    END
  END xb[92]
  PIN xb[93]
    DIRECTION OUTPUT ;
    USE SIGNAL ;
    PORT
      LAYER M5 ;
        RECT  119.136 30.048 119.16 30.24 ;
    END
  END xb[93]
  PIN xb[94]
    DIRECTION OUTPUT ;
    USE SIGNAL ;
    PORT
      LAYER M3 ;
        RECT  119.412 30.096 119.43 30.24 ;
    END
  END xb[94]
  PIN xb[95]
    DIRECTION OUTPUT ;
    USE SIGNAL ;
    PORT
      LAYER M5 ;
        RECT  119.712 30.048 119.736 30.24 ;
    END
  END xb[95]
  PIN xb[96]
    DIRECTION OUTPUT ;
    USE SIGNAL ;
    PORT
      LAYER M3 ;
        RECT  119.988 30.096 120.006 30.24 ;
    END
  END xb[96]
  PIN xb[97]
    DIRECTION OUTPUT ;
    USE SIGNAL ;
    PORT
      LAYER M5 ;
        RECT  120.288 30.048 120.312 30.24 ;
    END
  END xb[97]
  PIN xb[98]
    DIRECTION OUTPUT ;
    USE SIGNAL ;
    PORT
      LAYER M3 ;
        RECT  120.564 30.096 120.582 30.24 ;
    END
  END xb[98]
  PIN xb[99]
    DIRECTION OUTPUT ;
    USE SIGNAL ;
    PORT
      LAYER M5 ;
        RECT  120.864 30.048 120.888 30.24 ;
    END
  END xb[99]
  PIN xb[9]
    DIRECTION OUTPUT ;
    USE SIGNAL ;
    PORT
      LAYER M5 ;
        RECT  95.088 30.048 95.112 30.24 ;
    END
  END xb[9]
  PIN xbi[0]
    DIRECTION INPUT ;
    USE SIGNAL ;
    PORT
      LAYER M3 ;
        RECT  91.476 0 91.494 0.144 ;
    END
  END xbi[0]
  PIN xbi[100]
    DIRECTION INPUT ;
    USE SIGNAL ;
    PORT
      LAYER M3 ;
        RECT  120.456 0 120.474 0.144 ;
    END
  END xbi[100]
  PIN xbi[101]
    DIRECTION INPUT ;
    USE SIGNAL ;
    PORT
      LAYER M5 ;
        RECT  120.768 0 120.792 0.192 ;
    END
  END xbi[101]
  PIN xbi[102]
    DIRECTION INPUT ;
    USE SIGNAL ;
    PORT
      LAYER M3 ;
        RECT  121.068 0 121.086 0.144 ;
    END
  END xbi[102]
  PIN xbi[103]
    DIRECTION INPUT ;
    USE SIGNAL ;
    PORT
      LAYER M5 ;
        RECT  121.344 0 121.368 0.192 ;
    END
  END xbi[103]
  PIN xbi[104]
    DIRECTION INPUT ;
    USE SIGNAL ;
    PORT
      LAYER M3 ;
        RECT  121.644 0 121.662 0.144 ;
    END
  END xbi[104]
  PIN xbi[105]
    DIRECTION INPUT ;
    USE SIGNAL ;
    PORT
      LAYER M5 ;
        RECT  121.92 0 121.944 0.192 ;
    END
  END xbi[105]
  PIN xbi[106]
    DIRECTION INPUT ;
    USE SIGNAL ;
    PORT
      LAYER M3 ;
        RECT  122.22 0 122.238 0.144 ;
    END
  END xbi[106]
  PIN xbi[107]
    DIRECTION INPUT ;
    USE SIGNAL ;
    PORT
      LAYER M5 ;
        RECT  122.496 0 122.52 0.192 ;
    END
  END xbi[107]
  PIN xbi[108]
    DIRECTION INPUT ;
    USE SIGNAL ;
    PORT
      LAYER M3 ;
        RECT  122.796 0 122.814 0.144 ;
    END
  END xbi[108]
  PIN xbi[109]
    DIRECTION INPUT ;
    USE SIGNAL ;
    PORT
      LAYER M5 ;
        RECT  123.072 0 123.096 0.192 ;
    END
  END xbi[109]
  PIN xbi[10]
    DIRECTION INPUT ;
    USE SIGNAL ;
    PORT
      LAYER M3 ;
        RECT  94.356 0 94.374 0.144 ;
    END
  END xbi[10]
  PIN xbi[110]
    DIRECTION INPUT ;
    USE SIGNAL ;
    PORT
      LAYER M3 ;
        RECT  123.372 0 123.39 0.144 ;
    END
  END xbi[110]
  PIN xbi[111]
    DIRECTION INPUT ;
    USE SIGNAL ;
    PORT
      LAYER M5 ;
        RECT  123.648 0 123.672 0.192 ;
    END
  END xbi[111]
  PIN xbi[112]
    DIRECTION INPUT ;
    USE SIGNAL ;
    PORT
      LAYER M3 ;
        RECT  123.948 0 123.966 0.144 ;
    END
  END xbi[112]
  PIN xbi[113]
    DIRECTION INPUT ;
    USE SIGNAL ;
    PORT
      LAYER M5 ;
        RECT  124.224 0 124.248 0.192 ;
    END
  END xbi[113]
  PIN xbi[114]
    DIRECTION INPUT ;
    USE SIGNAL ;
    PORT
      LAYER M3 ;
        RECT  124.524 0 124.542 0.144 ;
    END
  END xbi[114]
  PIN xbi[115]
    DIRECTION INPUT ;
    USE SIGNAL ;
    PORT
      LAYER M5 ;
        RECT  124.8 0 124.824 0.192 ;
    END
  END xbi[115]
  PIN xbi[116]
    DIRECTION INPUT ;
    USE SIGNAL ;
    PORT
      LAYER M3 ;
        RECT  125.1 0 125.118 0.144 ;
    END
  END xbi[116]
  PIN xbi[117]
    DIRECTION INPUT ;
    USE SIGNAL ;
    PORT
      LAYER M5 ;
        RECT  125.376 0 125.4 0.192 ;
    END
  END xbi[117]
  PIN xbi[118]
    DIRECTION INPUT ;
    USE SIGNAL ;
    PORT
      LAYER M3 ;
        RECT  125.676 0 125.694 0.144 ;
    END
  END xbi[118]
  PIN xbi[119]
    DIRECTION INPUT ;
    USE SIGNAL ;
    PORT
      LAYER M5 ;
        RECT  126 0 126.024 0.192 ;
    END
  END xbi[119]
  PIN xbi[11]
    DIRECTION INPUT ;
    USE SIGNAL ;
    PORT
      LAYER M5 ;
        RECT  94.656 0 94.68 0.192 ;
    END
  END xbi[11]
  PIN xbi[120]
    DIRECTION INPUT ;
    USE SIGNAL ;
    PORT
      LAYER M3 ;
        RECT  126.288 0 126.306 0.144 ;
    END
  END xbi[120]
  PIN xbi[121]
    DIRECTION INPUT ;
    USE SIGNAL ;
    PORT
      LAYER M5 ;
        RECT  126.576 0 126.6 0.192 ;
    END
  END xbi[121]
  PIN xbi[122]
    DIRECTION INPUT ;
    USE SIGNAL ;
    PORT
      LAYER M3 ;
        RECT  126.864 0 126.882 0.144 ;
    END
  END xbi[122]
  PIN xbi[123]
    DIRECTION INPUT ;
    USE SIGNAL ;
    PORT
      LAYER M5 ;
        RECT  127.152 0 127.176 0.192 ;
    END
  END xbi[123]
  PIN xbi[124]
    DIRECTION INPUT ;
    USE SIGNAL ;
    PORT
      LAYER M3 ;
        RECT  127.44 0 127.458 0.144 ;
    END
  END xbi[124]
  PIN xbi[125]
    DIRECTION INPUT ;
    USE SIGNAL ;
    PORT
      LAYER M5 ;
        RECT  127.728 0 127.752 0.192 ;
    END
  END xbi[125]
  PIN xbi[126]
    DIRECTION INPUT ;
    USE SIGNAL ;
    PORT
      LAYER M3 ;
        RECT  128.016 0 128.034 0.144 ;
    END
  END xbi[126]
  PIN xbi[127]
    DIRECTION INPUT ;
    USE SIGNAL ;
    PORT
      LAYER M5 ;
        RECT  128.304 0 128.328 0.192 ;
    END
  END xbi[127]
  PIN xbi[128]
    DIRECTION INPUT ;
    USE SIGNAL ;
    PORT
      LAYER M3 ;
        RECT  128.592 0 128.61 0.144 ;
    END
  END xbi[128]
  PIN xbi[129]
    DIRECTION INPUT ;
    USE SIGNAL ;
    PORT
      LAYER M5 ;
        RECT  128.88 0 128.904 0.192 ;
    END
  END xbi[129]
  PIN xbi[12]
    DIRECTION INPUT ;
    USE SIGNAL ;
    PORT
      LAYER M3 ;
        RECT  94.932 0 94.95 0.144 ;
    END
  END xbi[12]
  PIN xbi[130]
    DIRECTION INPUT ;
    USE SIGNAL ;
    PORT
      LAYER M3 ;
        RECT  129.168 0 129.186 0.144 ;
    END
  END xbi[130]
  PIN xbi[131]
    DIRECTION INPUT ;
    USE SIGNAL ;
    PORT
      LAYER M5 ;
        RECT  129.456 0 129.48 0.192 ;
    END
  END xbi[131]
  PIN xbi[132]
    DIRECTION INPUT ;
    USE SIGNAL ;
    PORT
      LAYER M3 ;
        RECT  129.744 0 129.762 0.144 ;
    END
  END xbi[132]
  PIN xbi[133]
    DIRECTION INPUT ;
    USE SIGNAL ;
    PORT
      LAYER M5 ;
        RECT  130.032 0 130.056 0.192 ;
    END
  END xbi[133]
  PIN xbi[134]
    DIRECTION INPUT ;
    USE SIGNAL ;
    PORT
      LAYER M3 ;
        RECT  130.32 0 130.338 0.144 ;
    END
  END xbi[134]
  PIN xbi[135]
    DIRECTION INPUT ;
    USE SIGNAL ;
    PORT
      LAYER M5 ;
        RECT  130.608 0 130.632 0.192 ;
    END
  END xbi[135]
  PIN xbi[136]
    DIRECTION INPUT ;
    USE SIGNAL ;
    PORT
      LAYER M3 ;
        RECT  130.896 0 130.914 0.144 ;
    END
  END xbi[136]
  PIN xbi[137]
    DIRECTION INPUT ;
    USE SIGNAL ;
    PORT
      LAYER M5 ;
        RECT  131.184 0 131.208 0.192 ;
    END
  END xbi[137]
  PIN xbi[138]
    DIRECTION INPUT ;
    USE SIGNAL ;
    PORT
      LAYER M3 ;
        RECT  131.508 0 131.526 0.144 ;
    END
  END xbi[138]
  PIN xbi[139]
    DIRECTION INPUT ;
    USE SIGNAL ;
    PORT
      LAYER M5 ;
        RECT  131.76 0 131.784 0.192 ;
    END
  END xbi[139]
  PIN xbi[13]
    DIRECTION INPUT ;
    USE SIGNAL ;
    PORT
      LAYER M5 ;
        RECT  95.232 0 95.256 0.192 ;
    END
  END xbi[13]
  PIN xbi[140]
    DIRECTION INPUT ;
    USE SIGNAL ;
    PORT
      LAYER M3 ;
        RECT  132.084 0 132.102 0.144 ;
    END
  END xbi[140]
  PIN xbi[141]
    DIRECTION INPUT ;
    USE SIGNAL ;
    PORT
      LAYER M5 ;
        RECT  132.336 0 132.36 0.192 ;
    END
  END xbi[141]
  PIN xbi[142]
    DIRECTION INPUT ;
    USE SIGNAL ;
    PORT
      LAYER M3 ;
        RECT  132.66 0 132.678 0.144 ;
    END
  END xbi[142]
  PIN xbi[143]
    DIRECTION INPUT ;
    USE SIGNAL ;
    PORT
      LAYER M5 ;
        RECT  132.96 0 132.984 0.192 ;
    END
  END xbi[143]
  PIN xbi[144]
    DIRECTION INPUT ;
    USE SIGNAL ;
    PORT
      LAYER M3 ;
        RECT  133.236 0 133.254 0.144 ;
    END
  END xbi[144]
  PIN xbi[145]
    DIRECTION INPUT ;
    USE SIGNAL ;
    PORT
      LAYER M5 ;
        RECT  133.536 0 133.56 0.192 ;
    END
  END xbi[145]
  PIN xbi[146]
    DIRECTION INPUT ;
    USE SIGNAL ;
    PORT
      LAYER M3 ;
        RECT  133.812 0 133.83 0.144 ;
    END
  END xbi[146]
  PIN xbi[147]
    DIRECTION INPUT ;
    USE SIGNAL ;
    PORT
      LAYER M5 ;
        RECT  134.112 0 134.136 0.192 ;
    END
  END xbi[147]
  PIN xbi[148]
    DIRECTION INPUT ;
    USE SIGNAL ;
    PORT
      LAYER M3 ;
        RECT  134.388 0 134.406 0.144 ;
    END
  END xbi[148]
  PIN xbi[149]
    DIRECTION INPUT ;
    USE SIGNAL ;
    PORT
      LAYER M5 ;
        RECT  134.688 0 134.712 0.192 ;
    END
  END xbi[149]
  PIN xbi[14]
    DIRECTION INPUT ;
    USE SIGNAL ;
    PORT
      LAYER M3 ;
        RECT  95.544 0 95.562 0.144 ;
    END
  END xbi[14]
  PIN xbi[150]
    DIRECTION INPUT ;
    USE SIGNAL ;
    PORT
      LAYER M3 ;
        RECT  134.964 0 134.982 0.144 ;
    END
  END xbi[150]
  PIN xbi[151]
    DIRECTION INPUT ;
    USE SIGNAL ;
    PORT
      LAYER M5 ;
        RECT  135.264 0 135.288 0.192 ;
    END
  END xbi[151]
  PIN xbi[152]
    DIRECTION INPUT ;
    USE SIGNAL ;
    PORT
      LAYER M3 ;
        RECT  135.54 0 135.558 0.144 ;
    END
  END xbi[152]
  PIN xbi[153]
    DIRECTION INPUT ;
    USE SIGNAL ;
    PORT
      LAYER M5 ;
        RECT  135.84 0 135.864 0.192 ;
    END
  END xbi[153]
  PIN xbi[154]
    DIRECTION INPUT ;
    USE SIGNAL ;
    PORT
      LAYER M3 ;
        RECT  136.116 0 136.134 0.144 ;
    END
  END xbi[154]
  PIN xbi[155]
    DIRECTION INPUT ;
    USE SIGNAL ;
    PORT
      LAYER M5 ;
        RECT  136.416 0 136.44 0.192 ;
    END
  END xbi[155]
  PIN xbi[156]
    DIRECTION INPUT ;
    USE SIGNAL ;
    PORT
      LAYER M3 ;
        RECT  136.728 0 136.746 0.144 ;
    END
  END xbi[156]
  PIN xbi[157]
    DIRECTION INPUT ;
    USE SIGNAL ;
    PORT
      LAYER M5 ;
        RECT  136.992 0 137.016 0.192 ;
    END
  END xbi[157]
  PIN xbi[158]
    DIRECTION INPUT ;
    USE SIGNAL ;
    PORT
      LAYER M3 ;
        RECT  137.304 0 137.322 0.144 ;
    END
  END xbi[158]
  PIN xbi[159]
    DIRECTION INPUT ;
    USE SIGNAL ;
    PORT
      LAYER M5 ;
        RECT  137.568 0 137.592 0.192 ;
    END
  END xbi[159]
  PIN xbi[15]
    DIRECTION INPUT ;
    USE SIGNAL ;
    PORT
      LAYER M5 ;
        RECT  95.808 0 95.832 0.192 ;
    END
  END xbi[15]
  PIN xbi[160]
    DIRECTION INPUT ;
    USE SIGNAL ;
    PORT
      LAYER M3 ;
        RECT  137.88 0 137.898 0.144 ;
    END
  END xbi[160]
  PIN xbi[161]
    DIRECTION INPUT ;
    USE SIGNAL ;
    PORT
      LAYER M5 ;
        RECT  138.144 0 138.168 0.192 ;
    END
  END xbi[161]
  PIN xbi[162]
    DIRECTION INPUT ;
    USE SIGNAL ;
    PORT
      LAYER M3 ;
        RECT  138.456 0 138.474 0.144 ;
    END
  END xbi[162]
  PIN xbi[163]
    DIRECTION INPUT ;
    USE SIGNAL ;
    PORT
      LAYER M5 ;
        RECT  138.72 0 138.744 0.192 ;
    END
  END xbi[163]
  PIN xbi[164]
    DIRECTION INPUT ;
    USE SIGNAL ;
    PORT
      LAYER M3 ;
        RECT  139.032 0 139.05 0.144 ;
    END
  END xbi[164]
  PIN xbi[165]
    DIRECTION INPUT ;
    USE SIGNAL ;
    PORT
      LAYER M5 ;
        RECT  139.296 0 139.32 0.192 ;
    END
  END xbi[165]
  PIN xbi[166]
    DIRECTION INPUT ;
    USE SIGNAL ;
    PORT
      LAYER M3 ;
        RECT  139.608 0 139.626 0.144 ;
    END
  END xbi[166]
  PIN xbi[167]
    DIRECTION INPUT ;
    USE SIGNAL ;
    PORT
      LAYER M5 ;
        RECT  139.92 0 139.944 0.192 ;
    END
  END xbi[167]
  PIN xbi[168]
    DIRECTION INPUT ;
    USE SIGNAL ;
    PORT
      LAYER M3 ;
        RECT  140.184 0 140.202 0.144 ;
    END
  END xbi[168]
  PIN xbi[169]
    DIRECTION INPUT ;
    USE SIGNAL ;
    PORT
      LAYER M5 ;
        RECT  140.496 0 140.52 0.192 ;
    END
  END xbi[169]
  PIN xbi[16]
    DIRECTION INPUT ;
    USE SIGNAL ;
    PORT
      LAYER M3 ;
        RECT  96.12 0 96.138 0.144 ;
    END
  END xbi[16]
  PIN xbi[170]
    DIRECTION INPUT ;
    USE SIGNAL ;
    PORT
      LAYER M3 ;
        RECT  140.76 0 140.778 0.144 ;
    END
  END xbi[170]
  PIN xbi[171]
    DIRECTION INPUT ;
    USE SIGNAL ;
    PORT
      LAYER M5 ;
        RECT  141.072 0 141.096 0.192 ;
    END
  END xbi[171]
  PIN xbi[172]
    DIRECTION INPUT ;
    USE SIGNAL ;
    PORT
      LAYER M3 ;
        RECT  141.336 0 141.354 0.144 ;
    END
  END xbi[172]
  PIN xbi[173]
    DIRECTION INPUT ;
    USE SIGNAL ;
    PORT
      LAYER M5 ;
        RECT  141.648 0 141.672 0.192 ;
    END
  END xbi[173]
  PIN xbi[174]
    DIRECTION INPUT ;
    USE SIGNAL ;
    PORT
      LAYER M3 ;
        RECT  141.948 0 141.966 0.144 ;
    END
  END xbi[174]
  PIN xbi[175]
    DIRECTION INPUT ;
    USE SIGNAL ;
    PORT
      LAYER M5 ;
        RECT  142.224 0 142.248 0.192 ;
    END
  END xbi[175]
  PIN xbi[176]
    DIRECTION INPUT ;
    USE SIGNAL ;
    PORT
      LAYER M3 ;
        RECT  142.524 0 142.542 0.144 ;
    END
  END xbi[176]
  PIN xbi[177]
    DIRECTION INPUT ;
    USE SIGNAL ;
    PORT
      LAYER M5 ;
        RECT  142.8 0 142.824 0.192 ;
    END
  END xbi[177]
  PIN xbi[178]
    DIRECTION INPUT ;
    USE SIGNAL ;
    PORT
      LAYER M3 ;
        RECT  143.1 0 143.118 0.144 ;
    END
  END xbi[178]
  PIN xbi[179]
    DIRECTION INPUT ;
    USE SIGNAL ;
    PORT
      LAYER M5 ;
        RECT  143.376 0 143.4 0.192 ;
    END
  END xbi[179]
  PIN xbi[17]
    DIRECTION INPUT ;
    USE SIGNAL ;
    PORT
      LAYER M5 ;
        RECT  96.384 0 96.408 0.192 ;
    END
  END xbi[17]
  PIN xbi[180]
    DIRECTION INPUT ;
    USE SIGNAL ;
    PORT
      LAYER M3 ;
        RECT  143.676 0 143.694 0.144 ;
    END
  END xbi[180]
  PIN xbi[181]
    DIRECTION INPUT ;
    USE SIGNAL ;
    PORT
      LAYER M5 ;
        RECT  143.952 0 143.976 0.192 ;
    END
  END xbi[181]
  PIN xbi[182]
    DIRECTION INPUT ;
    USE SIGNAL ;
    PORT
      LAYER M3 ;
        RECT  144.252 0 144.27 0.144 ;
    END
  END xbi[182]
  PIN xbi[183]
    DIRECTION INPUT ;
    USE SIGNAL ;
    PORT
      LAYER M5 ;
        RECT  144.528 0 144.552 0.192 ;
    END
  END xbi[183]
  PIN xbi[184]
    DIRECTION INPUT ;
    USE SIGNAL ;
    PORT
      LAYER M3 ;
        RECT  144.828 0 144.846 0.144 ;
    END
  END xbi[184]
  PIN xbi[185]
    DIRECTION INPUT ;
    USE SIGNAL ;
    PORT
      LAYER M5 ;
        RECT  145.104 0 145.128 0.192 ;
    END
  END xbi[185]
  PIN xbi[186]
    DIRECTION INPUT ;
    USE SIGNAL ;
    PORT
      LAYER M3 ;
        RECT  145.404 0 145.422 0.144 ;
    END
  END xbi[186]
  PIN xbi[187]
    DIRECTION INPUT ;
    USE SIGNAL ;
    PORT
      LAYER M5 ;
        RECT  145.68 0 145.704 0.192 ;
    END
  END xbi[187]
  PIN xbi[188]
    DIRECTION INPUT ;
    USE SIGNAL ;
    PORT
      LAYER M3 ;
        RECT  145.98 0 145.998 0.144 ;
    END
  END xbi[188]
  PIN xbi[189]
    DIRECTION INPUT ;
    USE SIGNAL ;
    PORT
      LAYER M5 ;
        RECT  146.304 0 146.328 0.192 ;
    END
  END xbi[189]
  PIN xbi[18]
    DIRECTION INPUT ;
    USE SIGNAL ;
    PORT
      LAYER M3 ;
        RECT  96.696 0 96.714 0.144 ;
    END
  END xbi[18]
  PIN xbi[190]
    DIRECTION INPUT ;
    USE SIGNAL ;
    PORT
      LAYER M3 ;
        RECT  146.556 0 146.574 0.144 ;
    END
  END xbi[190]
  PIN xbi[191]
    DIRECTION INPUT ;
    USE SIGNAL ;
    PORT
      LAYER M5 ;
        RECT  146.88 0 146.904 0.192 ;
    END
  END xbi[191]
  PIN xbi[192]
    DIRECTION INPUT ;
    USE SIGNAL ;
    PORT
      LAYER M3 ;
        RECT  147.168 0 147.186 0.144 ;
    END
  END xbi[192]
  PIN xbi[193]
    DIRECTION INPUT ;
    USE SIGNAL ;
    PORT
      LAYER M5 ;
        RECT  147.456 0 147.48 0.192 ;
    END
  END xbi[193]
  PIN xbi[194]
    DIRECTION INPUT ;
    USE SIGNAL ;
    PORT
      LAYER M3 ;
        RECT  147.744 0 147.762 0.144 ;
    END
  END xbi[194]
  PIN xbi[195]
    DIRECTION INPUT ;
    USE SIGNAL ;
    PORT
      LAYER M5 ;
        RECT  148.032 0 148.056 0.192 ;
    END
  END xbi[195]
  PIN xbi[196]
    DIRECTION INPUT ;
    USE SIGNAL ;
    PORT
      LAYER M3 ;
        RECT  148.32 0 148.338 0.144 ;
    END
  END xbi[196]
  PIN xbi[197]
    DIRECTION INPUT ;
    USE SIGNAL ;
    PORT
      LAYER M5 ;
        RECT  148.608 0 148.632 0.192 ;
    END
  END xbi[197]
  PIN xbi[198]
    DIRECTION INPUT ;
    USE SIGNAL ;
    PORT
      LAYER M3 ;
        RECT  148.896 0 148.914 0.144 ;
    END
  END xbi[198]
  PIN xbi[199]
    DIRECTION INPUT ;
    USE SIGNAL ;
    PORT
      LAYER M5 ;
        RECT  149.184 0 149.208 0.192 ;
    END
  END xbi[199]
  PIN xbi[19]
    DIRECTION INPUT ;
    USE SIGNAL ;
    PORT
      LAYER M5 ;
        RECT  96.96 0 96.984 0.192 ;
    END
  END xbi[19]
  PIN xbi[1]
    DIRECTION INPUT ;
    USE SIGNAL ;
    PORT
      LAYER M5 ;
        RECT  91.776 0 91.8 0.192 ;
    END
  END xbi[1]
  PIN xbi[200]
    DIRECTION INPUT ;
    USE SIGNAL ;
    PORT
      LAYER M3 ;
        RECT  149.472 0 149.49 0.144 ;
    END
  END xbi[200]
  PIN xbi[201]
    DIRECTION INPUT ;
    USE SIGNAL ;
    PORT
      LAYER M5 ;
        RECT  149.76 0 149.784 0.192 ;
    END
  END xbi[201]
  PIN xbi[202]
    DIRECTION INPUT ;
    USE SIGNAL ;
    PORT
      LAYER M3 ;
        RECT  150.048 0 150.066 0.144 ;
    END
  END xbi[202]
  PIN xbi[203]
    DIRECTION INPUT ;
    USE SIGNAL ;
    PORT
      LAYER M5 ;
        RECT  150.336 0 150.36 0.192 ;
    END
  END xbi[203]
  PIN xbi[204]
    DIRECTION INPUT ;
    USE SIGNAL ;
    PORT
      LAYER M3 ;
        RECT  150.624 0 150.642 0.144 ;
    END
  END xbi[204]
  PIN xbi[205]
    DIRECTION INPUT ;
    USE SIGNAL ;
    PORT
      LAYER M5 ;
        RECT  150.912 0 150.936 0.192 ;
    END
  END xbi[205]
  PIN xbi[206]
    DIRECTION INPUT ;
    USE SIGNAL ;
    PORT
      LAYER M3 ;
        RECT  151.2 0 151.218 0.144 ;
    END
  END xbi[206]
  PIN xbi[207]
    DIRECTION INPUT ;
    USE SIGNAL ;
    PORT
      LAYER M5 ;
        RECT  151.488 0 151.512 0.192 ;
    END
  END xbi[207]
  PIN xbi[208]
    DIRECTION INPUT ;
    USE SIGNAL ;
    PORT
      LAYER M3 ;
        RECT  151.776 0 151.794 0.144 ;
    END
  END xbi[208]
  PIN xbi[209]
    DIRECTION INPUT ;
    USE SIGNAL ;
    PORT
      LAYER M5 ;
        RECT  152.064 0 152.088 0.192 ;
    END
  END xbi[209]
  PIN xbi[20]
    DIRECTION INPUT ;
    USE SIGNAL ;
    PORT
      LAYER M3 ;
        RECT  97.272 0 97.29 0.144 ;
    END
  END xbi[20]
  PIN xbi[210]
    DIRECTION INPUT ;
    USE SIGNAL ;
    PORT
      LAYER M3 ;
        RECT  152.388 0 152.406 0.144 ;
    END
  END xbi[210]
  PIN xbi[211]
    DIRECTION INPUT ;
    USE SIGNAL ;
    PORT
      LAYER M5 ;
        RECT  152.64 0 152.664 0.192 ;
    END
  END xbi[211]
  PIN xbi[212]
    DIRECTION INPUT ;
    USE SIGNAL ;
    PORT
      LAYER M3 ;
        RECT  152.964 0 152.982 0.144 ;
    END
  END xbi[212]
  PIN xbi[213]
    DIRECTION INPUT ;
    USE SIGNAL ;
    PORT
      LAYER M5 ;
        RECT  153.264 0 153.288 0.192 ;
    END
  END xbi[213]
  PIN xbi[214]
    DIRECTION INPUT ;
    USE SIGNAL ;
    PORT
      LAYER M3 ;
        RECT  153.54 0 153.558 0.144 ;
    END
  END xbi[214]
  PIN xbi[215]
    DIRECTION INPUT ;
    USE SIGNAL ;
    PORT
      LAYER M5 ;
        RECT  153.84 0 153.864 0.192 ;
    END
  END xbi[215]
  PIN xbi[216]
    DIRECTION INPUT ;
    USE SIGNAL ;
    PORT
      LAYER M3 ;
        RECT  154.116 0 154.134 0.144 ;
    END
  END xbi[216]
  PIN xbi[217]
    DIRECTION INPUT ;
    USE SIGNAL ;
    PORT
      LAYER M5 ;
        RECT  154.416 0 154.44 0.192 ;
    END
  END xbi[217]
  PIN xbi[218]
    DIRECTION INPUT ;
    USE SIGNAL ;
    PORT
      LAYER M3 ;
        RECT  154.692 0 154.71 0.144 ;
    END
  END xbi[218]
  PIN xbi[219]
    DIRECTION INPUT ;
    USE SIGNAL ;
    PORT
      LAYER M5 ;
        RECT  154.992 0 155.016 0.192 ;
    END
  END xbi[219]
  PIN xbi[21]
    DIRECTION INPUT ;
    USE SIGNAL ;
    PORT
      LAYER M5 ;
        RECT  97.536 0 97.56 0.192 ;
    END
  END xbi[21]
  PIN xbi[220]
    DIRECTION INPUT ;
    USE SIGNAL ;
    PORT
      LAYER M3 ;
        RECT  155.268 0 155.286 0.144 ;
    END
  END xbi[220]
  PIN xbi[221]
    DIRECTION INPUT ;
    USE SIGNAL ;
    PORT
      LAYER M5 ;
        RECT  155.568 0 155.592 0.192 ;
    END
  END xbi[221]
  PIN xbi[222]
    DIRECTION INPUT ;
    USE SIGNAL ;
    PORT
      LAYER M3 ;
        RECT  155.844 0 155.862 0.144 ;
    END
  END xbi[222]
  PIN xbi[223]
    DIRECTION INPUT ;
    USE SIGNAL ;
    PORT
      LAYER M5 ;
        RECT  156.144 0 156.168 0.192 ;
    END
  END xbi[223]
  PIN xbi[224]
    DIRECTION INPUT ;
    USE SIGNAL ;
    PORT
      LAYER M3 ;
        RECT  156.42 0 156.438 0.144 ;
    END
  END xbi[224]
  PIN xbi[225]
    DIRECTION INPUT ;
    USE SIGNAL ;
    PORT
      LAYER M5 ;
        RECT  156.72 0 156.744 0.192 ;
    END
  END xbi[225]
  PIN xbi[226]
    DIRECTION INPUT ;
    USE SIGNAL ;
    PORT
      LAYER M3 ;
        RECT  157.032 0 157.05 0.144 ;
    END
  END xbi[226]
  PIN xbi[227]
    DIRECTION INPUT ;
    USE SIGNAL ;
    PORT
      LAYER M5 ;
        RECT  157.296 0 157.32 0.192 ;
    END
  END xbi[227]
  PIN xbi[228]
    DIRECTION INPUT ;
    USE SIGNAL ;
    PORT
      LAYER M3 ;
        RECT  157.608 0 157.626 0.144 ;
    END
  END xbi[228]
  PIN xbi[229]
    DIRECTION INPUT ;
    USE SIGNAL ;
    PORT
      LAYER M5 ;
        RECT  157.872 0 157.896 0.192 ;
    END
  END xbi[229]
  PIN xbi[22]
    DIRECTION INPUT ;
    USE SIGNAL ;
    PORT
      LAYER M3 ;
        RECT  97.848 0 97.866 0.144 ;
    END
  END xbi[22]
  PIN xbi[230]
    DIRECTION INPUT ;
    USE SIGNAL ;
    PORT
      LAYER M3 ;
        RECT  158.184 0 158.202 0.144 ;
    END
  END xbi[230]
  PIN xbi[231]
    DIRECTION INPUT ;
    USE SIGNAL ;
    PORT
      LAYER M5 ;
        RECT  158.448 0 158.472 0.192 ;
    END
  END xbi[231]
  PIN xbi[232]
    DIRECTION INPUT ;
    USE SIGNAL ;
    PORT
      LAYER M3 ;
        RECT  158.76 0 158.778 0.144 ;
    END
  END xbi[232]
  PIN xbi[233]
    DIRECTION INPUT ;
    USE SIGNAL ;
    PORT
      LAYER M5 ;
        RECT  159.024 0 159.048 0.192 ;
    END
  END xbi[233]
  PIN xbi[234]
    DIRECTION INPUT ;
    USE SIGNAL ;
    PORT
      LAYER M3 ;
        RECT  159.336 0 159.354 0.144 ;
    END
  END xbi[234]
  PIN xbi[235]
    DIRECTION INPUT ;
    USE SIGNAL ;
    PORT
      LAYER M5 ;
        RECT  159.6 0 159.624 0.192 ;
    END
  END xbi[235]
  PIN xbi[236]
    DIRECTION INPUT ;
    USE SIGNAL ;
    PORT
      LAYER M3 ;
        RECT  159.912 0 159.93 0.144 ;
    END
  END xbi[236]
  PIN xbi[237]
    DIRECTION INPUT ;
    USE SIGNAL ;
    PORT
      LAYER M5 ;
        RECT  160.224 0 160.248 0.192 ;
    END
  END xbi[237]
  PIN xbi[238]
    DIRECTION INPUT ;
    USE SIGNAL ;
    PORT
      LAYER M3 ;
        RECT  160.488 0 160.506 0.144 ;
    END
  END xbi[238]
  PIN xbi[239]
    DIRECTION INPUT ;
    USE SIGNAL ;
    PORT
      LAYER M5 ;
        RECT  160.8 0 160.824 0.192 ;
    END
  END xbi[239]
  PIN xbi[23]
    DIRECTION INPUT ;
    USE SIGNAL ;
    PORT
      LAYER M5 ;
        RECT  98.112 0 98.136 0.192 ;
    END
  END xbi[23]
  PIN xbi[240]
    DIRECTION INPUT ;
    USE SIGNAL ;
    PORT
      LAYER M3 ;
        RECT  161.064 0 161.082 0.144 ;
    END
  END xbi[240]
  PIN xbi[241]
    DIRECTION INPUT ;
    USE SIGNAL ;
    PORT
      LAYER M5 ;
        RECT  161.376 0 161.4 0.192 ;
    END
  END xbi[241]
  PIN xbi[242]
    DIRECTION INPUT ;
    USE SIGNAL ;
    PORT
      LAYER M3 ;
        RECT  161.64 0 161.658 0.144 ;
    END
  END xbi[242]
  PIN xbi[243]
    DIRECTION INPUT ;
    USE SIGNAL ;
    PORT
      LAYER M5 ;
        RECT  161.952 0 161.976 0.192 ;
    END
  END xbi[243]
  PIN xbi[244]
    DIRECTION INPUT ;
    USE SIGNAL ;
    PORT
      LAYER M3 ;
        RECT  162.252 0 162.27 0.144 ;
    END
  END xbi[244]
  PIN xbi[245]
    DIRECTION INPUT ;
    USE SIGNAL ;
    PORT
      LAYER M5 ;
        RECT  162.528 0 162.552 0.192 ;
    END
  END xbi[245]
  PIN xbi[246]
    DIRECTION INPUT ;
    USE SIGNAL ;
    PORT
      LAYER M3 ;
        RECT  162.828 0 162.846 0.144 ;
    END
  END xbi[246]
  PIN xbi[247]
    DIRECTION INPUT ;
    USE SIGNAL ;
    PORT
      LAYER M5 ;
        RECT  163.104 0 163.128 0.192 ;
    END
  END xbi[247]
  PIN xbi[248]
    DIRECTION INPUT ;
    USE SIGNAL ;
    PORT
      LAYER M3 ;
        RECT  163.404 0 163.422 0.144 ;
    END
  END xbi[248]
  PIN xbi[249]
    DIRECTION INPUT ;
    USE SIGNAL ;
    PORT
      LAYER M5 ;
        RECT  163.68 0 163.704 0.192 ;
    END
  END xbi[249]
  PIN xbi[24]
    DIRECTION INPUT ;
    USE SIGNAL ;
    PORT
      LAYER M3 ;
        RECT  98.424 0 98.442 0.144 ;
    END
  END xbi[24]
  PIN xbi[250]
    DIRECTION INPUT ;
    USE SIGNAL ;
    PORT
      LAYER M3 ;
        RECT  163.98 0 163.998 0.144 ;
    END
  END xbi[250]
  PIN xbi[251]
    DIRECTION INPUT ;
    USE SIGNAL ;
    PORT
      LAYER M5 ;
        RECT  164.256 0 164.28 0.192 ;
    END
  END xbi[251]
  PIN xbi[252]
    DIRECTION INPUT ;
    USE SIGNAL ;
    PORT
      LAYER M3 ;
        RECT  164.556 0 164.574 0.144 ;
    END
  END xbi[252]
  PIN xbi[253]
    DIRECTION INPUT ;
    USE SIGNAL ;
    PORT
      LAYER M5 ;
        RECT  164.832 0 164.856 0.192 ;
    END
  END xbi[253]
  PIN xbi[254]
    DIRECTION INPUT ;
    USE SIGNAL ;
    PORT
      LAYER M3 ;
        RECT  165.132 0 165.15 0.144 ;
    END
  END xbi[254]
  PIN xbi[255]
    DIRECTION INPUT ;
    USE SIGNAL ;
    PORT
      LAYER M5 ;
        RECT  165.408 0 165.432 0.192 ;
    END
  END xbi[255]
  PIN xbi[256]
    DIRECTION INPUT ;
    USE SIGNAL ;
    PORT
      LAYER M3 ;
        RECT  165.708 0 165.726 0.144 ;
    END
  END xbi[256]
  PIN xbi[257]
    DIRECTION INPUT ;
    USE SIGNAL ;
    PORT
      LAYER M5 ;
        RECT  165.984 0 166.008 0.192 ;
    END
  END xbi[257]
  PIN xbi[258]
    DIRECTION INPUT ;
    USE SIGNAL ;
    PORT
      LAYER M3 ;
        RECT  166.284 0 166.302 0.144 ;
    END
  END xbi[258]
  PIN xbi[259]
    DIRECTION INPUT ;
    USE SIGNAL ;
    PORT
      LAYER M5 ;
        RECT  166.56 0 166.584 0.192 ;
    END
  END xbi[259]
  PIN xbi[25]
    DIRECTION INPUT ;
    USE SIGNAL ;
    PORT
      LAYER M5 ;
        RECT  98.736 0 98.76 0.192 ;
    END
  END xbi[25]
  PIN xbi[260]
    DIRECTION INPUT ;
    USE SIGNAL ;
    PORT
      LAYER M3 ;
        RECT  166.86 0 166.878 0.144 ;
    END
  END xbi[260]
  PIN xbi[261]
    DIRECTION INPUT ;
    USE SIGNAL ;
    PORT
      LAYER M5 ;
        RECT  167.184 0 167.208 0.192 ;
    END
  END xbi[261]
  PIN xbi[262]
    DIRECTION INPUT ;
    USE SIGNAL ;
    PORT
      LAYER M3 ;
        RECT  167.472 0 167.49 0.144 ;
    END
  END xbi[262]
  PIN xbi[263]
    DIRECTION INPUT ;
    USE SIGNAL ;
    PORT
      LAYER M5 ;
        RECT  167.76 0 167.784 0.192 ;
    END
  END xbi[263]
  PIN xbi[264]
    DIRECTION INPUT ;
    USE SIGNAL ;
    PORT
      LAYER M3 ;
        RECT  168.048 0 168.066 0.144 ;
    END
  END xbi[264]
  PIN xbi[265]
    DIRECTION INPUT ;
    USE SIGNAL ;
    PORT
      LAYER M5 ;
        RECT  168.336 0 168.36 0.192 ;
    END
  END xbi[265]
  PIN xbi[26]
    DIRECTION INPUT ;
    USE SIGNAL ;
    PORT
      LAYER M3 ;
        RECT  99 0 99.018 0.144 ;
    END
  END xbi[26]
  PIN xbi[27]
    DIRECTION INPUT ;
    USE SIGNAL ;
    PORT
      LAYER M5 ;
        RECT  99.312 0 99.336 0.192 ;
    END
  END xbi[27]
  PIN xbi[28]
    DIRECTION INPUT ;
    USE SIGNAL ;
    PORT
      LAYER M3 ;
        RECT  99.576 0 99.594 0.144 ;
    END
  END xbi[28]
  PIN xbi[29]
    DIRECTION INPUT ;
    USE SIGNAL ;
    PORT
      LAYER M5 ;
        RECT  99.888 0 99.912 0.192 ;
    END
  END xbi[29]
  PIN xbi[2]
    DIRECTION INPUT ;
    USE SIGNAL ;
    PORT
      LAYER M3 ;
        RECT  92.052 0 92.07 0.144 ;
    END
  END xbi[2]
  PIN xbi[30]
    DIRECTION INPUT ;
    USE SIGNAL ;
    PORT
      LAYER M3 ;
        RECT  100.152 0 100.17 0.144 ;
    END
  END xbi[30]
  PIN xbi[31]
    DIRECTION INPUT ;
    USE SIGNAL ;
    PORT
      LAYER M5 ;
        RECT  100.464 0 100.488 0.192 ;
    END
  END xbi[31]
  PIN xbi[32]
    DIRECTION INPUT ;
    USE SIGNAL ;
    PORT
      LAYER M3 ;
        RECT  100.764 0 100.782 0.144 ;
    END
  END xbi[32]
  PIN xbi[33]
    DIRECTION INPUT ;
    USE SIGNAL ;
    PORT
      LAYER M5 ;
        RECT  101.04 0 101.064 0.192 ;
    END
  END xbi[33]
  PIN xbi[34]
    DIRECTION INPUT ;
    USE SIGNAL ;
    PORT
      LAYER M3 ;
        RECT  101.34 0 101.358 0.144 ;
    END
  END xbi[34]
  PIN xbi[35]
    DIRECTION INPUT ;
    USE SIGNAL ;
    PORT
      LAYER M5 ;
        RECT  101.616 0 101.64 0.192 ;
    END
  END xbi[35]
  PIN xbi[36]
    DIRECTION INPUT ;
    USE SIGNAL ;
    PORT
      LAYER M3 ;
        RECT  101.916 0 101.934 0.144 ;
    END
  END xbi[36]
  PIN xbi[37]
    DIRECTION INPUT ;
    USE SIGNAL ;
    PORT
      LAYER M5 ;
        RECT  102.192 0 102.216 0.192 ;
    END
  END xbi[37]
  PIN xbi[38]
    DIRECTION INPUT ;
    USE SIGNAL ;
    PORT
      LAYER M3 ;
        RECT  102.492 0 102.51 0.144 ;
    END
  END xbi[38]
  PIN xbi[39]
    DIRECTION INPUT ;
    USE SIGNAL ;
    PORT
      LAYER M5 ;
        RECT  102.768 0 102.792 0.192 ;
    END
  END xbi[39]
  PIN xbi[3]
    DIRECTION INPUT ;
    USE SIGNAL ;
    PORT
      LAYER M5 ;
        RECT  92.352 0 92.376 0.192 ;
    END
  END xbi[3]
  PIN xbi[40]
    DIRECTION INPUT ;
    USE SIGNAL ;
    PORT
      LAYER M3 ;
        RECT  103.068 0 103.086 0.144 ;
    END
  END xbi[40]
  PIN xbi[41]
    DIRECTION INPUT ;
    USE SIGNAL ;
    PORT
      LAYER M5 ;
        RECT  103.344 0 103.368 0.192 ;
    END
  END xbi[41]
  PIN xbi[42]
    DIRECTION INPUT ;
    USE SIGNAL ;
    PORT
      LAYER M3 ;
        RECT  103.644 0 103.662 0.144 ;
    END
  END xbi[42]
  PIN xbi[43]
    DIRECTION INPUT ;
    USE SIGNAL ;
    PORT
      LAYER M5 ;
        RECT  103.92 0 103.944 0.192 ;
    END
  END xbi[43]
  PIN xbi[44]
    DIRECTION INPUT ;
    USE SIGNAL ;
    PORT
      LAYER M3 ;
        RECT  104.22 0 104.238 0.144 ;
    END
  END xbi[44]
  PIN xbi[45]
    DIRECTION INPUT ;
    USE SIGNAL ;
    PORT
      LAYER M5 ;
        RECT  104.496 0 104.52 0.192 ;
    END
  END xbi[45]
  PIN xbi[46]
    DIRECTION INPUT ;
    USE SIGNAL ;
    PORT
      LAYER M3 ;
        RECT  104.796 0 104.814 0.144 ;
    END
  END xbi[46]
  PIN xbi[47]
    DIRECTION INPUT ;
    USE SIGNAL ;
    PORT
      LAYER M5 ;
        RECT  105.072 0 105.096 0.192 ;
    END
  END xbi[47]
  PIN xbi[48]
    DIRECTION INPUT ;
    USE SIGNAL ;
    PORT
      LAYER M3 ;
        RECT  105.372 0 105.39 0.144 ;
    END
  END xbi[48]
  PIN xbi[49]
    DIRECTION INPUT ;
    USE SIGNAL ;
    PORT
      LAYER M5 ;
        RECT  105.696 0 105.72 0.192 ;
    END
  END xbi[49]
  PIN xbi[4]
    DIRECTION INPUT ;
    USE SIGNAL ;
    PORT
      LAYER M3 ;
        RECT  92.628 0 92.646 0.144 ;
    END
  END xbi[4]
  PIN xbi[50]
    DIRECTION INPUT ;
    USE SIGNAL ;
    PORT
      LAYER M3 ;
        RECT  105.984 0 106.002 0.144 ;
    END
  END xbi[50]
  PIN xbi[51]
    DIRECTION INPUT ;
    USE SIGNAL ;
    PORT
      LAYER M5 ;
        RECT  106.272 0 106.296 0.192 ;
    END
  END xbi[51]
  PIN xbi[52]
    DIRECTION INPUT ;
    USE SIGNAL ;
    PORT
      LAYER M3 ;
        RECT  106.56 0 106.578 0.144 ;
    END
  END xbi[52]
  PIN xbi[53]
    DIRECTION INPUT ;
    USE SIGNAL ;
    PORT
      LAYER M5 ;
        RECT  106.848 0 106.872 0.192 ;
    END
  END xbi[53]
  PIN xbi[54]
    DIRECTION INPUT ;
    USE SIGNAL ;
    PORT
      LAYER M3 ;
        RECT  107.136 0 107.154 0.144 ;
    END
  END xbi[54]
  PIN xbi[55]
    DIRECTION INPUT ;
    USE SIGNAL ;
    PORT
      LAYER M5 ;
        RECT  107.424 0 107.448 0.192 ;
    END
  END xbi[55]
  PIN xbi[56]
    DIRECTION INPUT ;
    USE SIGNAL ;
    PORT
      LAYER M3 ;
        RECT  107.712 0 107.73 0.144 ;
    END
  END xbi[56]
  PIN xbi[57]
    DIRECTION INPUT ;
    USE SIGNAL ;
    PORT
      LAYER M5 ;
        RECT  108 0 108.024 0.192 ;
    END
  END xbi[57]
  PIN xbi[58]
    DIRECTION INPUT ;
    USE SIGNAL ;
    PORT
      LAYER M3 ;
        RECT  108.288 0 108.306 0.144 ;
    END
  END xbi[58]
  PIN xbi[59]
    DIRECTION INPUT ;
    USE SIGNAL ;
    PORT
      LAYER M5 ;
        RECT  108.576 0 108.6 0.192 ;
    END
  END xbi[59]
  PIN xbi[5]
    DIRECTION INPUT ;
    USE SIGNAL ;
    PORT
      LAYER M5 ;
        RECT  92.928 0 92.952 0.192 ;
    END
  END xbi[5]
  PIN xbi[60]
    DIRECTION INPUT ;
    USE SIGNAL ;
    PORT
      LAYER M3 ;
        RECT  108.864 0 108.882 0.144 ;
    END
  END xbi[60]
  PIN xbi[61]
    DIRECTION INPUT ;
    USE SIGNAL ;
    PORT
      LAYER M5 ;
        RECT  109.152 0 109.176 0.192 ;
    END
  END xbi[61]
  PIN xbi[62]
    DIRECTION INPUT ;
    USE SIGNAL ;
    PORT
      LAYER M3 ;
        RECT  109.44 0 109.458 0.144 ;
    END
  END xbi[62]
  PIN xbi[63]
    DIRECTION INPUT ;
    USE SIGNAL ;
    PORT
      LAYER M5 ;
        RECT  109.728 0 109.752 0.192 ;
    END
  END xbi[63]
  PIN xbi[64]
    DIRECTION INPUT ;
    USE SIGNAL ;
    PORT
      LAYER M3 ;
        RECT  110.016 0 110.034 0.144 ;
    END
  END xbi[64]
  PIN xbi[65]
    DIRECTION INPUT ;
    USE SIGNAL ;
    PORT
      LAYER M5 ;
        RECT  110.304 0 110.328 0.192 ;
    END
  END xbi[65]
  PIN xbi[66]
    DIRECTION INPUT ;
    USE SIGNAL ;
    PORT
      LAYER M3 ;
        RECT  110.592 0 110.61 0.144 ;
    END
  END xbi[66]
  PIN xbi[67]
    DIRECTION INPUT ;
    USE SIGNAL ;
    PORT
      LAYER M5 ;
        RECT  110.88 0 110.904 0.192 ;
    END
  END xbi[67]
  PIN xbi[68]
    DIRECTION INPUT ;
    USE SIGNAL ;
    PORT
      LAYER M3 ;
        RECT  111.204 0 111.222 0.144 ;
    END
  END xbi[68]
  PIN xbi[69]
    DIRECTION INPUT ;
    USE SIGNAL ;
    PORT
      LAYER M5 ;
        RECT  111.456 0 111.48 0.192 ;
    END
  END xbi[69]
  PIN xbi[6]
    DIRECTION INPUT ;
    USE SIGNAL ;
    PORT
      LAYER M3 ;
        RECT  93.204 0 93.222 0.144 ;
    END
  END xbi[6]
  PIN xbi[70]
    DIRECTION INPUT ;
    USE SIGNAL ;
    PORT
      LAYER M3 ;
        RECT  111.78 0 111.798 0.144 ;
    END
  END xbi[70]
  PIN xbi[71]
    DIRECTION INPUT ;
    USE SIGNAL ;
    PORT
      LAYER M5 ;
        RECT  112.08 0 112.104 0.192 ;
    END
  END xbi[71]
  PIN xbi[72]
    DIRECTION INPUT ;
    USE SIGNAL ;
    PORT
      LAYER M3 ;
        RECT  112.356 0 112.374 0.144 ;
    END
  END xbi[72]
  PIN xbi[73]
    DIRECTION INPUT ;
    USE SIGNAL ;
    PORT
      LAYER M5 ;
        RECT  112.656 0 112.68 0.192 ;
    END
  END xbi[73]
  PIN xbi[74]
    DIRECTION INPUT ;
    USE SIGNAL ;
    PORT
      LAYER M3 ;
        RECT  112.932 0 112.95 0.144 ;
    END
  END xbi[74]
  PIN xbi[75]
    DIRECTION INPUT ;
    USE SIGNAL ;
    PORT
      LAYER M5 ;
        RECT  113.232 0 113.256 0.192 ;
    END
  END xbi[75]
  PIN xbi[76]
    DIRECTION INPUT ;
    USE SIGNAL ;
    PORT
      LAYER M3 ;
        RECT  113.508 0 113.526 0.144 ;
    END
  END xbi[76]
  PIN xbi[77]
    DIRECTION INPUT ;
    USE SIGNAL ;
    PORT
      LAYER M5 ;
        RECT  113.808 0 113.832 0.192 ;
    END
  END xbi[77]
  PIN xbi[78]
    DIRECTION INPUT ;
    USE SIGNAL ;
    PORT
      LAYER M3 ;
        RECT  114.084 0 114.102 0.144 ;
    END
  END xbi[78]
  PIN xbi[79]
    DIRECTION INPUT ;
    USE SIGNAL ;
    PORT
      LAYER M5 ;
        RECT  114.384 0 114.408 0.192 ;
    END
  END xbi[79]
  PIN xbi[7]
    DIRECTION INPUT ;
    USE SIGNAL ;
    PORT
      LAYER M5 ;
        RECT  93.504 0 93.528 0.192 ;
    END
  END xbi[7]
  PIN xbi[80]
    DIRECTION INPUT ;
    USE SIGNAL ;
    PORT
      LAYER M3 ;
        RECT  114.66 0 114.678 0.144 ;
    END
  END xbi[80]
  PIN xbi[81]
    DIRECTION INPUT ;
    USE SIGNAL ;
    PORT
      LAYER M5 ;
        RECT  114.96 0 114.984 0.192 ;
    END
  END xbi[81]
  PIN xbi[82]
    DIRECTION INPUT ;
    USE SIGNAL ;
    PORT
      LAYER M3 ;
        RECT  115.236 0 115.254 0.144 ;
    END
  END xbi[82]
  PIN xbi[83]
    DIRECTION INPUT ;
    USE SIGNAL ;
    PORT
      LAYER M5 ;
        RECT  115.536 0 115.56 0.192 ;
    END
  END xbi[83]
  PIN xbi[84]
    DIRECTION INPUT ;
    USE SIGNAL ;
    PORT
      LAYER M3 ;
        RECT  115.812 0 115.83 0.144 ;
    END
  END xbi[84]
  PIN xbi[85]
    DIRECTION INPUT ;
    USE SIGNAL ;
    PORT
      LAYER M5 ;
        RECT  116.112 0 116.136 0.192 ;
    END
  END xbi[85]
  PIN xbi[86]
    DIRECTION INPUT ;
    USE SIGNAL ;
    PORT
      LAYER M3 ;
        RECT  116.424 0 116.442 0.144 ;
    END
  END xbi[86]
  PIN xbi[87]
    DIRECTION INPUT ;
    USE SIGNAL ;
    PORT
      LAYER M5 ;
        RECT  116.688 0 116.712 0.192 ;
    END
  END xbi[87]
  PIN xbi[88]
    DIRECTION INPUT ;
    USE SIGNAL ;
    PORT
      LAYER M3 ;
        RECT  117 0 117.018 0.144 ;
    END
  END xbi[88]
  PIN xbi[89]
    DIRECTION INPUT ;
    USE SIGNAL ;
    PORT
      LAYER M5 ;
        RECT  117.264 0 117.288 0.192 ;
    END
  END xbi[89]
  PIN xbi[8]
    DIRECTION INPUT ;
    USE SIGNAL ;
    PORT
      LAYER M3 ;
        RECT  93.78 0 93.798 0.144 ;
    END
  END xbi[8]
  PIN xbi[90]
    DIRECTION INPUT ;
    USE SIGNAL ;
    PORT
      LAYER M3 ;
        RECT  117.576 0 117.594 0.144 ;
    END
  END xbi[90]
  PIN xbi[91]
    DIRECTION INPUT ;
    USE SIGNAL ;
    PORT
      LAYER M5 ;
        RECT  117.84 0 117.864 0.192 ;
    END
  END xbi[91]
  PIN xbi[92]
    DIRECTION INPUT ;
    USE SIGNAL ;
    PORT
      LAYER M3 ;
        RECT  118.152 0 118.17 0.144 ;
    END
  END xbi[92]
  PIN xbi[93]
    DIRECTION INPUT ;
    USE SIGNAL ;
    PORT
      LAYER M5 ;
        RECT  118.416 0 118.44 0.192 ;
    END
  END xbi[93]
  PIN xbi[94]
    DIRECTION INPUT ;
    USE SIGNAL ;
    PORT
      LAYER M3 ;
        RECT  118.728 0 118.746 0.144 ;
    END
  END xbi[94]
  PIN xbi[95]
    DIRECTION INPUT ;
    USE SIGNAL ;
    PORT
      LAYER M5 ;
        RECT  119.04 0 119.064 0.192 ;
    END
  END xbi[95]
  PIN xbi[96]
    DIRECTION INPUT ;
    USE SIGNAL ;
    PORT
      LAYER M3 ;
        RECT  119.304 0 119.322 0.144 ;
    END
  END xbi[96]
  PIN xbi[97]
    DIRECTION INPUT ;
    USE SIGNAL ;
    PORT
      LAYER M5 ;
        RECT  119.616 0 119.64 0.192 ;
    END
  END xbi[97]
  PIN xbi[98]
    DIRECTION INPUT ;
    USE SIGNAL ;
    PORT
      LAYER M3 ;
        RECT  119.88 0 119.898 0.144 ;
    END
  END xbi[98]
  PIN xbi[99]
    DIRECTION INPUT ;
    USE SIGNAL ;
    PORT
      LAYER M5 ;
        RECT  120.192 0 120.216 0.192 ;
    END
  END xbi[99]
  PIN xbi[9]
    DIRECTION INPUT ;
    USE SIGNAL ;
    PORT
      LAYER M5 ;
        RECT  94.08 0 94.104 0.192 ;
    END
  END xbi[9]
  PIN VDD
    DIRECTION INOUT ;
    USE POWER ;
    PORT
      LAYER M5 ;
        RECT  169.992 2.151 170.112 28.089 ;
        RECT  167.292 2.151 167.412 28.089 ;
        RECT  164.592 2.151 164.712 28.089 ;
        RECT  161.892 2.151 162.012 28.089 ;
        RECT  159.192 2.151 159.312 28.089 ;
        RECT  156.492 2.151 156.612 28.089 ;
        RECT  153.792 2.151 153.912 28.089 ;
        RECT  151.092 2.151 151.212 28.089 ;
        RECT  148.392 2.151 148.512 28.089 ;
        RECT  145.692 2.151 145.812 28.089 ;
        RECT  142.992 2.151 143.112 28.089 ;
        RECT  140.292 2.151 140.412 28.089 ;
        RECT  137.592 2.151 137.712 28.089 ;
        RECT  134.892 2.151 135.012 28.089 ;
        RECT  132.192 2.151 132.312 28.089 ;
        RECT  129.492 2.151 129.612 28.089 ;
        RECT  126.792 2.151 126.912 28.089 ;
        RECT  124.092 2.151 124.212 28.089 ;
        RECT  121.392 2.151 121.512 28.089 ;
        RECT  118.692 2.151 118.812 28.089 ;
        RECT  115.992 2.151 116.112 28.089 ;
        RECT  113.292 2.151 113.412 28.089 ;
        RECT  110.592 2.151 110.712 28.089 ;
        RECT  107.892 2.151 108.012 28.089 ;
        RECT  105.192 2.151 105.312 28.089 ;
        RECT  102.492 2.151 102.612 28.089 ;
        RECT  99.792 2.151 99.912 28.089 ;
        RECT  97.092 2.151 97.212 28.089 ;
        RECT  94.392 2.151 94.512 28.089 ;
        RECT  91.692 2.151 91.812 28.089 ;
        RECT  88.992 2.151 89.112 28.089 ;
        RECT  86.292 2.151 86.412 28.089 ;
        RECT  83.592 2.151 83.712 28.089 ;
        RECT  80.892 2.151 81.012 28.089 ;
        RECT  78.192 2.151 78.312 28.089 ;
        RECT  75.492 2.151 75.612 28.089 ;
        RECT  72.792 2.151 72.912 28.089 ;
        RECT  70.092 2.151 70.212 28.089 ;
        RECT  67.392 2.151 67.512 28.089 ;
        RECT  64.692 2.151 64.812 28.089 ;
        RECT  61.992 2.151 62.112 28.089 ;
        RECT  59.292 2.151 59.412 28.089 ;
        RECT  56.592 2.151 56.712 28.089 ;
        RECT  53.892 2.151 54.012 28.089 ;
        RECT  51.192 2.151 51.312 28.089 ;
        RECT  48.492 2.151 48.612 28.089 ;
        RECT  45.792 2.151 45.912 28.089 ;
        RECT  43.092 2.151 43.212 28.089 ;
        RECT  40.392 2.151 40.512 28.089 ;
        RECT  37.692 2.151 37.812 28.089 ;
        RECT  34.992 2.151 35.112 28.089 ;
        RECT  32.292 2.151 32.412 28.089 ;
        RECT  29.592 2.151 29.712 28.089 ;
        RECT  26.892 2.151 27.012 28.089 ;
        RECT  24.192 2.151 24.312 28.089 ;
        RECT  21.492 2.151 21.612 28.089 ;
        RECT  18.792 2.151 18.912 28.089 ;
        RECT  16.092 2.151 16.212 28.089 ;
        RECT  13.392 2.151 13.512 28.089 ;
        RECT  10.692 2.151 10.812 28.089 ;
        RECT  7.992 2.151 8.112 28.089 ;
        RECT  5.292 2.151 5.412 28.089 ;
        RECT  2.592 2.151 2.712 28.089 ;
    END
  END VDD
  PIN VSS
    DIRECTION INOUT ;
    USE GROUND ;
    PORT
      LAYER M5 ;
        RECT  169.8 2.137 169.92 28.103 ;
        RECT  167.1 2.137 167.22 28.103 ;
        RECT  164.4 2.137 164.52 28.103 ;
        RECT  161.7 2.137 161.82 28.103 ;
        RECT  159 2.137 159.12 28.103 ;
        RECT  156.3 2.137 156.42 28.103 ;
        RECT  153.6 2.137 153.72 28.103 ;
        RECT  150.9 2.137 151.02 28.103 ;
        RECT  148.2 2.137 148.32 28.103 ;
        RECT  145.5 2.137 145.62 28.103 ;
        RECT  142.8 2.137 142.92 28.103 ;
        RECT  140.1 2.137 140.22 28.103 ;
        RECT  137.4 2.137 137.52 28.103 ;
        RECT  134.7 2.137 134.82 28.103 ;
        RECT  132 2.137 132.12 28.103 ;
        RECT  129.3 2.137 129.42 28.103 ;
        RECT  126.6 2.137 126.72 28.103 ;
        RECT  123.9 2.137 124.02 28.103 ;
        RECT  121.2 2.137 121.32 28.103 ;
        RECT  118.5 2.137 118.62 28.103 ;
        RECT  115.8 2.137 115.92 28.103 ;
        RECT  113.1 2.137 113.22 28.103 ;
        RECT  110.4 2.137 110.52 28.103 ;
        RECT  107.7 2.137 107.82 28.103 ;
        RECT  105 2.137 105.12 28.103 ;
        RECT  102.3 2.137 102.42 28.103 ;
        RECT  99.6 2.137 99.72 28.103 ;
        RECT  96.9 2.137 97.02 28.103 ;
        RECT  94.2 2.137 94.32 28.103 ;
        RECT  91.5 2.137 91.62 28.103 ;
        RECT  88.8 2.137 88.92 28.103 ;
        RECT  86.1 2.137 86.22 28.103 ;
        RECT  83.4 2.137 83.52 28.103 ;
        RECT  80.7 2.137 80.82 28.103 ;
        RECT  78 2.137 78.12 28.103 ;
        RECT  75.3 2.137 75.42 28.103 ;
        RECT  72.6 2.137 72.72 28.103 ;
        RECT  69.9 2.137 70.02 28.103 ;
        RECT  67.2 2.137 67.32 28.103 ;
        RECT  64.5 2.137 64.62 28.103 ;
        RECT  61.8 2.137 61.92 28.103 ;
        RECT  59.1 2.137 59.22 28.103 ;
        RECT  56.4 2.137 56.52 28.103 ;
        RECT  53.7 2.137 53.82 28.103 ;
        RECT  51 2.137 51.12 28.103 ;
        RECT  48.3 2.137 48.42 28.103 ;
        RECT  45.6 2.137 45.72 28.103 ;
        RECT  42.9 2.137 43.02 28.103 ;
        RECT  40.2 2.137 40.32 28.103 ;
        RECT  37.5 2.137 37.62 28.103 ;
        RECT  34.8 2.137 34.92 28.103 ;
        RECT  32.1 2.137 32.22 28.103 ;
        RECT  29.4 2.137 29.52 28.103 ;
        RECT  26.7 2.137 26.82 28.103 ;
        RECT  24 2.137 24.12 28.103 ;
        RECT  21.3 2.137 21.42 28.103 ;
        RECT  18.6 2.137 18.72 28.103 ;
        RECT  15.9 2.137 16.02 28.103 ;
        RECT  13.2 2.137 13.32 28.103 ;
        RECT  10.5 2.137 10.62 28.103 ;
        RECT  7.8 2.137 7.92 28.103 ;
        RECT  5.1 2.137 5.22 28.103 ;
        RECT  2.4 2.137 2.52 28.103 ;
    END
  END VSS
  # OT_OBS_CLOSED layer=M5 d_um=1.536 added=287
  OBS
    LAYER RVTN ;
     RECT  2.16 2.16 170.64 2.295 ;
     RECT  2.16 2.565 170.64 2.835 ;
     RECT  2.16 3.105 170.64 3.375 ;
     RECT  2.16 3.645 170.64 3.915 ;
     RECT  2.16 4.185 170.64 4.455 ;
     RECT  2.16 4.725 170.64 4.995 ;
     RECT  2.16 5.265 170.64 5.535 ;
     RECT  2.16 5.805 170.64 6.075 ;
     RECT  2.16 6.345 170.64 6.615 ;
     RECT  2.16 6.885 170.64 7.155 ;
     RECT  2.16 7.425 170.64 7.695 ;
     RECT  2.16 7.965 170.64 8.235 ;
     RECT  2.16 8.505 170.64 8.775 ;
     RECT  2.16 9.045 170.64 9.315 ;
     RECT  2.16 9.585 170.64 9.855 ;
     RECT  2.16 10.125 170.64 10.395 ;
     RECT  2.16 10.665 170.64 10.935 ;
     RECT  2.16 11.205 170.64 11.475 ;
     RECT  2.16 11.745 170.64 12.015 ;
     RECT  2.16 12.285 170.64 12.555 ;
     RECT  2.16 12.825 170.64 13.095 ;
     RECT  2.16 13.365 170.64 13.635 ;
     RECT  2.16 13.905 170.64 14.175 ;
     RECT  2.16 14.445 170.64 14.715 ;
     RECT  2.16 14.985 170.64 15.255 ;
     RECT  2.16 15.525 170.64 15.795 ;
     RECT  2.16 16.065 170.64 16.335 ;
     RECT  2.16 16.605 170.64 16.875 ;
     RECT  2.16 17.145 170.64 17.415 ;
     RECT  2.16 17.685 170.64 17.955 ;
     RECT  2.16 18.225 170.64 18.495 ;
     RECT  2.16 18.765 170.64 19.035 ;
     RECT  2.16 19.305 170.64 19.575 ;
     RECT  2.16 19.845 170.64 20.115 ;
     RECT  2.16 20.385 170.64 20.655 ;
     RECT  2.16 20.925 170.64 21.195 ;
     RECT  2.16 21.465 170.64 21.735 ;
     RECT  2.16 22.005 170.64 22.275 ;
     RECT  2.16 22.545 170.64 22.815 ;
     RECT  2.16 23.085 170.64 23.355 ;
     RECT  2.16 23.625 170.64 23.895 ;
     RECT  2.16 24.165 170.64 24.435 ;
     RECT  2.16 24.705 170.64 24.975 ;
     RECT  2.16 25.245 170.64 25.515 ;
     RECT  2.16 25.785 170.64 26.055 ;
     RECT  2.16 26.325 170.64 26.595 ;
     RECT  2.16 26.865 170.64 27.135 ;
     RECT  2.16 27.405 170.64 27.675 ;
     RECT  2.16 27.945 170.64 28.08 ;
    LAYER RVTP ;
     RECT  2.16 2.295 170.64 2.565 ;
     RECT  2.16 2.835 170.64 3.105 ;
     RECT  2.16 3.375 170.64 3.645 ;
     RECT  2.16 3.915 170.64 4.185 ;
     RECT  2.16 4.455 170.64 4.725 ;
     RECT  2.16 4.995 170.64 5.265 ;
     RECT  2.16 5.535 170.64 5.805 ;
     RECT  2.16 6.075 170.64 6.345 ;
     RECT  2.16 6.615 170.64 6.885 ;
     RECT  2.16 7.155 170.64 7.425 ;
     RECT  2.16 7.695 170.64 7.965 ;
     RECT  2.16 8.235 170.64 8.505 ;
     RECT  2.16 8.775 170.64 9.045 ;
     RECT  2.16 9.315 170.64 9.585 ;
     RECT  2.16 9.855 170.64 10.125 ;
     RECT  2.16 10.395 170.64 10.665 ;
     RECT  2.16 10.935 170.64 11.205 ;
     RECT  2.16 11.475 170.64 11.745 ;
     RECT  2.16 12.015 170.64 12.285 ;
     RECT  2.16 12.555 170.64 12.825 ;
     RECT  2.16 13.095 170.64 13.365 ;
     RECT  2.16 13.635 170.64 13.905 ;
     RECT  2.16 14.175 170.64 14.445 ;
     RECT  2.16 14.715 170.64 14.985 ;
     RECT  2.16 15.255 170.64 15.525 ;
     RECT  2.16 15.795 170.64 16.065 ;
     RECT  2.16 16.335 170.64 16.605 ;
     RECT  2.16 16.875 170.64 17.145 ;
     RECT  2.16 17.415 170.64 17.685 ;
     RECT  2.16 17.955 170.64 18.225 ;
     RECT  2.16 18.495 170.64 18.765 ;
     RECT  2.16 19.035 170.64 19.305 ;
     RECT  2.16 19.575 170.64 19.845 ;
     RECT  2.16 20.115 170.64 20.385 ;
     RECT  2.16 20.655 170.64 20.925 ;
     RECT  2.16 21.195 170.64 21.465 ;
     RECT  2.16 21.735 170.64 22.005 ;
     RECT  2.16 22.275 170.64 22.545 ;
     RECT  2.16 22.815 170.64 23.085 ;
     RECT  2.16 23.355 170.64 23.625 ;
     RECT  2.16 23.895 170.64 24.165 ;
     RECT  2.16 24.435 170.64 24.705 ;
     RECT  2.16 24.975 170.64 25.245 ;
     RECT  2.16 25.515 170.64 25.785 ;
     RECT  2.16 26.055 170.64 26.325 ;
     RECT  2.16 26.595 170.64 26.865 ;
     RECT  2.16 27.135 170.64 27.405 ;
     RECT  2.16 27.675 170.64 27.945 ;
    LAYER M1 ;
     RECT  2.16 2.151 170.64 28.089 ;
    LAYER M2 ;
     RECT  0.211 20.322 2.16 20.34 ;
     RECT  2.16 2.151 4.243 28.089 ;
     RECT  4.243 1.728 4.487 28.089 ;
     RECT  4.487 2.151 7.771 28.089 ;
     RECT  7.771 1.728 7.879 28.089 ;
     RECT  7.879 1.728 7.943 28.17 ;
     RECT  7.943 2.151 7.979 28.17 ;
     RECT  9.031 0.144 9.131 0.162 ;
     RECT  7.979 2.151 12.559 28.089 ;
     RECT  12.559 1.728 12.803 28.089 ;
     RECT  12.803 2.151 17.779 28.089 ;
     RECT  17.779 1.728 18.023 28.089 ;
     RECT  18.067 29.034 18.203 29.052 ;
     RECT  18.023 2.151 19.543 28.089 ;
     RECT  19.543 1.728 19.715 28.089 ;
     RECT  19.715 2.106 20.435 28.089 ;
     RECT  22.063 29.034 22.775 29.052 ;
     RECT  20.435 2.151 22.999 28.089 ;
     RECT  22.999 1.728 23.171 28.089 ;
     RECT  25.987 29.034 26.771 29.052 ;
     RECT  23.171 2.151 27.319 28.089 ;
     RECT  27.319 2.151 27.419 28.359 ;
     RECT  27.419 2.151 28.543 28.089 ;
     RECT  28.543 1.728 28.859 28.089 ;
     RECT  29.335 0.144 29.435 0.162 ;
     RECT  28.859 2.106 30.191 28.089 ;
     RECT  30.191 2.151 32.395 28.089 ;
     RECT  32.395 29.196 32.495 29.214 ;
     RECT  32.395 2.151 32.711 28.44 ;
     RECT  32.711 2.151 35.779 28.089 ;
     RECT  35.779 1.728 35.915 28.089 ;
     RECT  34.195 29.034 36.239 29.052 ;
     RECT  37.399 0.144 37.535 0.162 ;
     RECT  35.915 2.151 37.615 28.089 ;
     RECT  37.615 2.151 37.967 28.17 ;
     RECT  37.967 2.151 39.307 28.089 ;
     RECT  39.307 2.106 39.343 28.089 ;
     RECT  39.343 2.106 39.623 28.134 ;
     RECT  39.623 2.106 40.919 28.089 ;
     RECT  40.919 2.151 41.791 28.089 ;
     RECT  41.791 2.106 42.223 28.089 ;
     RECT  42.223 2.034 43.367 28.089 ;
     RECT  43.367 2.151 45.571 28.089 ;
     RECT  45.571 2.106 45.643 28.089 ;
     RECT  45.643 1.728 45.779 28.089 ;
     RECT  45.643 29.034 46.139 29.052 ;
     RECT  45.779 2.106 46.823 28.089 ;
     RECT  46.795 0.144 46.895 0.162 ;
     RECT  47.767 29.034 47.867 29.052 ;
     RECT  46.823 2.151 48.271 28.089 ;
     RECT  48.271 2.106 48.947 28.089 ;
     RECT  48.947 2.151 52.987 28.089 ;
     RECT  52.987 2.106 53.455 28.089 ;
     RECT  53.455 2.034 53.671 28.089 ;
     RECT  53.671 1.728 53.771 28.089 ;
     RECT  53.771 2.034 54.527 28.089 ;
     RECT  54.527 2.106 55.507 28.089 ;
     RECT  55.507 1.728 55.679 28.089 ;
     RECT  55.679 2.034 56.515 28.089 ;
     RECT  56.515 2.034 56.867 28.17 ;
     RECT  56.867 2.151 56.939 28.17 ;
     RECT  56.939 2.151 57.991 28.089 ;
     RECT  57.991 2.106 58.775 28.089 ;
     RECT  58.775 2.151 61.519 28.089 ;
     RECT  61.771 0.144 61.907 0.162 ;
     RECT  61.519 2.106 62.627 28.089 ;
     RECT  63.319 30.15 63.355 30.168 ;
     RECT  63.355 30.078 63.455 30.168 ;
     RECT  62.627 2.151 64.183 28.089 ;
     RECT  64.183 1.728 64.319 28.089 ;
     RECT  64.319 2.106 64.507 28.089 ;
     RECT  64.507 2.106 64.931 28.17 ;
     RECT  64.931 2.106 66.407 28.089 ;
     RECT  66.407 2.151 67.603 28.089 ;
     RECT  69.079 29.034 69.287 29.052 ;
     RECT  69.871 0.144 70.043 0.162 ;
     RECT  67.603 2.106 70.879 28.089 ;
     RECT  70.879 1.728 71.195 28.089 ;
     RECT  71.383 29.034 72.527 29.052 ;
     RECT  71.195 2.151 73.723 28.089 ;
     RECT  73.723 1.728 74.075 28.089 ;
     RECT  74.075 2.151 75.271 28.089 ;
     RECT  75.271 2.151 75.407 28.17 ;
     RECT  76.963 0.144 77.063 0.162 ;
     RECT  75.407 2.151 77.503 28.089 ;
     RECT  78.115 0.144 78.215 0.162 ;
     RECT  77.503 2.106 78.395 28.089 ;
     RECT  78.395 2.151 80.455 28.089 ;
     RECT  80.455 1.728 80.627 28.089 ;
     RECT  81.103 29.034 81.311 29.052 ;
     RECT  80.627 2.106 82.183 28.089 ;
     RECT  82.183 1.728 82.355 28.089 ;
     RECT  82.255 29.034 83.399 29.052 ;
     RECT  82.355 2.106 83.867 28.089 ;
     RECT  83.867 2.151 85.675 28.089 ;
     RECT  85.675 1.728 85.811 28.089 ;
     RECT  85.811 2.151 87.403 28.089 ;
     RECT  87.403 1.728 87.539 28.089 ;
     RECT  87.539 2.151 93.487 28.089 ;
     RECT  93.487 2.106 94.055 28.089 ;
     RECT  94.819 28.962 94.963 28.98 ;
     RECT  94.963 28.962 94.991 29.052 ;
     RECT  94.991 29.034 95.063 29.052 ;
     RECT  94.055 2.151 95.215 28.089 ;
     RECT  95.215 2.106 96.115 28.089 ;
     RECT  95.971 29.034 96.143 29.052 ;
     RECT  96.115 1.728 96.215 28.089 ;
     RECT  96.215 2.151 98.239 28.089 ;
     RECT  98.239 2.106 98.923 28.089 ;
     RECT  98.923 2.034 100.471 28.089 ;
     RECT  99.391 29.034 100.715 29.052 ;
     RECT  100.471 1.728 100.787 28.089 ;
     RECT  100.787 2.106 100.823 28.089 ;
     RECT  100.823 2.151 102.883 28.089 ;
     RECT  102.883 2.106 103.639 28.089 ;
     RECT  103.639 2.07 103.847 28.089 ;
     RECT  103.847 2.106 104.423 28.089 ;
     RECT  104.423 2.151 104.647 28.089 ;
     RECT  104.647 2.151 105.143 28.512 ;
     RECT  105.143 2.151 106.771 28.089 ;
     RECT  107.383 0.144 107.735 0.162 ;
     RECT  106.771 2.106 108.059 28.089 ;
     RECT  108.059 2.151 109.255 28.089 ;
     RECT  109.255 2.106 111.263 28.089 ;
     RECT  112.927 29.034 113.783 29.052 ;
     RECT  114.835 29.034 115.367 29.052 ;
     RECT  111.263 2.151 115.807 28.089 ;
     RECT  115.807 1.728 115.979 28.089 ;
     RECT  117.715 29.736 117.923 29.754 ;
     RECT  115.979 2.151 120.343 28.089 ;
     RECT  120.343 1.728 120.479 28.089 ;
     RECT  120.479 2.151 121.423 28.089 ;
     RECT  121.423 1.728 121.667 28.089 ;
     RECT  121.711 29.034 122.423 29.052 ;
     RECT  121.667 2.151 123.367 28.089 ;
     RECT  123.367 1.728 123.539 28.089 ;
     RECT  123.439 29.034 123.539 29.052 ;
     RECT  123.871 0.144 123.971 0.162 ;
     RECT  123.539 2.151 123.979 28.089 ;
     RECT  123.979 2.151 124.079 28.17 ;
     RECT  124.555 29.034 124.727 29.052 ;
     RECT  124.079 2.151 128.443 28.089 ;
     RECT  128.443 1.728 128.615 28.089 ;
     RECT  129.703 29.034 129.803 29.052 ;
     RECT  130.639 29.034 130.883 29.052 ;
     RECT  131.935 29.034 132.035 29.052 ;
     RECT  131.971 0.144 132.107 0.162 ;
     RECT  128.615 2.151 133.807 28.089 ;
     RECT  133.807 1.728 133.907 28.089 ;
     RECT  133.907 2.151 135.247 28.089 ;
     RECT  135.247 1.728 135.563 28.089 ;
     RECT  140.071 0.144 140.207 0.162 ;
     RECT  135.563 2.151 142.879 28.089 ;
     RECT  142.879 2.151 143.195 28.17 ;
     RECT  148.315 0.144 148.415 0.162 ;
     RECT  149.179 29.736 149.315 29.754 ;
     RECT  152.959 29.736 153.203 29.754 ;
     RECT  153.535 29.034 153.779 29.052 ;
     RECT  156.271 0.144 156.443 0.162 ;
     RECT  157.099 29.034 157.199 29.052 ;
     RECT  159.331 0.144 159.431 0.162 ;
     RECT  143.195 2.151 159.475 28.089 ;
     RECT  159.475 2.151 159.575 28.278 ;
     RECT  159.871 29.034 160.043 29.052 ;
     RECT  159.575 2.151 160.483 28.089 ;
     RECT  160.483 1.728 160.691 28.089 ;
     RECT  160.691 2.151 161.527 28.089 ;
     RECT  161.527 2.151 161.771 28.17 ;
     RECT  161.771 2.151 165.739 28.089 ;
     RECT  165.739 2.151 168.719 28.782 ;
     RECT  168.719 2.151 170.64 28.089 ;
     RECT  170.64 15.156 172.175 15.174 ;
    LAYER M3 ;
     RECT  4.464 0.108 168.066 0.167 ;
     RECT  4.464 0.167 107.406 1.723 ;
     RECT  108.144 0.167 156.294 1.723 ;
     RECT  157.032 0.167 168.066 1.723 ;
     RECT  4.248 1.723 168.426 2.255 ;
     RECT  4.356 2.255 168.426 2.371 ;
     RECT  2.415 2.143 2.505 2.413 ;
     RECT  169.815 2.143 169.905 2.413 ;
     RECT  4.356 2.371 168.534 2.489 ;
     RECT  4.716 2.489 168.534 2.641 ;
     RECT  4.716 2.641 168.894 2.795 ;
     RECT  37.008 2.795 52.65 2.831 ;
     RECT  53.424 2.795 79.902 2.831 ;
     RECT  82.08 2.795 149.958 2.831 ;
     RECT  4.716 2.795 36.162 2.861 ;
     RECT  37.008 2.831 38.106 2.861 ;
     RECT  80.715 2.795 81.27 2.861 ;
     RECT  82.08 2.831 82.134 2.861 ;
     RECT  37.404 2.861 37.797 2.903 ;
     RECT  80.715 2.861 81.198 10.831 ;
     RECT  32.115 2.861 32.397 13.099 ;
     RECT  33.84 13.099 33.858 13.525 ;
     RECT  32.115 13.099 32.922 13.627 ;
     RECT  33.84 13.525 34.038 13.627 ;
     RECT  80.715 10.831 81.27 13.627 ;
     RECT  32.115 13.627 34.038 13.667 ;
     RECT  80.715 13.627 81.306 13.667 ;
     RECT  32.115 13.667 32.562 13.675 ;
     RECT  33.66 13.667 34.038 13.675 ;
     RECT  34.815 2.861 35.097 13.675 ;
     RECT  53.424 2.831 75.87 13.675 ;
     RECT  37.515 2.903 37.797 13.723 ;
     RECT  29.415 2.861 30.438 13.981 ;
     RECT  36.252 13.675 36.27 13.981 ;
     RECT  37.116 13.723 37.797 13.981 ;
     RECT  53.424 13.675 76.086 14.071 ;
     RECT  76.824 2.831 79.902 14.071 ;
     RECT  4.716 2.861 28.386 14.251 ;
     RECT  29.415 13.981 30.582 14.251 ;
     RECT  31.392 13.675 32.562 14.251 ;
     RECT  33.66 13.675 35.097 14.251 ;
     RECT  36.252 13.981 37.998 14.251 ;
     RECT  38.88 2.831 52.65 14.251 ;
     RECT  82.08 2.861 82.098 14.251 ;
     RECT  4.716 14.251 28.458 14.299 ;
     RECT  29.415 14.251 32.562 14.299 ;
     RECT  80.715 13.667 81.27 14.369 ;
     RECT  53.424 14.071 79.902 14.521 ;
     RECT  82.908 2.831 149.958 14.521 ;
     RECT  150.696 2.795 168.894 14.521 ;
     RECT  53.424 14.521 79.974 14.573 ;
     RECT  4.716 14.299 32.562 14.675 ;
     RECT  33.66 14.251 52.65 14.675 ;
     RECT  82.08 14.251 82.134 14.779 ;
     RECT  82.908 14.521 169.002 14.779 ;
     RECT  33.66 14.675 33.894 14.813 ;
     RECT  34.704 14.675 52.65 14.813 ;
     RECT  76.824 14.573 79.974 14.813 ;
     RECT  34.704 14.813 35.73 14.819 ;
     RECT  36.468 14.813 52.65 14.819 ;
     RECT  22.392 14.675 32.562 14.917 ;
     RECT  4.716 14.675 21.597 14.945 ;
     RECT  22.392 14.917 32.886 14.945 ;
     RECT  34.74 14.819 35.73 14.945 ;
     RECT  36.468 14.819 38.106 14.945 ;
     RECT  23.868 14.945 32.886 14.971 ;
     RECT  4.716 14.945 11.826 15.061 ;
     RECT  172.152 15.115 172.17 15.179 ;
     RECT  23.868 14.971 33.462 15.389 ;
     RECT  34.815 14.945 35.73 15.389 ;
     RECT  36.684 14.945 38.106 15.389 ;
     RECT  82.08 14.779 169.002 15.389 ;
     RECT  2.415 2.413 2.697 20.461 ;
     RECT  0.216 20.317 0.234 20.573 ;
     RECT  2.304 20.461 2.697 20.885 ;
     RECT  38.88 14.819 52.65 22.919 ;
     RECT  4.68 15.061 11.826 23.819 ;
     RECT  34.815 15.389 35.097 23.947 ;
     RECT  34.416 23.947 35.097 24.469 ;
     RECT  34.272 24.469 35.097 24.511 ;
     RECT  37.515 15.389 37.797 24.523 ;
     RECT  80.715 14.369 81.198 24.523 ;
     RECT  82.08 15.389 82.098 24.523 ;
     RECT  33.444 24.523 33.462 24.619 ;
     RECT  37.515 24.523 38.394 24.673 ;
     RECT  39.168 22.919 52.65 24.673 ;
     RECT  37.515 24.673 52.65 24.709 ;
     RECT  53.424 14.573 75.87 24.709 ;
     RECT  34.272 24.511 35.226 24.781 ;
     RECT  80.715 24.523 82.098 24.781 ;
     RECT  82.908 15.389 169.002 24.781 ;
     RECT  31.464 15.389 32.397 24.811 ;
     RECT  33.3 24.619 33.462 24.811 ;
     RECT  76.824 14.813 79.902 24.907 ;
     RECT  80.715 24.781 169.002 24.907 ;
     RECT  36.684 24.523 36.702 25.003 ;
     RECT  12.564 14.945 21.597 25.045 ;
     RECT  22.392 14.945 23.13 25.045 ;
     RECT  31.464 24.811 33.462 25.051 ;
     RECT  34.2 24.781 35.73 25.051 ;
     RECT  36.54 25.003 36.702 25.051 ;
     RECT  37.515 24.709 75.87 25.051 ;
     RECT  23.868 15.389 30.33 25.099 ;
     RECT  31.464 25.051 36.702 25.099 ;
     RECT  37.476 25.051 75.906 25.099 ;
     RECT  23.868 25.099 36.702 25.285 ;
     RECT  37.476 25.099 76.086 25.285 ;
     RECT  76.824 24.907 169.002 25.285 ;
     RECT  12.564 25.045 23.13 25.321 ;
     RECT  23.868 25.285 169.002 25.321 ;
     RECT  4.68 23.819 8.802 25.591 ;
     RECT  9.576 23.819 11.826 25.591 ;
     RECT  4.68 25.591 11.826 25.681 ;
     RECT  12.564 25.321 169.002 25.681 ;
     RECT  4.68 25.681 169.002 25.709 ;
     RECT  169.815 2.413 170.097 25.861 ;
     RECT  4.68 25.709 168.57 26.221 ;
     RECT  4.572 26.221 168.57 26.671 ;
     RECT  169.488 25.861 170.097 26.671 ;
     RECT  4.572 26.671 170.097 26.779 ;
     RECT  4.356 26.779 170.097 26.825 ;
     RECT  2.415 20.885 2.697 27.827 ;
     RECT  4.572 26.825 170.097 27.827 ;
     RECT  4.572 27.827 169.905 27.869 ;
     RECT  4.572 27.869 114.282 27.877 ;
     RECT  4.464 27.877 114.282 27.941 ;
     RECT  115.128 27.869 165.366 27.941 ;
     RECT  4.464 27.941 43.434 27.965 ;
     RECT  44.424 27.941 114.282 27.965 ;
     RECT  2.415 27.827 2.505 28.097 ;
     RECT  82.44 27.965 114.282 28.097 ;
     RECT  115.128 27.941 165.186 28.097 ;
     RECT  166.32 27.869 169.905 28.097 ;
     RECT  94.824 28.097 114.282 28.205 ;
     RECT  44.424 27.965 81.702 28.253 ;
     RECT  166.32 28.097 169.29 28.253 ;
     RECT  44.424 28.253 80.55 28.541 ;
     RECT  154.332 28.097 165.186 28.759 ;
     RECT  166.32 28.253 168.714 28.759 ;
     RECT  154.332 28.759 168.714 28.787 ;
     RECT  94.968 28.205 114.282 28.957 ;
     RECT  44.496 28.541 80.55 29.029 ;
     RECT  81.288 28.253 81.702 29.029 ;
     RECT  82.44 28.097 94.014 29.029 ;
     RECT  94.824 28.957 114.282 29.029 ;
     RECT  115.128 28.097 153.558 29.029 ;
     RECT  154.332 28.787 168.066 29.029 ;
     RECT  44.496 29.029 94.014 29.083 ;
     RECT  94.824 29.029 168.066 29.083 ;
     RECT  4.464 27.965 43.362 29.659 ;
     RECT  44.496 29.083 168.066 29.659 ;
     RECT  4.464 29.659 168.066 30.108 ;
    LAYER M4 ;
     RECT  0.229 25.2 2.408 25.224 ;
     RECT  2.408 2.148 2.512 28.092 ;
     RECT  2.512 2.418 2.704 27.822 ;
     RECT  4.345 26.784 4.741 26.808 ;
     RECT  4.633 0.576 4.787 0.6 ;
     RECT  4.741 18.192 5.108 18.216 ;
     RECT  2.704 25.2 5.108 25.224 ;
     RECT  4.741 26.784 5.108 27.384 ;
     RECT  5.108 2.148 5.212 28.092 ;
     RECT  5.212 2.418 5.404 28.092 ;
     RECT  5.404 25.2 5.501 28.092 ;
     RECT  5.501 27.36 5.893 28.092 ;
     RECT  4.993 0.192 5.939 0.216 ;
     RECT  5.893 27.36 6.581 28.536 ;
     RECT  5.501 25.2 6.937 26.28 ;
     RECT  5.317 29.664 7.405 29.688 ;
     RECT  6.937 25.2 7.729 26.328 ;
     RECT  6.581 27.36 7.729 27.864 ;
     RECT  6.397 1.728 7.808 1.752 ;
     RECT  7.729 25.2 7.808 27.864 ;
     RECT  7.808 1.728 7.912 28.092 ;
     RECT  7.912 1.728 8.104 28.056 ;
     RECT  8.104 1.728 8.273 1.752 ;
     RECT  8.104 23.52 8.435 23.736 ;
     RECT  7.405 29.088 8.453 29.688 ;
     RECT  8.737 0.192 8.821 0.216 ;
     RECT  8.435 23.52 8.963 23.544 ;
     RECT  8.104 25.2 9.137 28.056 ;
     RECT  8.104 3.456 9.245 3.48 ;
     RECT  8.453 29.088 9.923 29.208 ;
     RECT  9.923 29.184 10.499 29.208 ;
     RECT  9.349 1.728 10.508 1.752 ;
     RECT  9.137 25.2 10.508 27.96 ;
     RECT  10.508 1.728 10.804 28.092 ;
     RECT  10.804 27.936 11.075 28.092 ;
     RECT  11.401 28.512 11.651 28.536 ;
     RECT  12.697 28.512 12.803 28.536 ;
     RECT  10.804 25.2 13.129 26.664 ;
     RECT  10.804 1.728 13.208 1.752 ;
     RECT  13.129 25.2 13.208 27.384 ;
     RECT  12.085 29.664 13.331 29.688 ;
     RECT  13.208 1.728 13.504 28.092 ;
     RECT  13.504 25.104 13.817 25.752 ;
     RECT  13.861 28.512 13.948 28.536 ;
     RECT  13.504 1.728 14.051 2.28 ;
     RECT  13.504 26.736 14.141 27.384 ;
     RECT  14.141 26.784 14.483 27.384 ;
     RECT  14.483 26.784 15.325 26.808 ;
     RECT  14.051 1.728 15.908 1.752 ;
     RECT  13.817 25.104 15.908 25.224 ;
     RECT  15.325 26.352 15.908 26.808 ;
     RECT  15.589 27.936 15.908 27.96 ;
     RECT  15.908 1.728 16.012 28.092 ;
     RECT  16.012 1.728 16.204 27.96 ;
     RECT  16.204 26.448 16.403 27.96 ;
     RECT  16.403 27.648 16.481 27.96 ;
     RECT  16.481 27.936 16.828 27.96 ;
     RECT  16.165 29.664 17.98 29.688 ;
     RECT  16.403 26.448 18.133 26.472 ;
     RECT  16.204 1.728 18.608 1.752 ;
     RECT  16.204 25.2 18.608 25.32 ;
     RECT  18.133 26.448 18.608 26.616 ;
     RECT  18.428 27.936 18.608 27.96 ;
     RECT  18.608 1.728 18.904 28.092 ;
     RECT  19.045 28.464 19.253 28.488 ;
     RECT  19.621 28.512 19.865 28.536 ;
     RECT  20.149 29.664 20.333 29.688 ;
     RECT  18.904 25.2 21.157 26.616 ;
     RECT  20.725 27.936 21.193 27.96 ;
     RECT  18.904 1.728 21.308 1.752 ;
     RECT  21.157 25.2 21.308 26.664 ;
     RECT  21.193 27.936 21.308 28.248 ;
     RECT  21.308 1.728 21.412 28.248 ;
     RECT  21.412 1.728 21.604 27.912 ;
     RECT  21.604 25.056 21.731 27.912 ;
     RECT  21.731 25.056 21.868 27.096 ;
     RECT  21.868 25.2 21.953 27.096 ;
     RECT  21.877 29.04 22.061 29.064 ;
     RECT  21.604 1.728 22.313 2.232 ;
     RECT  22.412 29.664 22.499 29.688 ;
     RECT  22.313 1.728 24.008 1.752 ;
     RECT  21.953 25.2 24.008 26.76 ;
     RECT  22.988 27.936 24.008 27.96 ;
     RECT  24.008 1.728 24.112 28.092 ;
     RECT  24.112 1.728 24.304 27.96 ;
     RECT  24.181 29.04 24.419 29.064 ;
     RECT  24.304 25.056 24.473 27.96 ;
     RECT  24.473 25.056 24.545 26.664 ;
     RECT  24.473 27.936 24.941 27.96 ;
     RECT  24.545 25.056 25.013 26.28 ;
     RECT  25.013 25.056 25.091 26.184 ;
     RECT  24.304 1.728 25.129 1.752 ;
     RECT  25.333 28.512 25.481 28.536 ;
     RECT  25.091 25.2 26.053 26.184 ;
     RECT  26.125 0.528 26.243 0.552 ;
     RECT  25.909 27.936 26.485 27.96 ;
     RECT  26.485 27.936 26.597 28.488 ;
     RECT  25.621 2.208 26.708 2.232 ;
     RECT  26.053 25.2 26.708 26.568 ;
     RECT  26.597 27.936 26.708 28.092 ;
     RECT  26.708 2.148 26.773 28.092 ;
     RECT  26.773 1.728 26.812 28.092 ;
     RECT  26.812 1.728 27.004 27.96 ;
     RECT  27.013 29.664 27.1 29.688 ;
     RECT  27.004 25.2 27.155 26.856 ;
     RECT  27.155 25.2 27.173 26.184 ;
     RECT  27.004 1.728 27.577 2.28 ;
     RECT  27.925 0.576 28.009 0.6 ;
     RECT  27.004 14.256 28.069 14.28 ;
     RECT  27.173 25.2 28.393 26.04 ;
     RECT  27.004 27.936 28.433 27.96 ;
     RECT  28.393 25.2 28.549 26.232 ;
     RECT  27.577 1.728 28.685 1.752 ;
     RECT  28.709 28.08 28.793 28.488 ;
     RECT  28.069 14.256 28.933 14.856 ;
     RECT  28.933 14.256 29.113 14.904 ;
     RECT  28.793 28.08 29.363 28.2 ;
     RECT  28.033 2.832 29.408 2.856 ;
     RECT  29.113 14.256 29.408 15.384 ;
     RECT  28.549 25.2 29.408 26.376 ;
     RECT  29.363 28.08 29.408 28.092 ;
     RECT  29.408 2.148 29.512 28.092 ;
     RECT  29.512 2.148 29.653 27.96 ;
     RECT  29.653 1.728 29.704 27.96 ;
     RECT  29.704 1.728 29.873 2.856 ;
     RECT  28.969 0.192 30.323 0.216 ;
     RECT  29.873 2.256 30.349 2.856 ;
     RECT  29.704 25.104 30.733 26.856 ;
     RECT  29.704 27.936 30.733 27.96 ;
     RECT  30.733 25.104 30.953 27.96 ;
     RECT  30.953 27.936 31.045 27.96 ;
     RECT  31.045 27.936 31.133 28.536 ;
     RECT  30.853 1.728 31.489 1.752 ;
     RECT  30.349 2.832 31.489 2.856 ;
     RECT  30.953 25.104 31.717 26.76 ;
     RECT  29.704 13.68 31.957 15.384 ;
     RECT  31.489 1.728 32.108 2.856 ;
     RECT  31.957 13.104 32.108 15.384 ;
     RECT  31.717 24.528 32.108 26.76 ;
     RECT  31.133 27.936 32.108 27.96 ;
     RECT  32.108 1.728 32.212 28.092 ;
     RECT  32.212 1.728 32.404 27.96 ;
     RECT  32.197 29.088 32.501 29.112 ;
     RECT  32.404 1.728 33.329 2.856 ;
     RECT  32.404 27.936 33.349 27.96 ;
     RECT  33.349 27.936 33.473 28.008 ;
     RECT  32.404 13.104 33.517 15.384 ;
     RECT  33.473 27.984 33.877 28.008 ;
     RECT  32.404 24.528 34.021 26.664 ;
     RECT  33.877 27.984 34.453 28.488 ;
     RECT  33.329 2.256 34.808 2.856 ;
     RECT  33.517 13.104 34.808 14.904 ;
     RECT  34.021 23.952 34.808 26.664 ;
     RECT  34.453 27.936 34.808 28.488 ;
     RECT  34.808 2.148 34.885 28.488 ;
     RECT  34.885 1.728 35.029 28.488 ;
     RECT  35.029 1.728 35.057 29.064 ;
     RECT  35.057 2.256 35.104 29.064 ;
     RECT  35.104 28.512 35.219 29.064 ;
     RECT  35.104 24.72 35.273 26.76 ;
     RECT  33.505 0.192 35.507 0.216 ;
     RECT  35.219 28.512 35.777 28.536 ;
     RECT  35.104 2.256 36.037 2.856 ;
     RECT  35.104 13.68 36.281 15.384 ;
     RECT  36.181 28.464 36.281 28.488 ;
     RECT  35.273 24.72 36.421 26.664 ;
     RECT  36.037 1.728 36.785 2.856 ;
     RECT  36.421 24.528 37.069 26.664 ;
     RECT  37.213 1.152 37.297 1.176 ;
     RECT  37.285 29.664 37.379 29.688 ;
     RECT  36.785 2.148 37.508 2.856 ;
     RECT  36.281 13.728 37.508 15.384 ;
     RECT  37.069 24.528 37.508 26.76 ;
     RECT  36.757 27.936 37.508 27.96 ;
     RECT  37.508 2.148 37.612 28.092 ;
     RECT  37.612 2.148 37.804 27.96 ;
     RECT  37.804 2.148 37.813 2.856 ;
     RECT  37.813 1.728 37.901 2.856 ;
     RECT  37.901 2.208 37.955 2.856 ;
     RECT  37.804 14.208 38.053 15.384 ;
     RECT  37.955 2.832 38.161 2.856 ;
     RECT  38.053 14.256 38.161 15.384 ;
     RECT  38.161 14.256 38.189 14.808 ;
     RECT  37.804 27.888 38.189 27.96 ;
     RECT  37.804 24.528 38.405 26.664 ;
     RECT  38.365 0.576 38.449 0.6 ;
     RECT  38.405 25.056 38.869 26.664 ;
     RECT  38.189 14.304 38.945 14.808 ;
     RECT  38.869 25.056 39.089 26.856 ;
     RECT  38.189 27.888 39.161 27.912 ;
     RECT  39.089 25.2 39.481 26.856 ;
     RECT  38.933 1.728 39.587 1.752 ;
     RECT  39.061 29.664 39.683 29.688 ;
     RECT  38.945 14.784 39.973 14.808 ;
     RECT  39.973 2.832 40.021 2.856 ;
     RECT  39.877 0.192 40.163 0.216 ;
     RECT  40.021 2.148 40.208 2.856 ;
     RECT  39.973 14.256 40.208 14.808 ;
     RECT  39.481 25.2 40.208 26.904 ;
     RECT  40.069 28.224 40.208 28.248 ;
     RECT  40.208 2.148 40.259 28.248 ;
     RECT  40.259 2.148 40.312 28.092 ;
     RECT  40.312 2.148 40.504 27.822 ;
     RECT  40.504 14.4 40.565 14.856 ;
     RECT  40.565 14.784 40.717 14.856 ;
     RECT  40.741 29.664 40.997 29.688 ;
     RECT  40.717 14.832 41.357 14.856 ;
     RECT  41.317 29.088 41.465 29.112 ;
     RECT  41.533 15.36 41.617 15.384 ;
     RECT  40.504 2.832 41.689 2.856 ;
     RECT  40.504 25.104 41.749 26.808 ;
     RECT  41.605 13.68 41.789 13.704 ;
     RECT  41.749 24.528 41.897 26.808 ;
     RECT  40.693 1.728 42.649 1.752 ;
     RECT  41.897 26.592 42.757 26.808 ;
     RECT  42.649 1.728 42.908 2.52 ;
     RECT  41.965 14.208 42.908 14.232 ;
     RECT  41.897 24.528 42.908 25.32 ;
     RECT  42.757 26.592 42.908 26.856 ;
     RECT  42.428 28.512 42.908 28.536 ;
     RECT  42.908 1.728 43.091 28.536 ;
     RECT  43.091 1.728 43.204 27.96 ;
     RECT  43.204 27.936 43.667 27.96 ;
     RECT  43.909 29.664 43.993 29.688 ;
     RECT  43.204 25.056 44.057 26.76 ;
     RECT  44.057 25.056 44.093 26.472 ;
     RECT  43.204 1.728 44.243 2.52 ;
     RECT  44.093 25.056 44.281 26.28 ;
     RECT  44.197 28.512 44.453 28.536 ;
     RECT  44.732 27.936 45.425 28.488 ;
     RECT  44.281 25.056 45.457 26.232 ;
     RECT  44.243 1.728 45.608 1.752 ;
     RECT  45.457 24.912 45.608 26.232 ;
     RECT  45.425 27.936 45.608 28.092 ;
     RECT  45.608 1.728 45.712 28.092 ;
     RECT  45.712 1.728 45.904 27.822 ;
     RECT  45.904 24.912 46.108 27.672 ;
     RECT  46.108 24.912 46.307 26.808 ;
     RECT  46.307 24.912 46.505 25.752 ;
     RECT  46.505 25.2 47.401 25.752 ;
     RECT  45.925 29.664 47.801 29.688 ;
     RECT  47.401 25.2 48.157 26.664 ;
     RECT  47.941 27.936 48.157 27.96 ;
     RECT  45.904 1.728 48.308 1.752 ;
     RECT  48.157 25.2 48.308 27.96 ;
     RECT  48.308 1.728 48.604 28.092 ;
     RECT  48.604 25.056 49.025 27.048 ;
     RECT  49.237 29.664 49.379 29.688 ;
     RECT  49.025 25.056 49.42 26.808 ;
     RECT  48.757 28.512 49.955 28.536 ;
     RECT  49.42 25.2 50.569 26.808 ;
     RECT  50.569 25.2 50.869 26.904 ;
     RECT  50.425 27.936 50.929 27.96 ;
     RECT  48.604 1.728 51.008 1.752 ;
     RECT  50.869 24.384 51.008 26.904 ;
     RECT  50.929 27.936 51.008 28.536 ;
     RECT  51.008 1.728 51.107 28.536 ;
     RECT  51.107 1.728 51.112 28.092 ;
     RECT  51.112 1.728 51.304 27.822 ;
     RECT  51.596 29.088 51.683 29.112 ;
     RECT  51.304 24.96 52.121 26.76 ;
     RECT  51.304 1.728 53.708 1.752 ;
     RECT  52.121 24.96 53.708 26.616 ;
     RECT  52.213 27.936 53.708 27.96 ;
     RECT  53.708 1.728 53.812 28.092 ;
     RECT  53.812 1.728 54.004 27.822 ;
     RECT  54.004 24.96 54.131 26.616 ;
     RECT  53.893 29.088 54.137 29.112 ;
     RECT  54.131 24.96 54.605 26.568 ;
     RECT  54.469 29.664 54.605 29.688 ;
     RECT  54.605 24.96 55.105 25.368 ;
     RECT  55.105 24.72 55.145 25.368 ;
     RECT  54.605 26.544 55.433 26.568 ;
     RECT  54.004 1.728 56.408 1.752 ;
     RECT  55.145 24.72 56.408 25.32 ;
     RECT  55.045 27.936 56.408 27.96 ;
     RECT  56.408 1.728 56.512 28.092 ;
     RECT  56.512 1.728 56.704 27.822 ;
     RECT  56.773 29.664 57.017 29.688 ;
     RECT  56.704 24.72 57.059 27.144 ;
     RECT  57.059 24.96 57.773 27.144 ;
     RECT  57.773 24.96 57.845 26.52 ;
     RECT  56.704 1.728 58.817 1.752 ;
     RECT  57.845 24.96 58.885 26.232 ;
     RECT  57.877 27.936 58.981 27.96 ;
     RECT  58.705 2.784 59.108 2.808 ;
     RECT  58.885 24.96 59.108 26.664 ;
     RECT  58.981 27.936 59.108 28.248 ;
     RECT  59.108 2.148 59.123 28.248 ;
     RECT  59.123 2.148 59.212 28.092 ;
     RECT  59.065 0.24 59.315 0.264 ;
     RECT  59.212 2.148 59.404 27.96 ;
     RECT  59.404 24.816 59.465 26.712 ;
     RECT  59.404 27.936 59.699 27.96 ;
     RECT  59.845 1.728 60.005 1.752 ;
     RECT  59.404 2.784 60.179 2.808 ;
     RECT  59.465 26.592 60.179 26.712 ;
     RECT  60.188 29.088 60.275 29.112 ;
     RECT  60.181 0.192 60.467 0.216 ;
     RECT  59.465 24.816 60.509 25.32 ;
     RECT  60.685 27.936 60.803 27.96 ;
     RECT  60.509 24.96 61.261 25.32 ;
     RECT  60.179 26.688 61.261 26.712 ;
     RECT  61.297 28.224 61.381 28.488 ;
     RECT  60.997 1.728 61.733 1.752 ;
     RECT  61.261 24.96 61.808 26.712 ;
     RECT  61.381 28.224 61.808 28.248 ;
     RECT  61.808 2.148 62.104 28.248 ;
     RECT  61.945 0.192 62.195 0.216 ;
     RECT  62.104 24.72 62.489 26.664 ;
     RECT  62.477 28.464 62.561 28.488 ;
     RECT  62.489 24.72 63.101 25.32 ;
     RECT  62.725 1.728 63.461 1.752 ;
     RECT  63.061 29.664 63.724 29.688 ;
     RECT  63.637 0.192 63.923 0.216 ;
     RECT  62.489 26.64 64.429 26.664 ;
     RECT  64.141 2.256 64.465 2.28 ;
     RECT  64.465 1.728 64.508 2.28 ;
     RECT  63.101 24.96 64.508 25.32 ;
     RECT  64.429 26.64 64.508 27.096 ;
     RECT  64.213 28.464 64.508 28.488 ;
     RECT  64.508 1.728 64.789 28.488 ;
     RECT  64.789 1.728 64.804 28.536 ;
     RECT  64.804 1.728 64.931 2.856 ;
     RECT  64.804 27.936 64.973 28.536 ;
     RECT  64.804 24.96 65.452 26.808 ;
     RECT  65.452 24.96 66.553 25.32 ;
     RECT  65.452 26.64 66.553 26.808 ;
     RECT  64.931 1.728 66.917 1.752 ;
     RECT  66.553 24.96 67.052 26.808 ;
     RECT  64.973 27.936 67.052 27.96 ;
     RECT  64.931 2.784 67.208 2.856 ;
     RECT  67.052 24.96 67.208 27.96 ;
     RECT  67.208 2.148 67.312 28.092 ;
     RECT  67.129 0.192 67.427 0.216 ;
     RECT  67.312 2.148 67.504 27.96 ;
     RECT  67.504 26.64 67.781 26.808 ;
     RECT  67.504 27.936 68.357 27.96 ;
     RECT  68.533 29.664 68.819 29.688 ;
     RECT  67.504 24.96 69.349 25.32 ;
     RECT  69.349 24.96 69.781 25.656 ;
     RECT  67.781 26.64 69.781 26.664 ;
     RECT  67.949 1.728 69.908 1.752 ;
     RECT  69.757 2.784 69.908 2.808 ;
     RECT  69.781 24.96 69.908 26.664 ;
     RECT  69.781 28.224 69.908 28.248 ;
     RECT  69.908 1.728 69.971 28.248 ;
     RECT  69.971 1.728 70.012 28.092 ;
     RECT  70.012 1.728 70.204 27.96 ;
     RECT  70.204 24.96 70.301 26.664 ;
     RECT  70.204 2.784 70.403 2.808 ;
     RECT  70.301 24.96 70.417 26.232 ;
     RECT  70.204 27.936 70.625 27.96 ;
     RECT  71.077 29.088 72.275 29.112 ;
     RECT  70.417 24.96 72.385 25.56 ;
     RECT  72.385 24.96 72.421 26.376 ;
     RECT  71.653 27.936 72.469 27.96 ;
     RECT  70.204 1.728 72.608 1.752 ;
     RECT  72.421 24.96 72.608 26.568 ;
     RECT  72.469 27.936 72.608 28.2 ;
     RECT  72.608 1.728 72.851 28.2 ;
     RECT  72.851 1.728 72.904 27.96 ;
     RECT  72.904 24.96 72.965 26.76 ;
     RECT  72.965 24.96 73.043 25.56 ;
     RECT  72.965 26.64 73.649 26.76 ;
     RECT  73.501 0.192 73.811 0.216 ;
     RECT  73.649 26.64 73.865 26.664 ;
     RECT  73.043 25.056 74.617 25.56 ;
     RECT  75.061 29.088 75.197 29.112 ;
     RECT  72.904 1.728 75.308 1.752 ;
     RECT  75.229 2.784 75.308 2.808 ;
     RECT  74.617 25.056 75.308 26.136 ;
     RECT  72.904 27.936 75.308 27.96 ;
     RECT  75.308 1.728 75.412 28.092 ;
     RECT  75.412 1.728 75.604 27.822 ;
     RECT  75.604 2.784 75.731 2.856 ;
     RECT  75.637 29.664 75.809 29.688 ;
     RECT  75.731 2.784 75.853 2.808 ;
     RECT  75.604 25.104 75.989 27.576 ;
     RECT  75.604 13.68 76.259 14.568 ;
     RECT  75.604 1.728 76.957 1.752 ;
     RECT  76.957 1.728 77.041 2.28 ;
     RECT  75.989 25.104 77.209 26.664 ;
     RECT  76.259 13.68 77.461 13.704 ;
     RECT  76.789 27.936 77.852 27.96 ;
     RECT  77.852 27.936 77.893 28.152 ;
     RECT  77.893 27.936 77.987 28.248 ;
     RECT  77.041 1.728 78.008 1.752 ;
     RECT  77.461 13.68 78.008 14.232 ;
     RECT  77.209 25.008 78.008 26.664 ;
     RECT  77.987 27.936 78.008 28.092 ;
     RECT  78.008 1.728 78.112 28.092 ;
     RECT  78.112 1.728 78.304 27.822 ;
     RECT  78.304 1.728 78.467 2.856 ;
     RECT  78.304 24.528 78.563 27.336 ;
     RECT  78.304 13.68 78.769 14.808 ;
     RECT  78.769 13.68 79.013 14.28 ;
     RECT  78.467 1.728 79.049 2.28 ;
     RECT  79.013 14.208 79.165 14.28 ;
     RECT  79.093 28.512 79.18 28.536 ;
     RECT  78.563 24.528 79.445 26.904 ;
     RECT  79.445 24.528 79.553 26.808 ;
     RECT  79.553 25.2 79.589 26.808 ;
     RECT  79.165 14.256 79.945 14.28 ;
     RECT  79.049 1.728 80.201 1.752 ;
     RECT  80.521 2.148 80.581 2.28 ;
     RECT  80.533 13.104 80.581 13.128 ;
     RECT  79.945 14.256 80.581 14.808 ;
     RECT  79.513 27.936 80.593 27.96 ;
     RECT  80.581 2.148 80.708 2.808 ;
     RECT  80.581 13.104 80.708 14.808 ;
     RECT  79.589 25.2 80.708 26.664 ;
     RECT  80.593 27.936 80.708 28.248 ;
     RECT  80.305 0.192 80.771 0.216 ;
     RECT  80.708 2.148 80.867 28.248 ;
     RECT  80.867 2.148 81.004 27.96 ;
     RECT  81.004 13.104 81.101 14.28 ;
     RECT  81.004 2.148 81.301 2.856 ;
     RECT  81.101 13.632 81.361 14.28 ;
     RECT  81.004 24.528 81.605 26.664 ;
     RECT  81.605 24.528 81.713 26.232 ;
     RECT  81.301 1.728 81.779 2.856 ;
     RECT  81.004 27.936 81.971 27.96 ;
     RECT  81.361 14.256 82.117 14.28 ;
     RECT  82.117 14.256 82.145 14.904 ;
     RECT  81.779 2.832 82.189 2.856 ;
     RECT  82.145 14.784 82.297 14.904 ;
     RECT  82.357 15.36 82.441 15.384 ;
     RECT  82.501 28.464 82.649 28.488 ;
     RECT  81.779 1.728 83.041 1.752 ;
     RECT  81.713 24.624 83.077 26.232 ;
     RECT  83.041 1.728 83.408 2.232 ;
     RECT  83.077 24.624 83.408 26.664 ;
     RECT  83.077 27.936 83.408 28.092 ;
     RECT  83.408 1.728 83.653 28.092 ;
     RECT  83.653 1.728 83.704 28.488 ;
     RECT  83.704 27.936 83.765 28.488 ;
     RECT  83.704 24.624 83.945 26.664 ;
     RECT  83.945 24.624 85.309 26.232 ;
     RECT  83.704 1.728 85.705 1.752 ;
     RECT  85.705 1.728 86.108 2.28 ;
     RECT  85.717 13.104 86.108 13.128 ;
     RECT  85.309 24.624 86.108 26.712 ;
     RECT  83.765 27.936 86.108 27.96 ;
     RECT  86.108 1.728 86.212 28.092 ;
     RECT  86.212 1.728 86.404 27.96 ;
     RECT  86.404 13.632 86.531 13.704 ;
     RECT  85.813 29.664 86.645 29.688 ;
     RECT  86.404 27.936 87.155 27.96 ;
     RECT  86.404 2.832 87.193 2.856 ;
     RECT  87.644 29.664 87.731 29.688 ;
     RECT  86.531 13.68 87.797 13.704 ;
     RECT  86.404 24.624 87.973 26.28 ;
     RECT  87.973 24.528 88.153 26.28 ;
     RECT  88.213 27.936 88.729 27.96 ;
     RECT  86.404 1.728 88.808 1.752 ;
     RECT  87.973 14.208 88.808 14.232 ;
     RECT  88.153 24.528 88.808 26.808 ;
     RECT  88.729 27.936 88.808 28.248 ;
     RECT  88.808 1.728 88.835 28.248 ;
     RECT  88.835 1.728 88.912 28.092 ;
     RECT  88.912 1.728 89.104 27.96 ;
     RECT  89.104 24.624 89.417 25.224 ;
     RECT  89.104 27.936 89.597 27.96 ;
     RECT  89.941 29.664 90.065 29.688 ;
     RECT  89.417 24.912 90.17 25.224 ;
     RECT  89.104 26.64 90.517 26.712 ;
     RECT  90.17 24.96 90.637 25.224 ;
     RECT  89.104 1.728 90.781 1.752 ;
     RECT  90.517 26.64 91.177 26.904 ;
     RECT  90.781 1.728 91.285 2.28 ;
     RECT  90.637 24.96 91.321 25.32 ;
     RECT  91.177 26.592 91.321 26.904 ;
     RECT  91.285 13.68 91.381 13.704 ;
     RECT  91.321 24.96 91.381 26.904 ;
     RECT  90.997 27.936 91.381 27.96 ;
     RECT  91.285 1.728 91.508 2.856 ;
     RECT  91.381 13.68 91.508 14.232 ;
     RECT  91.381 24.528 91.508 26.904 ;
     RECT  91.381 27.936 91.508 28.2 ;
     RECT  91.508 1.728 91.715 28.2 ;
     RECT  91.715 1.728 91.804 27.96 ;
     RECT  91.804 2.832 91.955 2.856 ;
     RECT  91.804 24.912 92.045 26.856 ;
     RECT  91.804 14.256 92.189 14.808 ;
     RECT  92.189 14.784 92.297 14.808 ;
     RECT  91.804 1.728 92.441 1.752 ;
     RECT  92.045 24.912 92.441 26.76 ;
     RECT  92.833 0.192 92.963 0.216 ;
     RECT  92.441 26.304 93.197 26.76 ;
     RECT  93.493 1.728 93.593 1.752 ;
     RECT  93.913 29.088 93.973 29.112 ;
     RECT  93.949 0.528 94.115 0.552 ;
     RECT  93.985 2.148 94.208 2.28 ;
     RECT  94.021 13.68 94.208 13.704 ;
     RECT  92.441 24.912 94.208 25.32 ;
     RECT  93.197 26.304 94.208 26.328 ;
     RECT  91.804 27.936 94.208 27.96 ;
     RECT  93.973 29.088 94.277 29.688 ;
     RECT  94.208 2.148 94.504 28.092 ;
     RECT  94.504 13.68 94.709 14.232 ;
     RECT  94.504 24.528 94.835 26.424 ;
     RECT  94.549 28.176 94.853 28.2 ;
     RECT  94.709 14.208 94.969 14.232 ;
     RECT  94.277 29.664 95.123 29.688 ;
     RECT  94.835 24.528 95.249 25.224 ;
     RECT  94.835 26.4 95.749 26.424 ;
     RECT  95.653 28.464 95.753 28.488 ;
     RECT  95.749 26.4 95.789 26.664 ;
     RECT  95.249 24.768 95.821 25.224 ;
     RECT  95.929 13.68 95.989 13.704 ;
     RECT  94.633 1.728 96.073 1.752 ;
     RECT  96.229 29.088 96.329 29.112 ;
     RECT  96.757 28.176 96.851 28.2 ;
     RECT  96.073 1.728 96.908 2.28 ;
     RECT  95.989 13.68 96.908 14.232 ;
     RECT  95.821 24.768 96.908 25.32 ;
     RECT  95.789 26.64 96.908 26.664 ;
     RECT  96.908 1.728 97.012 28.092 ;
     RECT  97.012 1.728 97.204 27.96 ;
     RECT  97.204 24.912 97.379 26.856 ;
     RECT  97.379 24.912 97.409 26.664 ;
     RECT  97.204 1.728 98.165 1.752 ;
     RECT  98.521 0.192 98.771 0.216 ;
     RECT  97.409 24.912 99.485 25.32 ;
     RECT  97.409 26.64 99.485 26.664 ;
     RECT  99.301 1.728 99.533 1.752 ;
     RECT  97.204 27.936 99.565 27.96 ;
     RECT  99.485 24.912 99.608 26.664 ;
     RECT  99.565 27.936 99.608 28.248 ;
     RECT  99.608 2.148 99.712 28.248 ;
     RECT  99.712 2.418 99.731 28.248 ;
     RECT  99.731 2.418 99.904 27.96 ;
     RECT  99.781 0.576 99.923 0.6 ;
     RECT  100.177 0.192 100.499 0.216 ;
     RECT  99.904 24.912 102.092 25.32 ;
     RECT  99.904 26.64 102.092 26.664 ;
     RECT  99.904 27.936 102.157 27.96 ;
     RECT  101.029 1.728 102.308 1.752 ;
     RECT  102.092 24.912 102.308 26.664 ;
     RECT  102.157 27.936 102.308 28.2 ;
     RECT  102.308 1.728 102.563 28.2 ;
     RECT  102.563 1.728 102.604 27.96 ;
     RECT  102.604 26.352 104.497 26.664 ;
     RECT  102.604 1.728 104.717 1.752 ;
     RECT  102.604 25.008 105.008 25.32 ;
     RECT  104.497 26.352 105.008 26.712 ;
     RECT  102.604 27.936 105.008 27.96 ;
     RECT  103.705 0.192 105.107 0.216 ;
     RECT  105.008 2.148 105.112 28.092 ;
     RECT  105.112 2.148 105.304 27.96 ;
     RECT  105.304 25.008 106.441 26.664 ;
     RECT  105.304 27.936 107.233 27.96 ;
     RECT  105.685 1.728 107.708 1.752 ;
     RECT  106.441 24.912 107.708 26.664 ;
     RECT  107.233 27.936 107.708 28.248 ;
     RECT  107.708 1.728 108.004 28.248 ;
     RECT  108.004 1.728 108.035 1.752 ;
     RECT  108.004 27.936 108.277 28.248 ;
     RECT  108.133 0.192 108.611 0.216 ;
     RECT  108.277 27.936 108.641 28.536 ;
     RECT  108.004 26.64 108.893 26.664 ;
     RECT  108.004 25.2 109.681 25.32 ;
     RECT  108.641 27.936 109.957 27.96 ;
     RECT  109.681 25.2 110.293 25.464 ;
     RECT  109.861 26.784 110.293 26.808 ;
     RECT  109.957 27.936 110.293 28.056 ;
     RECT  109.141 1.728 110.408 1.752 ;
     RECT  110.293 25.2 110.408 26.808 ;
     RECT  110.293 27.936 110.408 28.248 ;
     RECT  110.408 1.728 110.579 28.248 ;
     RECT  110.579 1.728 110.704 27.96 ;
     RECT  110.704 26.688 111.449 26.856 ;
     RECT  111.449 26.688 111.521 26.808 ;
     RECT  111.685 29.088 111.772 29.112 ;
     RECT  110.704 24.672 112.633 25.704 ;
     RECT  111.521 26.688 112.633 26.712 ;
     RECT  112.837 29.664 112.925 29.688 ;
     RECT  110.704 1.728 113.108 1.752 ;
     RECT  112.633 24.672 113.108 26.712 ;
     RECT  110.704 27.936 113.108 27.96 ;
     RECT  113.108 1.728 113.404 28.092 ;
     RECT  113.404 27.936 113.413 28.092 ;
     RECT  113.413 27.936 113.645 28.536 ;
     RECT  113.645 27.936 114.113 27.96 ;
     RECT  113.404 24.912 114.185 26.136 ;
     RECT  114.565 27.312 114.653 27.336 ;
     RECT  115.141 29.088 115.301 29.112 ;
     RECT  113.404 1.728 115.429 1.752 ;
     RECT  114.185 24.912 115.429 25.656 ;
     RECT  114.937 26.784 115.429 26.808 ;
     RECT  115.429 1.728 115.808 2.28 ;
     RECT  115.429 24.912 115.808 26.808 ;
     RECT  115.477 27.936 115.808 27.96 ;
     RECT  115.808 1.728 115.912 28.092 ;
     RECT  115.912 1.728 116.104 27.96 ;
     RECT  116.104 27.936 116.867 27.96 ;
     RECT  116.104 24.816 117.133 25.32 ;
     RECT  117.397 29.664 117.749 29.688 ;
     RECT  117.133 24.816 118.177 26.616 ;
     RECT  116.104 1.728 118.508 1.752 ;
     RECT  118.177 24.816 118.508 26.856 ;
     RECT  117.973 27.936 118.508 27.96 ;
     RECT  118.508 1.728 118.549 28.092 ;
     RECT  118.549 1.728 118.804 28.248 ;
     RECT  118.804 27.936 119.171 28.248 ;
     RECT  118.804 24.912 119.513 26.568 ;
     RECT  119.701 28.512 119.801 28.536 ;
     RECT  119.513 24.912 119.945 25.32 ;
     RECT  120.277 29.664 120.521 29.688 ;
     RECT  119.945 25.008 120.853 25.32 ;
     RECT  120.853 25.008 120.901 25.56 ;
     RECT  119.513 26.544 120.901 26.568 ;
     RECT  118.804 1.728 121.208 1.752 ;
     RECT  120.869 2.832 121.208 2.856 ;
     RECT  120.901 25.008 121.208 26.568 ;
     RECT  121.208 1.728 121.429 28.092 ;
     RECT  121.429 1.728 121.504 28.2 ;
     RECT  121.504 28.176 121.619 28.2 ;
     RECT  121.504 24.912 121.66 26.808 ;
     RECT  122.005 28.224 123.101 28.872 ;
     RECT  121.504 1.728 123.113 1.752 ;
     RECT  123.101 28.224 123.185 29.064 ;
     RECT  123.037 0.192 123.683 0.216 ;
     RECT  121.66 24.912 123.829 26.712 ;
     RECT  123.185 28.224 123.869 28.536 ;
     RECT  123.829 24.912 123.908 27.096 ;
     RECT  123.908 2.148 124.012 28.092 ;
     RECT  124.012 2.148 124.181 27.822 ;
     RECT  124.181 1.728 124.204 27.822 ;
     RECT  124.204 27.072 124.265 27.096 ;
     RECT  124.261 29.664 124.661 29.688 ;
     RECT  124.204 25.2 125.737 25.272 ;
     RECT  124.204 1.728 126.608 1.752 ;
     RECT  125.737 25.008 126.608 26.232 ;
     RECT  124.837 29.088 126.649 29.112 ;
     RECT  126.608 1.728 126.904 28.092 ;
     RECT  126.904 25.008 127.073 25.272 ;
     RECT  126.904 1.728 127.217 1.752 ;
     RECT  127.141 28.512 127.289 28.536 ;
     RECT  126.904 26.784 127.397 26.808 ;
     RECT  127.717 0.576 127.801 0.6 ;
     RECT  127.717 29.664 127.804 29.688 ;
     RECT  128.041 0.192 128.339 0.216 ;
     RECT  128.252 27.936 128.339 27.96 ;
     RECT  128.185 26.736 128.833 26.76 ;
     RECT  127.073 25.056 128.917 25.272 ;
     RECT  128.833 26.64 128.917 26.76 ;
     RECT  128.869 1.728 129.308 1.752 ;
     RECT  128.905 2.832 129.308 2.856 ;
     RECT  128.917 25.056 129.308 26.76 ;
     RECT  129.308 1.728 129.412 28.092 ;
     RECT  129.229 0.528 129.491 0.552 ;
     RECT  129.412 1.728 129.604 27.822 ;
     RECT  128.869 29.664 129.952 29.688 ;
     RECT  129.604 25.248 129.953 27.432 ;
     RECT  129.952 29.664 129.953 29.736 ;
     RECT  129.604 1.728 130.105 1.752 ;
     RECT  129.953 29.712 130.349 29.736 ;
     RECT  130.549 28.512 131.125 28.536 ;
     RECT  130.489 0.192 131.173 0.216 ;
     RECT  131.173 0.192 131.257 0.6 ;
     RECT  131.125 28.464 131.285 28.536 ;
     RECT  129.953 25.248 131.317 26.712 ;
     RECT  131.257 0.192 131.795 0.216 ;
     RECT  131.317 25.056 131.857 26.712 ;
     RECT  131.857 25.056 131.893 27.048 ;
     RECT  131.701 29.088 131.933 29.112 ;
     RECT  131.893 25.056 132.008 28.092 ;
     RECT  132.008 2.148 132.277 28.092 ;
     RECT  132.277 2.148 132.304 28.536 ;
     RECT  132.304 25.056 132.563 26.76 ;
     RECT  132.304 27.936 132.761 28.536 ;
     RECT  132.761 27.936 132.941 27.96 ;
     RECT  132.317 1.728 133.121 1.752 ;
     RECT  133.297 0.192 133.571 0.216 ;
     RECT  132.563 25.248 133.621 26.76 ;
     RECT  134.101 1.728 134.309 1.752 ;
     RECT  133.429 29.664 134.705 29.688 ;
     RECT  134.549 2.832 134.708 2.856 ;
     RECT  133.621 25.056 134.708 26.76 ;
     RECT  134.005 27.936 134.708 27.96 ;
     RECT  134.665 0.576 134.749 0.6 ;
     RECT  134.708 2.148 134.812 28.092 ;
     RECT  134.812 2.418 135.004 27.96 ;
     RECT  135.004 25.2 135.137 27.96 ;
     RECT  135.061 0.192 135.299 0.216 ;
     RECT  135.137 26.64 135.497 27.96 ;
     RECT  135.497 26.736 135.533 27.96 ;
     RECT  135.533 26.736 135.677 26.808 ;
     RECT  135.677 26.736 135.749 26.76 ;
     RECT  135.829 1.728 136.577 1.752 ;
     RECT  135.733 29.664 136.924 29.688 ;
     RECT  135.137 25.2 137.221 25.272 ;
     RECT  137.221 25.008 137.408 25.272 ;
     RECT  136.861 26.304 137.408 26.328 ;
     RECT  137.408 2.148 137.413 28.092 ;
     RECT  136.753 0.192 137.603 0.216 ;
     RECT  137.413 2.148 137.704 28.248 ;
     RECT  137.704 27.936 138.161 28.248 ;
     RECT  138.161 28.224 138.233 28.248 ;
     RECT  137.704 25.008 138.305 26.808 ;
     RECT  138.565 29.664 138.701 29.688 ;
     RECT  139.141 28.512 139.277 28.536 ;
     RECT  139.189 14.832 139.381 14.856 ;
     RECT  139.717 29.664 139.817 29.688 ;
     RECT  138.305 25.008 140.029 26.712 ;
     RECT  138.133 1.728 140.108 1.752 ;
     RECT  139.165 2.832 140.108 2.856 ;
     RECT  139.381 14.832 140.108 15.384 ;
     RECT  140.029 25.008 140.108 26.808 ;
     RECT  140.108 1.728 140.293 28.092 ;
     RECT  140.293 1.728 140.404 28.2 ;
     RECT  140.404 24.528 140.573 25.32 ;
     RECT  140.404 27.936 140.717 28.2 ;
     RECT  140.573 24.528 140.761 25.272 ;
     RECT  140.404 13.68 140.963 14.232 ;
     RECT  140.404 2.832 140.977 2.856 ;
     RECT  140.963 14.208 141.041 14.232 ;
     RECT  141.445 29.664 141.581 29.688 ;
     RECT  140.404 26.592 141.685 26.808 ;
     RECT  140.761 25.056 141.761 25.272 ;
     RECT  141.685 26.592 141.833 26.904 ;
     RECT  141.833 26.592 142.477 26.76 ;
     RECT  142.477 26.544 142.597 26.76 ;
     RECT  140.404 1.728 142.808 1.752 ;
     RECT  141.761 25.248 142.808 25.272 ;
     RECT  142.597 26.256 142.808 26.76 ;
     RECT  140.717 27.936 142.808 27.96 ;
     RECT  142.808 1.728 143.104 28.092 ;
     RECT  143.104 27.936 143.125 28.092 ;
     RECT  143.125 27.936 143.273 28.2 ;
     RECT  143.104 26.256 143.453 26.808 ;
     RECT  143.453 26.256 143.597 26.568 ;
     RECT  143.597 26.256 143.705 26.52 ;
     RECT  144.277 29.664 144.389 29.688 ;
     RECT  143.705 26.496 144.853 26.52 ;
     RECT  143.104 24.768 145.357 25.272 ;
     RECT  145.388 29.664 145.475 29.688 ;
     RECT  143.104 1.728 145.508 1.752 ;
     RECT  145.357 24.624 145.508 25.272 ;
     RECT  144.853 26.496 145.508 26.664 ;
     RECT  143.273 27.936 145.508 27.96 ;
     RECT  145.508 1.728 145.612 28.092 ;
     RECT  145.612 1.728 145.804 27.96 ;
     RECT  145.804 26.592 146.225 26.808 ;
     RECT  145.804 24.624 146.513 25.272 ;
     RECT  146.225 26.592 147.089 26.616 ;
     RECT  146.581 29.664 147.917 29.688 ;
     RECT  145.804 1.728 148.208 1.752 ;
     RECT  146.513 25.248 148.208 25.272 ;
     RECT  145.804 27.936 148.208 27.96 ;
     RECT  148.208 1.728 148.309 28.092 ;
     RECT  148.309 1.728 148.504 28.248 ;
     RECT  148.504 28.224 148.565 28.248 ;
     RECT  148.885 29.664 149.213 29.688 ;
     RECT  148.504 1.728 150.908 1.752 ;
     RECT  148.504 25.248 150.908 26.04 ;
     RECT  150.908 1.728 151.012 28.092 ;
     RECT  151.012 1.728 151.204 27.822 ;
     RECT  151.204 26.256 151.661 26.28 ;
     RECT  149.461 29.088 152.489 29.112 ;
     RECT  152.869 29.664 153.209 29.688 ;
     RECT  151.204 25.248 153.421 25.272 ;
     RECT  153.421 25.248 153.457 25.848 ;
     RECT  153.445 27.312 153.529 27.336 ;
     RECT  151.204 1.728 153.608 1.752 ;
     RECT  153.457 25.248 153.608 26.04 ;
     RECT  153.529 27.312 153.608 27.48 ;
     RECT  153.608 1.728 153.712 28.092 ;
     RECT  153.712 1.728 153.904 27.96 ;
     RECT  153.904 27.936 154.145 27.96 ;
     RECT  154.597 29.04 154.721 29.064 ;
     RECT  155.173 29.664 155.369 29.688 ;
     RECT  153.904 25.248 155.473 26.04 ;
     RECT  155.617 27.36 156.229 27.384 ;
     RECT  153.904 1.728 156.308 1.752 ;
     RECT  155.473 25.248 156.308 26.232 ;
     RECT  156.229 27.36 156.308 28.248 ;
     RECT  156.308 1.728 156.371 28.248 ;
     RECT  156.371 1.728 156.412 28.092 ;
     RECT  156.412 1.728 156.604 27.96 ;
     RECT  156.604 25.248 157.493 26.568 ;
     RECT  156.604 27.936 157.853 27.96 ;
     RECT  158.437 0.192 158.579 0.216 ;
     RECT  157.964 29.664 158.717 29.688 ;
     RECT  156.604 1.728 159.008 1.752 ;
     RECT  157.493 25.248 159.008 26.232 ;
     RECT  159.008 1.728 159.157 28.092 ;
     RECT  159.157 1.728 159.185 28.2 ;
     RECT  159.185 2.418 159.304 28.2 ;
     RECT  159.304 27.936 159.509 28.2 ;
     RECT  159.541 0.192 159.635 0.216 ;
     RECT  159.509 27.936 160.697 27.96 ;
     RECT  160.885 28.512 161.093 28.536 ;
     RECT  159.304 25.248 161.485 25.272 ;
     RECT  160.945 26.736 161.485 26.76 ;
     RECT  161.42 29.664 161.507 29.688 ;
     RECT  160.181 1.728 161.525 1.752 ;
     RECT  161.485 25.248 161.665 26.76 ;
     RECT  161.665 25.248 161.708 27.096 ;
     RECT  161.845 0.192 161.987 0.216 ;
     RECT  161.708 2.148 162.004 28.2 ;
     RECT  162.004 28.176 162.461 28.2 ;
     RECT  162.004 25.056 162.713 26.568 ;
     RECT  162.493 1.728 163.181 1.752 ;
     RECT  162.493 29.664 163.235 29.688 ;
     RECT  162.713 25.056 163.813 25.08 ;
     RECT  162.713 26.112 164.033 26.568 ;
     RECT  164.033 26.112 164.257 26.808 ;
     RECT  163.717 27.888 164.257 27.912 ;
     RECT  163.429 0.192 164.291 0.216 ;
     RECT  164.293 29.664 164.38 29.688 ;
     RECT  163.813 24.816 164.408 25.08 ;
     RECT  164.257 26.112 164.408 27.912 ;
     RECT  164.408 2.148 164.512 28.092 ;
     RECT  164.512 2.148 164.704 27.96 ;
     RECT  164.869 29.088 164.956 29.112 ;
     RECT  164.704 25.44 164.981 26.568 ;
     RECT  164.981 26.544 165.305 26.568 ;
     RECT  164.821 1.728 165.443 1.752 ;
     RECT  165.841 0.192 166.019 0.216 ;
     RECT  164.704 27.888 166.021 27.96 ;
     RECT  164.981 25.44 166.129 25.464 ;
     RECT  166.021 27.888 166.309 28.296 ;
     RECT  166.309 27.696 166.381 28.296 ;
     RECT  166.129 25.44 166.417 25.704 ;
     RECT  166.381 27.648 166.597 28.296 ;
     RECT  166.417 25.44 167.101 26.232 ;
     RECT  166.549 1.728 167.108 1.752 ;
     RECT  167.101 25.44 167.108 26.328 ;
     RECT  166.597 27.36 167.108 28.296 ;
     RECT  167.108 1.728 167.404 28.296 ;
     RECT  167.749 29.664 167.969 29.688 ;
     RECT  167.404 26.208 168.041 28.296 ;
     RECT  168.041 26.208 168.221 28.248 ;
     RECT  167.404 1.728 168.437 1.752 ;
     RECT  168.221 27.072 168.545 28.248 ;
     RECT  168.545 27.168 168.653 28.248 ;
     RECT  168.653 27.264 169.301 28.248 ;
     RECT  169.301 27.264 169.808 28.092 ;
     RECT  169.808 2.148 169.912 28.092 ;
     RECT  169.912 2.418 170.104 27.822 ;
    LAYER M5 ;
     RECT  4.752 0.144 168.36 0.227 ;
     RECT  40.704 0.227 59.88 0.275 ;
     RECT  9.36 0.227 28.536 0.563 ;
     RECT  93.504 0.227 98.136 0.563 ;
     RECT  128.88 0.227 130.056 0.563 ;
     RECT  4.752 0.227 4.776 0.611 ;
     RECT  26.784 0.563 28.536 0.611 ;
     RECT  36.048 0.227 39.576 0.611 ;
     RECT  99.312 0.227 99.912 0.611 ;
     RECT  124.224 0.227 127.752 0.611 ;
     RECT  131.184 0.227 131.208 0.611 ;
     RECT  134.112 0.227 134.712 0.611 ;
     RECT  6.48 0.227 8.232 1.763 ;
     RECT  9.36 0.563 25.656 1.763 ;
     RECT  28.512 0.611 28.536 1.763 ;
     RECT  30.864 0.227 33.192 1.763 ;
     RECT  38.976 0.611 39.576 1.763 ;
     RECT  40.704 0.275 58.728 1.763 ;
     RECT  59.856 0.275 59.88 1.763 ;
     RECT  61.008 0.227 61.608 1.763 ;
     RECT  62.736 0.227 63.336 1.763 ;
     RECT  64.512 0.227 66.84 1.763 ;
     RECT  67.968 0.227 73.224 1.763 ;
     RECT  74.352 0.227 80.184 1.763 ;
     RECT  81.312 0.227 92.376 1.763 ;
     RECT  93.504 0.563 93.528 1.763 ;
     RECT  94.656 0.563 98.136 1.763 ;
     RECT  99.312 0.611 99.336 1.763 ;
     RECT  101.04 0.227 103.368 1.763 ;
     RECT  104.496 0.227 104.52 1.763 ;
     RECT  105.696 0.227 108.024 1.763 ;
     RECT  109.152 0.227 123.096 1.763 ;
     RECT  124.224 0.611 127.176 1.763 ;
     RECT  128.88 0.563 128.904 1.763 ;
     RECT  130.032 0.563 130.056 1.763 ;
     RECT  132.336 0.227 132.984 1.763 ;
     RECT  134.112 0.611 134.136 1.763 ;
     RECT  135.84 0.227 136.44 1.763 ;
     RECT  138.144 0.227 159.048 1.763 ;
     RECT  160.224 0.227 161.4 1.763 ;
     RECT  162.528 0.227 163.128 1.763 ;
     RECT  164.832 0.227 165.432 1.763 ;
     RECT  166.56 0.227 168.36 1.763 ;
     RECT  26.784 0.611 27.384 2.137 ;
     RECT  29.664 0.227 29.688 2.137 ;
     RECT  34.896 0.227 34.92 2.137 ;
     RECT  64.512 1.763 64.92 2.137 ;
     RECT  81.312 1.763 81.768 2.137 ;
     RECT  159 1.763 159.048 2.137 ;
     RECT  2.4 2.137 2.52 2.151 ;
     RECT  5.1 2.137 5.22 2.151 ;
     RECT  29.4 2.137 29.688 2.151 ;
     RECT  34.8 2.137 34.92 2.151 ;
     RECT  36.048 0.611 37.848 2.151 ;
     RECT  99.6 2.137 99.72 2.151 ;
     RECT  134.7 2.137 134.82 2.151 ;
     RECT  159 2.137 159.12 2.151 ;
     RECT  169.8 2.137 169.92 2.151 ;
     RECT  34.8 2.151 37.848 2.197 ;
     RECT  21.3 1.763 22.152 2.243 ;
     RECT  25.632 1.763 25.656 2.243 ;
     RECT  26.7 2.137 27.384 2.245 ;
     RECT  29.4 2.151 29.712 2.245 ;
     RECT  31.536 1.763 33.192 2.245 ;
     RECT  34.8 2.197 37.944 2.245 ;
     RECT  13.2 1.763 14.04 2.291 ;
     RECT  59.1 2.137 59.412 2.773 ;
     RECT  67.2 2.137 67.512 2.773 ;
     RECT  69.9 1.763 70.212 2.773 ;
     RECT  75.3 1.763 75.612 2.773 ;
     RECT  26.7 2.245 27.528 2.821 ;
     RECT  29.4 2.245 30.312 2.821 ;
     RECT  31.536 2.245 37.944 2.821 ;
     RECT  40.032 2.137 40.512 2.821 ;
     RECT  80.544 2.137 81.768 2.821 ;
     RECT  85.728 1.763 86.412 2.821 ;
     RECT  91.344 1.763 91.812 2.821 ;
     RECT  121.2 1.763 121.512 2.821 ;
     RECT  129.3 2.137 129.612 2.821 ;
     RECT  134.7 2.151 135.012 2.821 ;
     RECT  140.1 1.763 140.412 2.821 ;
     RECT  7.8 1.763 8.112 3.445 ;
     RECT  80.544 2.821 82.152 13.139 ;
     RECT  85.728 2.821 87.144 13.139 ;
     RECT  39.984 2.821 41.64 13.715 ;
     RECT  76.992 1.763 77.016 13.715 ;
     RECT  80.592 13.139 82.152 13.715 ;
     RECT  86.1 13.139 87.144 13.715 ;
     RECT  91.296 2.821 91.944 13.715 ;
     RECT  94.032 2.137 94.512 13.715 ;
     RECT  139.2 2.821 140.952 13.715 ;
     RECT  42.9 1.763 43.212 14.197 ;
     RECT  75.3 2.773 75.816 14.197 ;
     RECT  78 1.763 79.032 14.197 ;
     RECT  88.8 1.763 89.112 14.197 ;
     RECT  94.2 13.715 94.512 14.197 ;
     RECT  96.096 1.763 97.212 14.197 ;
     RECT  26.7 2.821 38.136 14.291 ;
     RECT  39.984 13.715 40.824 14.291 ;
     RECT  40.032 14.291 40.824 14.435 ;
     RECT  28.08 14.291 38.136 14.677 ;
     RECT  28.08 14.677 38.328 14.773 ;
     RECT  77.472 14.197 79.128 14.773 ;
     RECT  80.7 13.715 82.152 14.773 ;
     RECT  91.344 13.715 91.944 14.773 ;
     RECT  28.08 14.773 39.048 14.867 ;
     RECT  139.2 13.715 140.712 14.867 ;
     RECT  40.08 14.435 40.824 15.349 ;
     RECT  42 14.197 43.212 15.349 ;
     RECT  77.472 14.773 82.248 15.349 ;
     RECT  83.232 1.763 83.712 15.349 ;
     RECT  5.1 2.151 5.412 18.181 ;
     RECT  51 1.763 51.312 24.373 ;
     RECT  40.08 15.349 43.212 24.563 ;
     RECT  77.472 15.349 83.712 24.563 ;
     RECT  87.984 14.197 89.112 24.563 ;
     RECT  94.2 14.197 94.92 24.563 ;
     RECT  139.392 14.867 140.712 24.563 ;
     RECT  56.4 1.763 56.712 24.709 ;
     RECT  118.5 1.763 118.812 24.805 ;
     RECT  164.4 2.137 164.712 24.805 ;
     RECT  91.344 14.773 92.28 24.901 ;
     RECT  99.6 2.151 99.912 24.901 ;
     RECT  72.6 1.763 72.912 24.949 ;
     RECT  117.744 24.805 118.812 25.043 ;
     RECT  21.3 2.243 21.612 25.045 ;
     RECT  24 1.763 24.312 25.045 ;
     RECT  45.6 1.763 45.912 25.045 ;
     RECT  48.3 1.763 48.612 25.045 ;
     RECT  53.7 1.763 54.012 25.045 ;
     RECT  132 2.137 132.312 25.045 ;
     RECT  72.6 24.949 73.032 25.093 ;
     RECT  0.24 9.733 0.264 25.235 ;
     RECT  24 25.045 25.08 25.331 ;
     RECT  50.88 24.373 51.312 25.331 ;
     RECT  52.896 25.045 54.012 25.331 ;
     RECT  96 14.197 97.212 25.331 ;
     RECT  21.3 25.045 21.816 25.333 ;
     RECT  64.5 2.137 64.92 25.333 ;
     RECT  45.6 25.045 46.008 25.429 ;
     RECT  72.432 25.093 73.032 25.475 ;
     RECT  86.1 13.715 86.52 25.475 ;
     RECT  53.568 25.331 54.012 25.525 ;
     RECT  120.912 2.821 121.512 25.525 ;
     RECT  77.472 24.563 78.936 25.571 ;
     RECT  72.432 25.475 72.912 25.619 ;
     RECT  45.6 25.429 46.296 25.621 ;
     RECT  69.9 2.773 70.392 25.621 ;
     RECT  56.4 24.709 57.048 25.669 ;
     RECT  118.5 25.043 118.812 25.669 ;
     RECT  7.8 3.445 8.952 25.715 ;
     RECT  28.56 14.867 39.048 25.715 ;
     RECT  77.472 25.571 78.744 25.715 ;
     RECT  79.968 24.563 83.712 25.715 ;
     RECT  91.344 24.901 92.328 25.715 ;
     RECT  94.2 24.563 94.824 25.715 ;
     RECT  99.504 24.901 99.912 25.715 ;
     RECT  59.1 2.773 60.168 25.717 ;
     RECT  105 2.137 105.312 25.717 ;
     RECT  40.08 24.563 41.592 25.763 ;
     RECT  91.344 25.715 92.28 25.811 ;
     RECT  131.376 25.045 132.552 25.859 ;
     RECT  96.9 25.331 97.212 25.957 ;
     RECT  110.4 1.763 110.712 26.005 ;
     RECT  163.824 24.805 164.712 26.147 ;
     RECT  26.7 14.291 27.012 26.149 ;
     RECT  42.9 24.563 43.212 26.149 ;
     RECT  44.208 1.763 44.232 26.149 ;
     RECT  102.3 1.763 102.612 26.149 ;
     RECT  40.2 25.763 41.592 26.243 ;
     RECT  48.3 25.045 49.368 26.243 ;
     RECT  69.36 25.621 70.392 26.243 ;
     RECT  77.904 25.715 78.744 26.243 ;
     RECT  80.7 25.715 83.712 26.243 ;
     RECT  115.44 1.763 116.112 26.243 ;
     RECT  128.928 2.821 129.612 26.243 ;
     RECT  134.592 2.821 135.012 26.243 ;
     RECT  142.8 1.763 143.112 26.245 ;
     RECT  21.3 25.333 22.2 26.291 ;
     RECT  28.56 25.715 33.48 26.291 ;
     RECT  34.656 25.715 39.048 26.291 ;
     RECT  42.9 26.149 44.232 26.291 ;
     RECT  139.392 24.563 140.412 26.291 ;
     RECT  137.4 2.137 137.712 26.293 ;
     RECT  28.56 26.291 33 26.339 ;
     RECT  34.656 26.291 37.812 26.339 ;
     RECT  83.232 26.243 83.712 26.339 ;
     RECT  28.56 26.339 29.712 26.387 ;
     RECT  31.92 26.339 32.412 26.387 ;
     RECT  51 25.331 51.312 26.389 ;
     RECT  53.568 25.525 54.12 26.483 ;
     RECT  53.7 26.483 54.12 26.627 ;
     RECT  58.992 25.717 60.168 26.627 ;
     RECT  102.144 26.149 102.612 26.627 ;
     RECT  64.5 25.333 65.4 26.675 ;
     RECT  91.344 25.811 91.944 26.677 ;
     RECT  64.5 26.675 64.968 26.723 ;
     RECT  131.376 25.859 132.312 26.723 ;
     RECT  30.816 26.339 30.84 26.771 ;
     RECT  50.832 26.389 51.312 26.771 ;
     RECT  66.96 2.773 67.512 26.771 ;
     RECT  15.9 1.763 16.212 26.773 ;
     RECT  40.2 26.243 40.512 26.773 ;
     RECT  120.864 25.525 121.512 26.773 ;
     RECT  90.576 26.677 91.944 26.819 ;
     RECT  137.4 26.293 137.832 26.819 ;
     RECT  164.064 26.147 164.712 26.819 ;
     RECT  26.7 26.149 27.144 26.867 ;
     RECT  96.9 25.957 97.368 26.867 ;
     RECT  90.576 26.819 91.812 26.869 ;
     RECT  24 25.331 24.312 26.965 ;
     RECT  15.024 26.773 16.212 27.061 ;
     RECT  129.3 26.243 129.612 27.109 ;
     RECT  77.904 26.243 78.504 27.301 ;
     RECT  153.6 1.763 153.912 27.301 ;
     RECT  13.2 2.291 13.512 27.349 ;
     RECT  15.024 27.061 16.392 27.349 ;
     RECT  156.3 1.763 156.612 27.349 ;
     RECT  167.1 1.763 167.412 27.349 ;
     RECT  129.3 27.109 129.864 27.443 ;
     RECT  7.8 25.715 8.112 27.829 ;
     RECT  37.5 26.339 37.812 27.877 ;
     RECT  164.4 26.819 164.712 27.877 ;
     RECT  21.3 26.291 21.72 27.923 ;
     RECT  10.5 1.763 10.812 27.925 ;
     RECT  13.2 27.349 16.392 27.925 ;
     RECT  18.6 1.763 18.912 27.925 ;
     RECT  21.3 27.923 21.612 27.925 ;
     RECT  24 26.965 24.408 27.925 ;
     RECT  26.7 26.867 27.012 27.925 ;
     RECT  29.28 26.387 29.712 27.925 ;
     RECT  32.1 26.387 32.412 27.925 ;
     RECT  34.656 26.339 35.208 27.925 ;
     RECT  37.5 27.877 38.52 27.925 ;
     RECT  42.9 26.291 43.944 27.925 ;
     RECT  45.6 25.621 46.536 27.925 ;
     RECT  48.3 26.243 48.612 27.925 ;
     RECT  51 26.771 51.312 27.925 ;
     RECT  53.7 26.627 54.012 27.925 ;
     RECT  56.4 25.669 57.384 27.925 ;
     RECT  58.992 26.627 59.412 27.925 ;
     RECT  64.5 26.723 64.812 27.925 ;
     RECT  67.104 26.771 67.512 27.925 ;
     RECT  69.36 26.243 70.212 27.925 ;
     RECT  72.48 25.619 72.912 27.925 ;
     RECT  75.3 14.197 76.248 27.925 ;
     RECT  77.904 27.301 78.552 27.925 ;
     RECT  80.7 26.243 81.012 27.925 ;
     RECT  83.4 26.339 83.712 27.925 ;
     RECT  86.1 25.475 86.412 27.925 ;
     RECT  88.8 24.563 89.112 27.925 ;
     RECT  90.528 26.869 91.812 27.925 ;
     RECT  94.2 25.715 94.512 27.925 ;
     RECT  96.9 26.867 97.212 27.925 ;
     RECT  99.6 25.715 99.912 27.925 ;
     RECT  102.3 26.627 102.612 27.925 ;
     RECT  105 25.717 105.432 27.925 ;
     RECT  107.7 1.763 108.012 27.925 ;
     RECT  110.304 26.005 110.712 27.925 ;
     RECT  113.1 1.763 113.412 27.925 ;
     RECT  114.576 27.301 114.6 27.925 ;
     RECT  115.8 26.243 116.112 27.925 ;
     RECT  118.5 25.669 118.92 27.925 ;
     RECT  131.904 26.723 132.312 27.925 ;
     RECT  134.7 26.243 135.012 27.925 ;
     RECT  137.4 26.819 137.712 27.925 ;
     RECT  140.1 26.291 140.412 27.925 ;
     RECT  142.608 26.245 143.112 27.925 ;
     RECT  145.5 1.763 145.812 27.925 ;
     RECT  153.456 27.301 153.912 27.925 ;
     RECT  155.76 27.349 156.612 27.925 ;
     RECT  159 2.151 159.312 27.925 ;
     RECT  163.728 27.877 164.712 27.925 ;
     RECT  31.632 27.925 32.808 27.973 ;
     RECT  166.608 27.349 167.412 27.973 ;
     RECT  7.008 27.829 8.112 28.021 ;
     RECT  9.312 27.925 9.336 28.021 ;
     RECT  2.4 2.151 2.712 28.089 ;
     RECT  40.08 26.773 40.512 28.089 ;
     RECT  50.496 27.925 54.012 28.089 ;
     RECT  123.9 2.137 124.212 28.089 ;
     RECT  129.3 27.443 129.612 28.089 ;
     RECT  148.2 1.763 148.512 28.089 ;
     RECT  150.9 1.763 151.212 28.089 ;
     RECT  166.608 27.973 168.36 28.089 ;
     RECT  169.8 2.151 170.112 28.089 ;
     RECT  2.4 28.089 2.52 28.103 ;
     RECT  4.752 18.181 5.412 28.103 ;
     RECT  7.008 28.021 9.336 28.103 ;
     RECT  10.5 27.925 11.064 28.103 ;
     RECT  13.2 27.925 16.776 28.103 ;
     RECT  25.92 27.925 28.2 28.103 ;
     RECT  31.632 27.973 33.384 28.103 ;
     RECT  36.768 27.925 38.52 28.103 ;
     RECT  40.08 28.089 40.32 28.103 ;
     RECT  42.9 27.925 46.536 28.103 ;
     RECT  50.496 28.089 51.12 28.103 ;
     RECT  52.224 28.089 53.82 28.103 ;
     RECT  55.056 27.925 59.688 28.103 ;
     RECT  71.664 27.925 78.552 28.103 ;
     RECT  83.088 27.925 87.144 28.103 ;
     RECT  90.528 27.925 94.512 28.103 ;
     RECT  112.272 27.925 114.6 28.103 ;
     RECT  123.9 28.089 124.02 28.103 ;
     RECT  126.6 1.763 126.912 28.103 ;
     RECT  129.3 28.089 129.42 28.103 ;
     RECT  131.904 27.925 132.888 28.103 ;
     RECT  134.016 27.925 135.192 28.103 ;
     RECT  137.4 27.925 138.024 28.103 ;
     RECT  140.1 27.925 140.904 28.103 ;
     RECT  144.864 27.925 146.04 28.103 ;
     RECT  148.2 28.089 148.344 28.103 ;
     RECT  150.9 28.089 151.02 28.103 ;
     RECT  159 27.925 160.344 28.103 ;
     RECT  161.7 2.137 162.012 28.103 ;
     RECT  163.728 27.925 165.48 28.103 ;
     RECT  166.608 28.089 167.22 28.103 ;
     RECT  169.8 28.089 169.92 28.103 ;
     RECT  96.9 27.925 111.144 28.165 ;
     RECT  120.864 26.773 121.608 28.213 ;
     RECT  40.08 28.103 40.248 28.259 ;
     RECT  165.456 28.103 165.48 28.261 ;
     RECT  166.608 28.103 167.208 28.261 ;
     RECT  18.48 27.925 18.912 28.453 ;
     RECT  27.6 28.103 28.2 28.453 ;
     RECT  29.28 27.925 30.504 28.453 ;
     RECT  32.784 28.103 33.384 28.453 ;
     RECT  34.464 27.925 35.208 28.453 ;
     RECT  36.768 28.103 36.792 28.453 ;
     RECT  60.768 27.925 60.792 28.453 ;
     RECT  61.8 2.137 62.112 28.453 ;
     RECT  64.5 27.925 68.232 28.453 ;
     RECT  79.68 27.925 81.96 28.453 ;
     RECT  83.088 28.103 85.416 28.453 ;
     RECT  7.008 28.103 7.032 28.501 ;
     RECT  11.04 28.103 11.064 28.501 ;
     RECT  18.48 28.453 19.08 28.501 ;
     RECT  23.04 27.925 24.792 28.501 ;
     RECT  25.92 28.103 26.52 28.501 ;
     RECT  27.6 28.453 30.504 28.501 ;
     RECT  31.632 28.103 31.656 28.501 ;
     RECT  32.784 28.453 35.208 28.501 ;
     RECT  36.192 28.453 36.792 28.501 ;
     RECT  41.904 26.773 41.928 28.501 ;
     RECT  42.9 28.103 45.384 28.501 ;
     RECT  48.192 27.925 48.612 28.501 ;
     RECT  50.496 28.103 51.096 28.501 ;
     RECT  76.224 28.103 78.552 28.501 ;
     RECT  79.68 28.453 85.416 28.501 ;
     RECT  117.984 27.925 119.16 28.501 ;
     RECT  131.136 28.453 131.16 28.501 ;
     RECT  159.168 28.103 160.344 28.501 ;
     RECT  20.736 27.925 21.612 29.029 ;
     RECT  120.864 28.213 122.568 29.029 ;
     RECT  123.696 28.501 123.72 29.029 ;
     RECT  153.456 27.925 154.056 29.029 ;
     RECT  8.736 28.103 9.336 29.077 ;
     RECT  27.6 28.501 31.656 29.077 ;
     RECT  32.784 28.501 36.792 29.077 ;
     RECT  41.904 28.501 45.384 29.077 ;
     RECT  49.92 28.501 51.096 29.077 ;
     RECT  52.224 28.103 53.4 29.077 ;
     RECT  57.36 28.103 59.688 29.077 ;
     RECT  60.768 28.453 62.52 29.077 ;
     RECT  69.36 27.925 70.536 29.077 ;
     RECT  71.664 28.103 74.52 29.077 ;
     RECT  95.664 28.453 95.688 29.077 ;
     RECT  96.816 28.165 111.144 29.077 ;
     RECT  112.272 28.103 112.296 29.077 ;
     RECT  113.424 28.103 114.6 29.077 ;
     RECT  115.68 27.925 116.856 29.077 ;
     RECT  127.152 28.501 127.176 29.077 ;
     RECT  130.56 28.501 131.16 29.077 ;
     RECT  132.288 28.103 132.888 29.077 ;
     RECT  165.456 28.261 167.208 29.077 ;
     RECT  8.736 29.077 9.912 29.173 ;
     RECT  11.04 28.501 11.64 29.173 ;
     RECT  4.752 28.103 4.776 29.653 ;
     RECT  5.904 28.501 7.032 29.653 ;
     RECT  8.736 29.173 11.64 29.653 ;
     RECT  12.768 28.501 12.792 29.653 ;
     RECT  13.872 28.103 15.624 29.653 ;
     RECT  16.752 28.103 16.776 29.653 ;
     RECT  18.48 28.501 19.656 29.653 ;
     RECT  20.736 29.029 21.912 29.653 ;
     RECT  23.04 28.501 26.52 29.653 ;
     RECT  27.6 29.077 36.792 29.653 ;
     RECT  37.92 28.103 38.52 29.653 ;
     RECT  40.224 28.259 40.248 29.653 ;
     RECT  41.328 29.077 45.384 29.653 ;
     RECT  46.512 28.103 46.536 29.653 ;
     RECT  48.192 28.501 48.792 29.653 ;
     RECT  49.92 29.077 53.928 29.653 ;
     RECT  55.056 28.103 56.232 29.653 ;
     RECT  57.36 29.077 62.52 29.653 ;
     RECT  64.224 28.453 68.232 29.653 ;
     RECT  69.36 29.077 75.096 29.653 ;
     RECT  76.224 28.501 85.416 29.653 ;
     RECT  87.12 28.103 87.144 29.653 ;
     RECT  88.224 27.925 89.4 29.653 ;
     RECT  90.528 28.103 93.432 29.653 ;
     RECT  94.56 28.165 94.584 29.653 ;
     RECT  95.664 29.077 112.296 29.653 ;
     RECT  113.424 29.077 116.856 29.653 ;
     RECT  117.984 28.501 119.736 29.653 ;
     RECT  120.864 29.029 123.72 29.653 ;
     RECT  124.848 29.077 127.176 29.653 ;
     RECT  128.304 27.925 128.328 29.653 ;
     RECT  130.56 29.077 132.888 29.653 ;
     RECT  134.016 28.103 134.04 29.653 ;
     RECT  135.168 28.103 135.192 29.653 ;
     RECT  137.424 28.103 138.024 29.653 ;
     RECT  139.152 28.501 139.176 29.653 ;
     RECT  140.304 28.103 140.904 29.653 ;
     RECT  142.032 27.925 143.736 29.653 ;
     RECT  144.864 28.103 144.888 29.653 ;
     RECT  146.016 28.103 146.04 29.653 ;
     RECT  147.168 27.925 147.192 29.653 ;
     RECT  148.32 28.103 148.344 29.653 ;
     RECT  149.472 29.077 152.328 29.653 ;
     RECT  153.456 29.029 154.632 29.653 ;
     RECT  155.76 27.925 157.464 29.653 ;
     RECT  159.168 28.501 160.92 29.653 ;
     RECT  162.048 28.165 162.072 29.653 ;
     RECT  163.728 28.103 163.752 29.653 ;
     RECT  164.88 29.077 167.208 29.653 ;
     RECT  168.336 28.089 168.36 29.653 ;
     RECT  4.752 29.653 129.432 29.701 ;
     RECT  130.56 29.653 168.36 29.701 ;
     RECT  4.752 29.701 168.36 30.096 ;
     RECT  8.28 0.227 8.736 0.24 ;
     RECT  8.856 0.227 9.312 0.24 ;
     RECT  28.584 0.227 29.04 0.24 ;
     RECT  29.16 0.227 29.616 0.24 ;
     RECT  29.736 0.227 30.24 0.24 ;
     RECT  30.36 0.227 30.816 0.24 ;
     RECT  34.968 0.227 35.424 0.24 ;
     RECT  35.544 0.227 36 0.24 ;
     RECT  39.624 0.227 40.08 0.24 ;
     RECT  40.2 0.227 40.656 0.24 ;
     RECT  59.928 0.227 60.384 0.24 ;
     RECT  60.504 0.227 60.96 0.24 ;
     RECT  61.656 0.227 62.112 0.24 ;
     RECT  62.232 0.227 62.688 0.24 ;
     RECT  63.384 0.227 63.84 0.24 ;
     RECT  63.96 0.227 64.464 0.24 ;
     RECT  66.888 0.227 67.344 0.24 ;
     RECT  67.464 0.227 67.92 0.24 ;
     RECT  73.272 0.227 73.728 0.24 ;
     RECT  73.848 0.227 74.304 0.24 ;
     RECT  80.232 0.227 80.688 0.24 ;
     RECT  80.808 0.227 81.264 0.24 ;
     RECT  92.424 0.227 92.88 0.24 ;
     RECT  93 0.227 93.456 0.24 ;
     RECT  98.184 0.227 98.688 0.24 ;
     RECT  98.808 0.227 99.264 0.24 ;
     RECT  99.96 0.227 100.416 0.24 ;
     RECT  100.536 0.227 100.992 0.24 ;
     RECT  103.416 0.227 103.872 0.24 ;
     RECT  103.992 0.227 104.448 0.24 ;
     RECT  104.568 0.227 105.024 0.24 ;
     RECT  105.144 0.227 105.648 0.24 ;
     RECT  108.072 0.227 108.528 0.24 ;
     RECT  108.648 0.227 109.104 0.24 ;
     RECT  123.144 0.227 123.6 0.24 ;
     RECT  123.72 0.227 124.176 0.24 ;
     RECT  127.8 0.227 128.256 0.24 ;
     RECT  128.376 0.227 128.832 0.24 ;
     RECT  130.104 0.227 130.56 0.24 ;
     RECT  130.68 0.227 131.136 0.24 ;
     RECT  131.256 0.227 131.712 0.24 ;
     RECT  131.832 0.227 132.288 0.24 ;
     RECT  133.032 0.227 133.488 0.24 ;
     RECT  133.608 0.227 134.064 0.24 ;
     RECT  134.76 0.227 135.216 0.24 ;
     RECT  135.336 0.227 135.792 0.24 ;
     RECT  159.096 0.227 159.552 0.24 ;
     RECT  159.672 0.227 160.176 0.24 ;
     RECT  161.448 0.227 161.904 0.24 ;
     RECT  162.024 0.227 162.48 0.24 ;
     RECT  165.48 0.227 165.936 0.24 ;
     RECT  166.056 0.227 166.512 0.24 ;
     RECT  8.232 0.24 9.36 1.763 ;
     RECT  28.536 0.24 29.664 1.763 ;
     RECT  29.688 0.24 30.864 1.763 ;
     RECT  34.92 0.24 36.048 2.151 ;
     RECT  39.576 0.24 40.704 1.763 ;
     RECT  59.88 0.24 61.008 1.763 ;
     RECT  61.608 0.24 62.736 1.763 ;
     RECT  63.336 0.24 64.512 1.763 ;
     RECT  66.84 0.24 67.968 1.763 ;
     RECT  73.224 0.24 74.352 1.763 ;
     RECT  80.184 0.24 81.312 1.763 ;
     RECT  92.376 0.24 93.504 1.763 ;
     RECT  98.136 0.24 99.312 1.763 ;
     RECT  99.912 0.24 101.04 0.611 ;
     RECT  103.368 0.24 104.496 1.763 ;
     RECT  104.52 0.24 105.696 1.763 ;
     RECT  108.024 0.24 109.152 1.763 ;
     RECT  123.096 0.24 124.224 1.763 ;
     RECT  127.752 0.24 128.88 0.611 ;
     RECT  130.056 0.24 131.184 0.611 ;
     RECT  131.208 0.24 132.336 0.611 ;
     RECT  132.984 0.24 134.112 1.763 ;
     RECT  134.712 0.24 135.84 0.611 ;
     RECT  159.048 0.24 160.224 1.763 ;
     RECT  161.4 0.24 162.528 1.763 ;
     RECT  165.432 0.24 166.56 1.763 ;
     RECT  58.728 0.275 59.856 1.763 ;
     RECT  25.656 0.563 26.784 2.137 ;
     RECT  93.528 0.563 94.656 1.763 ;
     RECT  128.904 0.563 130.032 1.763 ;
     RECT  27.384 0.611 28.512 1.763 ;
     RECT  37.848 0.611 38.976 1.763 ;
     RECT  99.336 0.611 101.04 1.763 ;
     RECT  132 0.611 132.336 1.763 ;
     RECT  134.136 0.611 135.84 1.763 ;
     RECT  24.312 1.763 25.632 2.243 ;
     RECT  27.384 1.763 29.664 2.137 ;
     RECT  29.688 1.763 31.536 2.151 ;
     RECT  37.848 1.763 38.136 2.197 ;
     RECT  39.984 1.763 42.9 2.137 ;
     RECT  43.212 1.763 44.208 26.149 ;
     RECT  44.232 1.763 45.6 26.291 ;
     RECT  59.1 1.763 60.168 2.137 ;
     RECT  61.8 1.763 62.112 2.137 ;
     RECT  64.5 1.763 64.512 2.137 ;
     RECT  66.96 1.763 67.512 2.137 ;
     RECT  70.212 1.763 70.392 2.773 ;
     RECT  75.612 1.763 76.992 2.773 ;
     RECT  77.016 1.763 78 13.715 ;
     RECT  79.032 1.763 81.312 2.137 ;
     RECT  81.768 1.763 83.232 2.821 ;
     RECT  86.412 1.763 87.144 2.821 ;
     RECT  91.296 1.763 91.344 2.821 ;
     RECT  91.812 1.763 91.944 2.821 ;
     RECT  94.032 1.763 94.512 2.137 ;
     RECT  99.6 1.763 99.912 2.137 ;
     RECT  105 1.763 105.312 2.137 ;
     RECT  120.912 1.763 121.2 2.821 ;
     RECT  123.9 1.763 124.212 2.137 ;
     RECT  128.928 1.763 129.612 2.137 ;
     RECT  132 1.763 132.312 2.137 ;
     RECT  134.592 1.763 135.012 2.137 ;
     RECT  138.144 1.763 140.1 2.137 ;
     RECT  140.412 1.763 140.952 2.821 ;
     RECT  159.048 1.763 159.312 2.137 ;
     RECT  161.7 1.763 162.012 2.137 ;
     RECT  25.656 2.137 26.7 2.243 ;
     RECT  27.384 2.137 29.4 2.245 ;
     RECT  39.984 2.137 40.032 2.821 ;
     RECT  40.512 2.137 42.9 2.821 ;
     RECT  59.412 2.137 60.168 2.773 ;
     RECT  66.96 2.137 67.2 2.773 ;
     RECT  79.032 2.137 80.544 13.139 ;
     RECT  99.72 2.137 99.912 2.151 ;
     RECT  128.928 2.137 129.3 2.821 ;
     RECT  134.592 2.137 134.7 2.821 ;
     RECT  134.82 2.137 135.012 2.151 ;
     RECT  137.712 2.137 140.1 2.821 ;
     RECT  159.12 2.137 159.312 2.151 ;
     RECT  29.712 2.151 31.536 2.245 ;
     RECT  37.944 2.197 38.136 2.821 ;
     RECT  27.528 2.245 29.4 2.821 ;
     RECT  30.312 2.245 31.536 2.821 ;
     RECT  75.816 2.773 76.992 13.715 ;
     RECT  41.64 2.821 42.9 13.715 ;
     RECT  82.152 2.821 83.232 14.773 ;
     RECT  137.712 2.821 139.2 14.867 ;
     RECT  79.032 13.139 80.592 13.715 ;
     RECT  40.824 13.715 42.9 14.197 ;
     RECT  75.816 13.715 78 14.197 ;
     RECT  79.032 13.715 80.7 14.197 ;
     RECT  86.52 13.715 87.144 14.197 ;
     RECT  40.824 14.197 42 15.349 ;
     RECT  76.248 14.197 77.472 25.715 ;
     RECT  79.128 14.197 80.7 14.773 ;
     RECT  86.52 14.197 87.984 24.563 ;
     RECT  94.92 14.197 96 24.563 ;
     RECT  27.012 14.291 28.08 14.867 ;
     RECT  39.984 14.291 40.032 14.435 ;
     RECT  39.984 14.435 40.08 14.773 ;
     RECT  39.048 14.773 40.08 25.763 ;
     RECT  82.248 14.773 83.232 15.349 ;
     RECT  41.592 24.563 42.9 26.243 ;
     RECT  78.936 24.563 79.968 25.571 ;
     RECT  94.824 24.563 96 25.331 ;
     RECT  49.368 25.045 50.88 25.331 ;
     RECT  49.368 25.331 51 26.243 ;
     RECT  78.744 25.571 79.968 25.715 ;
     RECT  33.48 25.715 34.656 26.291 ;
     RECT  39.048 25.763 40.2 26.291 ;
     RECT  27.144 26.149 28.56 26.387 ;
     RECT  40.512 26.243 42.9 26.773 ;
     RECT  50.832 26.243 51 26.389 ;
     RECT  78.504 26.243 78.552 27.301 ;
     RECT  115.44 26.243 115.8 27.301 ;
     RECT  40.08 26.291 40.2 26.773 ;
     RECT  29.712 26.339 30.816 26.771 ;
     RECT  30.84 26.339 31.92 26.387 ;
     RECT  30.84 26.387 32.1 26.771 ;
     RECT  53.568 26.483 53.7 27.925 ;
     RECT  54.012 26.627 54.12 27.925 ;
     RECT  59.412 26.627 60.168 27.925 ;
     RECT  102.144 26.627 102.3 27.925 ;
     RECT  64.968 26.675 65.4 26.723 ;
     RECT  89.112 26.677 90.576 26.869 ;
     RECT  64.812 26.723 65.4 27.925 ;
     RECT  29.712 26.771 32.1 27.925 ;
     RECT  50.832 26.771 51 27.925 ;
     RECT  66.96 26.771 67.104 27.925 ;
     RECT  13.512 26.773 15.024 27.349 ;
     RECT  40.512 26.773 41.904 28.089 ;
     RECT  41.928 26.773 42.9 28.501 ;
     RECT  91.812 26.819 91.944 27.925 ;
     RECT  137.712 26.819 137.832 27.925 ;
     RECT  164.064 26.819 164.4 27.877 ;
     RECT  27.012 26.867 27.144 27.925 ;
     RECT  97.212 26.867 97.368 27.925 ;
     RECT  89.112 26.869 90.528 27.925 ;
     RECT  113.412 27.301 114.576 27.925 ;
     RECT  114.6 27.301 115.8 27.925 ;
     RECT  21.612 27.923 21.72 27.925 ;
     RECT  8.112 27.925 9.312 28.021 ;
     RECT  9.336 27.925 10.5 28.103 ;
     RECT  21.612 27.925 23.04 29.029 ;
     RECT  24.792 27.925 25.92 28.501 ;
     RECT  28.2 27.925 29.28 28.453 ;
     RECT  30.504 27.925 31.632 28.501 ;
     RECT  54.012 27.925 55.056 28.089 ;
     RECT  59.688 27.925 60.768 29.077 ;
     RECT  60.792 27.925 61.8 28.453 ;
     RECT  68.232 27.925 69.36 29.653 ;
     RECT  70.536 27.925 71.664 29.077 ;
     RECT  78.552 27.925 79.68 28.501 ;
     RECT  81.96 27.925 83.088 28.453 ;
     RECT  87.144 27.925 88.224 29.653 ;
     RECT  89.4 27.925 90.528 29.653 ;
     RECT  111.144 27.925 112.272 29.077 ;
     RECT  114.6 27.925 115.68 29.077 ;
     RECT  116.856 27.925 117.984 29.653 ;
     RECT  126.912 27.925 128.304 28.103 ;
     RECT  128.328 27.925 129.3 28.103 ;
     RECT  132.888 27.925 134.016 29.653 ;
     RECT  140.904 27.925 142.032 29.653 ;
     RECT  143.736 27.925 144.864 29.653 ;
     RECT  146.04 27.925 147.168 29.653 ;
     RECT  147.192 27.925 148.2 28.103 ;
     RECT  160.344 27.925 161.7 28.103 ;
     RECT  165.48 27.925 166.608 28.261 ;
     RECT  33.384 27.973 34.464 28.453 ;
     RECT  168.36 27.973 169.8 28.103 ;
     RECT  40.32 28.089 41.904 28.103 ;
     RECT  51.12 28.089 52.224 28.103 ;
     RECT  53.82 28.089 55.056 28.103 ;
     RECT  124.02 28.089 124.212 28.103 ;
     RECT  148.344 28.089 148.512 29.077 ;
     RECT  151.02 28.089 151.212 28.103 ;
     RECT  167.22 28.089 168.336 28.103 ;
     RECT  4.776 28.103 5.412 28.501 ;
     RECT  9.336 28.103 11.04 29.077 ;
     RECT  13.2 28.103 13.872 28.501 ;
     RECT  15.624 28.103 16.752 29.653 ;
     RECT  26.52 28.103 27.6 29.653 ;
     RECT  31.656 28.103 32.784 29.077 ;
     RECT  36.792 28.103 37.92 29.653 ;
     RECT  40.248 28.103 41.904 29.077 ;
     RECT  45.384 28.103 46.512 29.653 ;
     RECT  51.096 28.103 52.224 29.077 ;
     RECT  53.4 28.103 55.056 29.077 ;
     RECT  56.232 28.103 57.36 29.653 ;
     RECT  74.52 28.103 76.224 29.077 ;
     RECT  93.432 28.103 94.512 28.165 ;
     RECT  112.296 28.103 113.424 29.653 ;
     RECT  123.9 28.103 124.212 28.213 ;
     RECT  126.6 28.103 128.304 28.501 ;
     RECT  131.904 28.103 132.288 28.453 ;
     RECT  134.04 28.103 135.168 29.653 ;
     RECT  140.1 28.103 140.304 28.501 ;
     RECT  144.888 28.103 146.016 29.653 ;
     RECT  147.192 28.103 148.32 29.653 ;
     RECT  150.9 28.103 151.212 29.077 ;
     RECT  160.344 28.103 162.012 28.165 ;
     RECT  163.752 28.103 165.456 29.077 ;
     RECT  167.208 28.103 168.336 29.653 ;
     RECT  93.432 28.165 94.56 29.653 ;
     RECT  160.344 28.165 162.048 28.501 ;
     RECT  122.568 28.213 124.212 28.501 ;
     RECT  40.08 28.259 40.224 29.653 ;
     RECT  35.208 28.453 36.192 28.501 ;
     RECT  94.584 28.453 95.664 29.653 ;
     RECT  95.688 28.453 96.816 29.077 ;
     RECT  131.16 28.453 132.288 29.077 ;
     RECT  4.776 28.501 5.904 29.653 ;
     RECT  11.64 28.501 12.768 29.653 ;
     RECT  12.792 28.501 13.872 29.653 ;
     RECT  19.656 28.501 20.736 29.653 ;
     RECT  48.792 28.501 49.92 29.653 ;
     RECT  119.736 28.501 120.864 29.653 ;
     RECT  122.568 28.501 123.696 29.029 ;
     RECT  123.72 28.501 124.212 29.077 ;
     RECT  126.6 28.501 127.152 29.077 ;
     RECT  127.176 28.501 128.304 29.653 ;
     RECT  138.024 28.501 139.152 29.653 ;
     RECT  139.176 28.501 140.304 29.653 ;
     RECT  160.92 28.501 162.048 29.653 ;
     RECT  21.912 29.029 23.04 29.653 ;
     RECT  154.632 29.029 155.76 29.653 ;
     RECT  9.912 29.077 11.04 29.173 ;
     RECT  40.248 29.077 41.328 29.653 ;
     RECT  53.928 29.077 55.056 29.653 ;
     RECT  75.096 29.077 76.224 29.653 ;
     RECT  123.72 29.077 124.848 29.653 ;
     RECT  148.344 29.077 149.472 29.653 ;
     RECT  152.328 29.077 153.456 29.653 ;
     RECT  163.752 29.077 164.88 29.653 ;
     RECT  129.432 29.653 130.56 29.701 ;
  END
END dsfd_sstn_e0e1c0c1sinf
END LIBRARY
